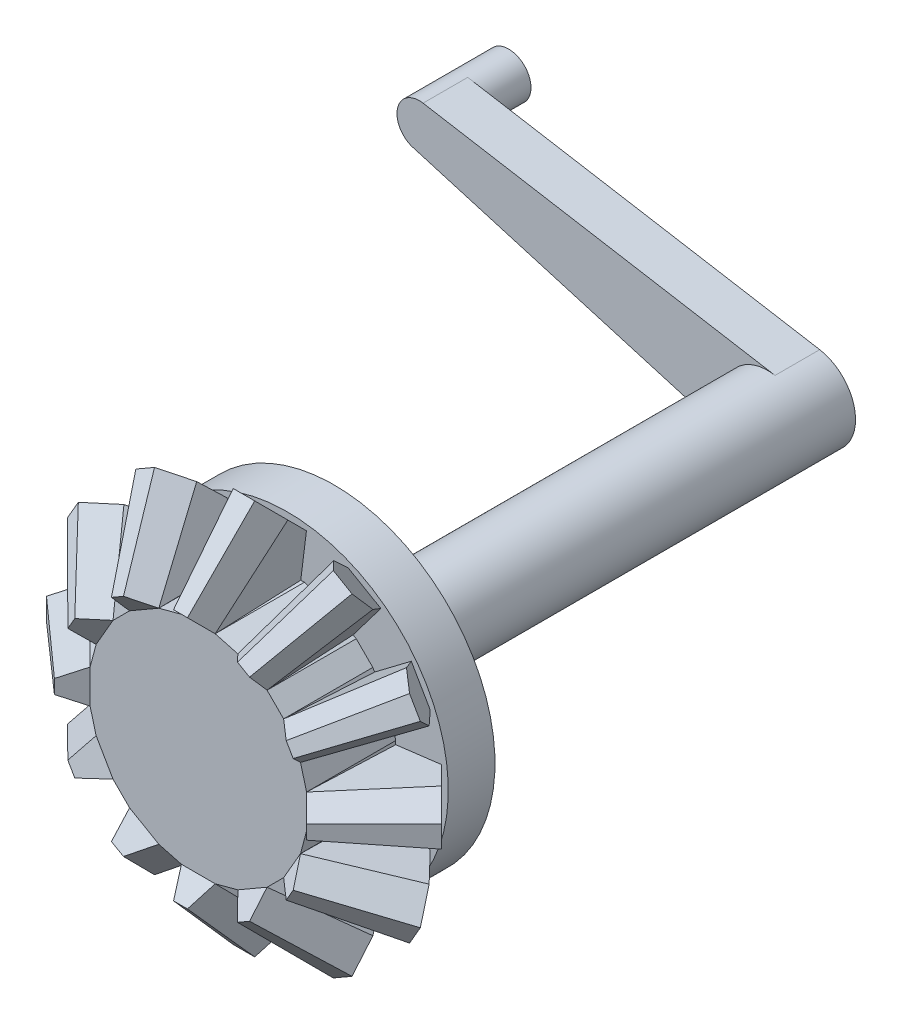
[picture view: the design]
ISO-10303-21;
HEADER;
FILE_DESCRIPTION(('STEP AP214'),'2;1');
FILE_NAME('part.step','',(''),(''),'','','');
FILE_SCHEMA(('AUTOMOTIVE_DESIGN { 1 0 10303 214 1 1 1 1 }'));
ENDSEC;
DATA;
#1=APPLICATION_CONTEXT('core data for automotive mechanical design processes');
#2=APPLICATION_PROTOCOL_DEFINITION('international standard','automotive_design',2000,#1);
#3=PRODUCT_CONTEXT('',#1,'mechanical');
#4=PRODUCT('Part','Part','',(#3));
#5=PRODUCT_RELATED_PRODUCT_CATEGORY('part','',(#4));
#6=PRODUCT_DEFINITION_FORMATION('','',#4);
#7=PRODUCT_DEFINITION_CONTEXT('part definition',#1,'design');
#8=PRODUCT_DEFINITION('design','',#6,#7);
#9=PRODUCT_DEFINITION_SHAPE('','',#8);
#10=(LENGTH_UNIT() NAMED_UNIT(*) SI_UNIT(.MILLI.,.METRE.));
#11=(NAMED_UNIT(*) PLANE_ANGLE_UNIT() SI_UNIT($,.RADIAN.));
#12=(NAMED_UNIT(*) SI_UNIT($,.STERADIAN.) SOLID_ANGLE_UNIT());
#13=UNCERTAINTY_MEASURE_WITH_UNIT(LENGTH_MEASURE(1.E-05),#10,'distance_accuracy_value','');
#14=(GEOMETRIC_REPRESENTATION_CONTEXT(3) GLOBAL_UNCERTAINTY_ASSIGNED_CONTEXT((#13)) GLOBAL_UNIT_ASSIGNED_CONTEXT((#10,
#11,#12)) REPRESENTATION_CONTEXT('',''));
#15=CARTESIAN_POINT('',(0.,0.,0.));
#16=DIRECTION('',(0.,0.,1.));
#17=DIRECTION('',(1.,0.,0.));
#18=AXIS2_PLACEMENT_3D('',#15,#16,#17);
#19=CARTESIAN_POINT('',(-1.11990909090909,0.,-91.7286207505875));
#20=DIRECTION('',(0.,0.,1.));
#21=DIRECTION('',(1.,0.,0.));
#22=AXIS2_PLACEMENT_3D('',#19,#20,#21);
#23=PLANE('',#22);
#24=DIRECTION('',(0.985868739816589,-0.167519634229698,0.));
#25=VECTOR('',#24,1.);
#26=CARTESIAN_POINT('',(2.13150734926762,12.133195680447,-91.7286207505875));
#27=LINE('',#26,#25);
#28=CARTESIAN_POINT('',(1.99577695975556,12.1562591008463,-91.7286207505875));
#29=VERTEX_POINT('',#28);
#30=CARTESIAN_POINT('',(2.13150734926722,12.1331956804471,-91.7286207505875));
#31=VERTEX_POINT('',#30);
#32=EDGE_CURVE('E11',#29,#31,#27,.T.);
#33=ORIENTED_EDGE('',*,*,#32,.F.);
#34=CARTESIAN_POINT('',(0.,0.,-91.7286207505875));
#35=DIRECTION('',(0.,0.,-1.));
#36=DIRECTION('',(-1.,0.,0.));
#37=AXIS2_PLACEMENT_3D('',#34,#35,#36);
#38=CIRCLE('',#37,12.319);
#39=EDGE_CURVE('E1470',#31,#29,#38,.F.);
#40=ORIENTED_EDGE('',*,*,#39,.F.);
#41=EDGE_LOOP('',(#33,#40));
#42=FACE_BOUND('',#41,.T.);
#43=ADVANCED_FACE('F31',(#42),#23,.F.);
#44=DIRECTION('',(-0.959413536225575,0.282002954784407,0.));
#45=VECTOR('',#44,1.);
#46=CARTESIAN_POINT('',(-3.40797278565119,-11.8382212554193,-91.7286207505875));
#47=LINE('',#46,#45);
#48=CARTESIAN_POINT('',(-3.40797278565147,-11.8382212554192,-91.7286207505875));
#49=VERTEX_POINT('',#48);
#50=CARTESIAN_POINT('',(-3.53990778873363,-11.7994412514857,-91.7286207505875));
#51=VERTEX_POINT('',#50);
#52=EDGE_CURVE('E1482',#49,#51,#47,.T.);
#53=ORIENTED_EDGE('',*,*,#52,.F.);
#54=EDGE_CURVE('E1456',#51,#49,#38,.F.);
#55=ORIENTED_EDGE('',*,*,#54,.F.);
#56=EDGE_LOOP('',(#53,#55));
#57=FACE_BOUND('',#56,.T.);
#58=ADVANCED_FACE('F1505',(#57),#23,.F.);
#59=CARTESIAN_POINT('',(-21.140822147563,30.4851911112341,76.2824021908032));
#60=DIRECTION('',(0.353553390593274,-0.612372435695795,0.707106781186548));
#61=DIRECTION('',(0.,-0.755928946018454,-0.654653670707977));
#62=AXIS2_PLACEMENT_3D('',#59,#60,#61);
#63=PLANE('',#62);
#64=DIRECTION('',(0.866025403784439,0.499999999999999,0.));
#65=VECTOR('',#64,1.);
#66=CARTESIAN_POINT('',(-19.6342231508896,30.0510904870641,75.1531605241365));
#67=LINE('',#66,#65);
#68=CARTESIAN_POINT('',(-19.6342231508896,30.0510904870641,75.1531605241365));
#69=VERTEX_POINT('',#68);
#70=CARTESIAN_POINT('',(-16.2078961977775,32.029281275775,75.1531605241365));
#71=VERTEX_POINT('',#70);
#72=EDGE_CURVE('E706',#69,#71,#67,.T.);
#73=ORIENTED_EDGE('',*,*,#72,.F.);
#74=DIRECTION('',(-0.0118343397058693,0.752940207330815,0.657982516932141));
#75=VECTOR('',#74,1.);
#76=CARTESIAN_POINT('',(-19.5430614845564,24.2510808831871,70.0846240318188));
#77=LINE('',#76,#75);
#78=CARTESIAN_POINT('',(-19.5430614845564,24.2510808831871,70.0846240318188));
#79=VERTEX_POINT('',#78);
#80=EDGE_CURVE('E711',#79,#69,#77,.T.);
#81=ORIENTED_EDGE('',*,*,#80,.F.);
#82=DIRECTION('',(-0.866025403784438,-0.5,0.));
#83=VECTOR('',#82,1.);
#84=CARTESIAN_POINT('',(-11.230521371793,29.0503281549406,70.0846240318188));
#85=LINE('',#84,#83);
#86=CARTESIAN_POINT('',(-11.230521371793,29.0503281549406,70.0846240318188));
#87=VERTEX_POINT('',#86);
#88=EDGE_CURVE('E804',#87,#79,#85,.T.);
#89=ORIENTED_EDGE('',*,*,#88,.F.);
#90=DIRECTION('',(0.646148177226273,-0.386718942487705,-0.657982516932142));
#91=VECTOR('',#90,1.);
#92=CARTESIAN_POINT('',(-16.2078961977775,32.029281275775,75.1531605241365));
#93=LINE('',#92,#91);
#94=EDGE_CURVE('E717',#71,#87,#93,.T.);
#95=ORIENTED_EDGE('',*,*,#94,.F.);
#96=EDGE_LOOP('',(#73,#81,#89,#95));
#97=FACE_BOUND('',#96,.T.);
#98=ADVANCED_FACE('F1510',(#97),#63,.T.);
#99=CARTESIAN_POINT('',(-33.5510845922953,15.8305388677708,76.2824021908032));
#100=DIRECTION('',(0.612372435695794,-0.353553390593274,0.707106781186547));
#101=DIRECTION('',(0.755928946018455,0.,-0.654653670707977));
#102=AXIS2_PLACEMENT_3D('',#99,#100,#101);
#103=PLANE('',#102);
#104=DIRECTION('',(0.499999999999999,0.866025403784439,0.));
#105=VECTOR('',#104,1.);
#106=CARTESIAN_POINT('',(-32.029281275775,16.2078961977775,75.1531605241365));
#107=LINE('',#106,#105);
#108=CARTESIAN_POINT('',(-32.029281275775,16.2078961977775,75.1531605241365));
#109=VERTEX_POINT('',#108);
#110=CARTESIAN_POINT('',(-30.051090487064,19.6342231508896,75.1531605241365));
#111=VERTEX_POINT('',#110);
#112=EDGE_CURVE('E692',#109,#111,#107,.T.);
#113=ORIENTED_EDGE('',*,*,#112,.F.);
#114=DIRECTION('',(-0.386718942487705,0.646148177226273,0.657982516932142));
#115=VECTOR('',#114,1.);
#116=CARTESIAN_POINT('',(-29.0503281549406,11.230521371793,70.0846240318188));
#117=LINE('',#116,#115);
#118=CARTESIAN_POINT('',(-29.0503281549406,11.230521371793,70.0846240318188));
#119=VERTEX_POINT('',#118);
#120=EDGE_CURVE('E697',#119,#109,#117,.T.);
#121=ORIENTED_EDGE('',*,*,#120,.F.);
#122=DIRECTION('',(-0.499999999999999,-0.866025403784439,0.));
#123=VECTOR('',#122,1.);
#124=CARTESIAN_POINT('',(-24.2510808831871,19.5430614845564,70.0846240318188));
#125=LINE('',#124,#123);
#126=CARTESIAN_POINT('',(-24.2510808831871,19.5430614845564,70.084624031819));
#127=VERTEX_POINT('',#126);
#128=EDGE_CURVE('E838',#127,#119,#125,.T.);
#129=ORIENTED_EDGE('',*,*,#128,.F.);
#130=DIRECTION('',(0.752940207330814,-0.0118343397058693,-0.657982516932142));
#131=VECTOR('',#130,1.);
#132=CARTESIAN_POINT('',(-30.051090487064,19.6342231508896,75.1531605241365));
#133=LINE('',#132,#131);
#134=EDGE_CURVE('E703',#111,#127,#133,.T.);
#135=ORIENTED_EDGE('',*,*,#134,.F.);
#136=EDGE_LOOP('',(#113,#121,#129,#135));
#137=FACE_BOUND('',#136,.T.);
#138=ADVANCED_FACE('F2340',(#137),#103,.T.);
#139=CARTESIAN_POINT('',(-36.9713610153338,-3.06589348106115,76.2824021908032));
#140=DIRECTION('',(0.707106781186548,0.,0.707106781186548));
#141=DIRECTION('',(0.707106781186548,0.,-0.707106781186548));
#142=AXIS2_PLACEMENT_3D('',#139,#140,#141);
#143=PLANE('',#142);
#144=DIRECTION('',(0.,1.,0.));
#145=VECTOR('',#144,1.);
#146=CARTESIAN_POINT('',(-35.8421193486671,-3.06589348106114,75.1531605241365));
#147=LINE('',#146,#145);
#148=CARTESIAN_POINT('',(-35.8421193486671,-1.97819078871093,75.1531605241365));
#149=VERTEX_POINT('',#148);
#150=CARTESIAN_POINT('',(-35.8421193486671,1.97819078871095,75.1531605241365));
#151=VERTEX_POINT('',#150);
#152=EDGE_CURVE('E678',#149,#151,#147,.T.);
#153=ORIENTED_EDGE('',*,*,#152,.F.);
#154=DIRECTION('',(-0.657982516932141,0.366221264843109,0.657982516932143));
#155=VECTOR('',#154,1.);
#156=CARTESIAN_POINT('',(-30.7735828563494,-4.79924727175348,70.0846240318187));
#157=LINE('',#156,#155);
#158=CARTESIAN_POINT('',(-30.7735828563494,-4.79924727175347,70.0846240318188));
#159=VERTEX_POINT('',#158);
#160=EDGE_CURVE('E683',#159,#149,#157,.T.);
#161=ORIENTED_EDGE('',*,*,#160,.F.);
#162=DIRECTION('',(0.,-1.,0.));
#163=VECTOR('',#162,1.);
#164=CARTESIAN_POINT('',(-30.7735828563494,0.,70.0846240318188));
#165=LINE('',#164,#163);
#166=CARTESIAN_POINT('',(-30.7735828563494,4.79924727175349,70.0846240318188));
#167=VERTEX_POINT('',#166);
#168=EDGE_CURVE('E835',#167,#159,#165,.T.);
#169=ORIENTED_EDGE('',*,*,#168,.F.);
#170=DIRECTION('',(0.657982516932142,0.366221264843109,-0.657982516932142));
#171=VECTOR('',#170,1.);
#172=CARTESIAN_POINT('',(-35.8421193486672,1.97819078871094,75.1531605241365));
#173=LINE('',#172,#171);
#174=EDGE_CURVE('E689',#151,#167,#173,.T.);
#175=ORIENTED_EDGE('',*,*,#174,.F.);
#176=EDGE_LOOP('',(#153,#161,#169,#175));
#177=FACE_BOUND('',#176,.T.);
#178=ADVANCED_FACE('F2347',(#177),#143,.T.);
#179=CARTESIAN_POINT('',(-30.4851911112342,-21.140822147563,76.2824021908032));
#180=DIRECTION('',(0.612372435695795,0.353553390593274,0.707106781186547));
#181=DIRECTION('',(0.755928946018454,0.,-0.654653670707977));
#182=AXIS2_PLACEMENT_3D('',#179,#180,#181);
#183=PLANE('',#182);
#184=DIRECTION('',(-0.5,0.866025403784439,0.));
#185=VECTOR('',#184,1.);
#186=CARTESIAN_POINT('',(-30.0510904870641,-19.6342231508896,75.1531605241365));
#187=LINE('',#186,#185);
#188=CARTESIAN_POINT('',(-30.0510904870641,-19.6342231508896,75.1531605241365));
#189=VERTEX_POINT('',#188);
#190=CARTESIAN_POINT('',(-32.029281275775,-16.2078961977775,75.1531605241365));
#191=VERTEX_POINT('',#190);
#192=EDGE_CURVE('E664',#189,#191,#187,.T.);
#193=ORIENTED_EDGE('',*,*,#192,.F.);
#194=DIRECTION('',(-0.752940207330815,-0.0118343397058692,0.657982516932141));
#195=VECTOR('',#194,1.);
#196=CARTESIAN_POINT('',(-24.2510808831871,-19.5430614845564,70.0846240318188));
#197=LINE('',#196,#195);
#198=CARTESIAN_POINT('',(-24.2510808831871,-19.5430614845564,70.0846240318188));
#199=VERTEX_POINT('',#198);
#200=EDGE_CURVE('E669',#199,#189,#197,.T.);
#201=ORIENTED_EDGE('',*,*,#200,.F.);
#202=DIRECTION('',(0.5,-0.866025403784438,0.));
#203=VECTOR('',#202,1.);
#204=CARTESIAN_POINT('',(-29.0503281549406,-11.230521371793,70.0846240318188));
#205=LINE('',#204,#203);
#206=CARTESIAN_POINT('',(-29.0503281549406,-11.230521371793,70.0846240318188));
#207=VERTEX_POINT('',#206);
#208=EDGE_CURVE('E832',#207,#199,#205,.T.);
#209=ORIENTED_EDGE('',*,*,#208,.F.);
#210=DIRECTION('',(0.386718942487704,0.646148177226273,-0.657982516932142));
#211=VECTOR('',#210,1.);
#212=CARTESIAN_POINT('',(-32.029281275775,-16.2078961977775,75.1531605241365));
#213=LINE('',#212,#211);
#214=EDGE_CURVE('E675',#191,#207,#213,.T.);
#215=ORIENTED_EDGE('',*,*,#214,.F.);
#216=EDGE_LOOP('',(#193,#201,#209,#215));
#217=FACE_BOUND('',#216,.T.);
#218=ADVANCED_FACE('F2355',(#217),#183,.T.);
#219=CARTESIAN_POINT('',(-15.8305388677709,-33.5510845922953,76.2824021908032));
#220=DIRECTION('',(0.353553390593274,0.612372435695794,0.707106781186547));
#221=DIRECTION('',(0.,-0.755928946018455,0.654653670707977));
#222=AXIS2_PLACEMENT_3D('',#219,#220,#221);
#223=PLANE('',#222);
#224=DIRECTION('',(-0.866025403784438,0.500000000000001,0.));
#225=VECTOR('',#224,1.);
#226=CARTESIAN_POINT('',(-16.2078961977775,-32.029281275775,75.1531605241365));
#227=LINE('',#226,#225);
#228=CARTESIAN_POINT('',(-16.2078961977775,-32.029281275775,75.1531605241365));
#229=VERTEX_POINT('',#228);
#230=CARTESIAN_POINT('',(-19.6342231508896,-30.051090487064,75.1531605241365));
#231=VERTEX_POINT('',#230);
#232=EDGE_CURVE('E650',#229,#231,#227,.T.);
#233=ORIENTED_EDGE('',*,*,#232,.F.);
#234=DIRECTION('',(-0.646148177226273,-0.386718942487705,0.657982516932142));
#235=VECTOR('',#234,1.);
#236=CARTESIAN_POINT('',(-11.230521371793,-29.0503281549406,70.0846240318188));
#237=LINE('',#236,#235);
#238=CARTESIAN_POINT('',(-11.230521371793,-29.0503281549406,70.0846240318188));
#239=VERTEX_POINT('',#238);
#240=EDGE_CURVE('E655',#239,#229,#237,.T.);
#241=ORIENTED_EDGE('',*,*,#240,.F.);
#242=DIRECTION('',(0.866025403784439,-0.5,0.));
#243=VECTOR('',#242,1.);
#244=CARTESIAN_POINT('',(-19.5430614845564,-24.2510808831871,70.0846240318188));
#245=LINE('',#244,#243);
#246=CARTESIAN_POINT('',(-19.5430614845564,-24.2510808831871,70.084624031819));
#247=VERTEX_POINT('',#246);
#248=EDGE_CURVE('E829',#247,#239,#245,.T.);
#249=ORIENTED_EDGE('',*,*,#248,.F.);
#250=DIRECTION('',(0.0118343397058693,0.752940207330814,-0.657982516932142));
#251=VECTOR('',#250,1.);
#252=CARTESIAN_POINT('',(-19.6342231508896,-30.051090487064,75.1531605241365));
#253=LINE('',#252,#251);
#254=EDGE_CURVE('E661',#231,#247,#253,.T.);
#255=ORIENTED_EDGE('',*,*,#254,.F.);
#256=EDGE_LOOP('',(#233,#241,#249,#255));
#257=FACE_BOUND('',#256,.T.);
#258=ADVANCED_FACE('F2363',(#257),#223,.T.);
#259=CARTESIAN_POINT('',(3.06589348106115,-36.9713610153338,76.2824021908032));
#260=DIRECTION('',(0.,0.707106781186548,0.707106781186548));
#261=DIRECTION('',(0.,-0.707106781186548,0.707106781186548));
#262=AXIS2_PLACEMENT_3D('',#259,#260,#261);
#263=PLANE('',#262);
#264=DIRECTION('',(1.,0.,0.));
#265=VECTOR('',#264,1.);
#266=CARTESIAN_POINT('',(3.06589348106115,-35.8421193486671,75.1531605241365));
#267=LINE('',#266,#265);
#268=CARTESIAN_POINT('',(1.97819078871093,-35.8421193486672,75.1531605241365));
#269=VERTEX_POINT('',#268);
#270=CARTESIAN_POINT('',(-1.97819078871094,-35.8421193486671,75.1531605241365));
#271=VERTEX_POINT('',#270);
#272=EDGE_CURVE('E637',#269,#271,#267,.F.);
#273=ORIENTED_EDGE('',*,*,#272,.F.);
#274=DIRECTION('',(-0.366221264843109,-0.657982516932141,0.657982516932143));
#275=VECTOR('',#274,1.);
#276=CARTESIAN_POINT('',(4.79924727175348,-30.7735828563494,70.0846240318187));
#277=LINE('',#276,#275);
#278=CARTESIAN_POINT('',(4.79924727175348,-30.7735828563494,70.0846240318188));
#279=VERTEX_POINT('',#278);
#280=EDGE_CURVE('E641',#279,#269,#277,.T.);
#281=ORIENTED_EDGE('',*,*,#280,.F.);
#282=DIRECTION('',(1.,0.,0.));
#283=VECTOR('',#282,1.);
#284=CARTESIAN_POINT('',(0.,-30.7735828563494,70.0846240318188));
#285=LINE('',#284,#283);
#286=CARTESIAN_POINT('',(-4.79924727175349,-30.7735828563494,70.0846240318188));
#287=VERTEX_POINT('',#286);
#288=EDGE_CURVE('E826',#287,#279,#285,.T.);
#289=ORIENTED_EDGE('',*,*,#288,.F.);
#290=DIRECTION('',(-0.366221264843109,0.657982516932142,-0.657982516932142));
#291=VECTOR('',#290,1.);
#292=CARTESIAN_POINT('',(-1.97819078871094,-35.8421193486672,75.1531605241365));
#293=LINE('',#292,#291);
#294=EDGE_CURVE('E647',#271,#287,#293,.T.);
#295=ORIENTED_EDGE('',*,*,#294,.F.);
#296=EDGE_LOOP('',(#273,#281,#289,#295));
#297=FACE_BOUND('',#296,.T.);
#298=ADVANCED_FACE('F2371',(#297),#263,.T.);
#299=CARTESIAN_POINT('',(21.140822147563,-30.4851911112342,76.2824021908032));
#300=DIRECTION('',(-0.353553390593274,0.612372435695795,0.707106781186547));
#301=DIRECTION('',(0.,-0.755928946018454,0.654653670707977));
#302=AXIS2_PLACEMENT_3D('',#299,#300,#301);
#303=PLANE('',#302);
#304=DIRECTION('',(-0.866025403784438,-0.5,0.));
#305=VECTOR('',#304,1.);
#306=CARTESIAN_POINT('',(19.6342231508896,-30.0510904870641,75.1531605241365));
#307=LINE('',#306,#305);
#308=CARTESIAN_POINT('',(19.6342231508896,-30.0510904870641,75.1531605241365));
#309=VERTEX_POINT('',#308);
#310=CARTESIAN_POINT('',(16.2078961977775,-32.029281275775,75.1531605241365));
#311=VERTEX_POINT('',#310);
#312=EDGE_CURVE('E790',#309,#311,#307,.T.);
#313=ORIENTED_EDGE('',*,*,#312,.F.);
#314=DIRECTION('',(0.0118343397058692,-0.752940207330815,0.657982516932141));
#315=VECTOR('',#314,1.);
#316=CARTESIAN_POINT('',(19.5430614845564,-24.2510808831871,70.0846240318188));
#317=LINE('',#316,#315);
#318=CARTESIAN_POINT('',(19.5430614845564,-24.2510808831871,70.0846240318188));
#319=VERTEX_POINT('',#318);
#320=EDGE_CURVE('E795',#319,#309,#317,.T.);
#321=ORIENTED_EDGE('',*,*,#320,.F.);
#322=DIRECTION('',(0.866025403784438,0.5,0.));
#323=VECTOR('',#322,1.);
#324=CARTESIAN_POINT('',(11.230521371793,-29.0503281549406,70.0846240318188));
#325=LINE('',#324,#323);
#326=CARTESIAN_POINT('',(11.230521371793,-29.0503281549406,70.0846240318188));
#327=VERTEX_POINT('',#326);
#328=EDGE_CURVE('E823',#327,#319,#325,.T.);
#329=ORIENTED_EDGE('',*,*,#328,.F.);
#330=DIRECTION('',(-0.646148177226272,0.386718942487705,-0.657982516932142));
#331=VECTOR('',#330,1.);
#332=CARTESIAN_POINT('',(16.2078961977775,-32.029281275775,75.1531605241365));
#333=LINE('',#332,#331);
#334=EDGE_CURVE('E801',#311,#327,#333,.T.);
#335=ORIENTED_EDGE('',*,*,#334,.F.);
#336=EDGE_LOOP('',(#313,#321,#329,#335));
#337=FACE_BOUND('',#336,.T.);
#338=ADVANCED_FACE('F1979',(#337),#303,.T.);
#339=CARTESIAN_POINT('',(33.5510845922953,-15.8305388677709,76.2824021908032));
#340=DIRECTION('',(-0.612372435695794,0.353553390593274,0.707106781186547));
#341=DIRECTION('',(0.755928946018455,0.,0.654653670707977));
#342=AXIS2_PLACEMENT_3D('',#339,#340,#341);
#343=PLANE('',#342);
#344=DIRECTION('',(-0.500000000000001,-0.866025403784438,0.));
#345=VECTOR('',#344,1.);
#346=CARTESIAN_POINT('',(32.029281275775,-16.2078961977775,75.1531605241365));
#347=LINE('',#346,#345);
#348=CARTESIAN_POINT('',(32.029281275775,-16.2078961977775,75.1531605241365));
#349=VERTEX_POINT('',#348);
#350=CARTESIAN_POINT('',(30.051090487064,-19.6342231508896,75.1531605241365));
#351=VERTEX_POINT('',#350);
#352=EDGE_CURVE('E776',#349,#351,#347,.T.);
#353=ORIENTED_EDGE('',*,*,#352,.F.);
#354=DIRECTION('',(0.386718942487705,-0.646148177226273,0.657982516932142));
#355=VECTOR('',#354,1.);
#356=CARTESIAN_POINT('',(29.0503281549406,-11.230521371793,70.0846240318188));
#357=LINE('',#356,#355);
#358=CARTESIAN_POINT('',(29.0503281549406,-11.230521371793,70.0846240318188));
#359=VERTEX_POINT('',#358);
#360=EDGE_CURVE('E781',#359,#349,#357,.T.);
#361=ORIENTED_EDGE('',*,*,#360,.F.);
#362=DIRECTION('',(0.5,0.866025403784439,0.));
#363=VECTOR('',#362,1.);
#364=CARTESIAN_POINT('',(24.2510808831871,-19.5430614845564,70.0846240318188));
#365=LINE('',#364,#363);
#366=CARTESIAN_POINT('',(24.2510808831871,-19.5430614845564,70.084624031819));
#367=VERTEX_POINT('',#366);
#368=EDGE_CURVE('E820',#367,#359,#365,.T.);
#369=ORIENTED_EDGE('',*,*,#368,.F.);
#370=DIRECTION('',(-0.752940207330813,0.0118343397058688,-0.657982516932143));
#371=VECTOR('',#370,1.);
#372=CARTESIAN_POINT('',(30.051090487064,-19.6342231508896,75.1531605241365));
#373=LINE('',#372,#371);
#374=EDGE_CURVE('E787',#351,#367,#373,.T.);
#375=ORIENTED_EDGE('',*,*,#374,.F.);
#376=EDGE_LOOP('',(#353,#361,#369,#375));
#377=FACE_BOUND('',#376,.T.);
#378=ADVANCED_FACE('F1983',(#377),#343,.T.);
#379=CARTESIAN_POINT('',(36.9713610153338,3.06589348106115,76.2824021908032));
#380=DIRECTION('',(-0.707106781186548,0.,0.707106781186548));
#381=DIRECTION('',(0.707106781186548,0.,0.707106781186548));
#382=AXIS2_PLACEMENT_3D('',#379,#380,#381);
#383=PLANE('',#382);
#384=DIRECTION('',(0.,1.,0.));
#385=VECTOR('',#384,1.);
#386=CARTESIAN_POINT('',(35.8421193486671,3.06589348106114,75.1531605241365));
#387=LINE('',#386,#385);
#388=CARTESIAN_POINT('',(35.8421193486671,1.97819078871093,75.1531605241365));
#389=VERTEX_POINT('',#388);
#390=CARTESIAN_POINT('',(35.8421193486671,-1.97819078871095,75.1531605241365));
#391=VERTEX_POINT('',#390);
#392=EDGE_CURVE('E762',#389,#391,#387,.F.);
#393=ORIENTED_EDGE('',*,*,#392,.F.);
#394=DIRECTION('',(0.657982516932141,-0.366221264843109,0.657982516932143));
#395=VECTOR('',#394,1.);
#396=CARTESIAN_POINT('',(30.7735828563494,4.79924727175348,70.0846240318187));
#397=LINE('',#396,#395);
#398=CARTESIAN_POINT('',(30.7735828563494,4.79924727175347,70.0846240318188));
#399=VERTEX_POINT('',#398);
#400=EDGE_CURVE('E767',#399,#389,#397,.T.);
#401=ORIENTED_EDGE('',*,*,#400,.F.);
#402=DIRECTION('',(0.,-1.,0.));
#403=VECTOR('',#402,1.);
#404=CARTESIAN_POINT('',(30.7735828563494,0.,70.0846240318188));
#405=LINE('',#404,#403);
#406=CARTESIAN_POINT('',(30.7735828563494,-4.79924727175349,70.0846240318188));
#407=VERTEX_POINT('',#406);
#408=EDGE_CURVE('E817',#407,#399,#405,.F.);
#409=ORIENTED_EDGE('',*,*,#408,.F.);
#410=DIRECTION('',(-0.657982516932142,-0.366221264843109,-0.657982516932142));
#411=VECTOR('',#410,1.);
#412=CARTESIAN_POINT('',(35.8421193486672,-1.97819078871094,75.1531605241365));
#413=LINE('',#412,#411);
#414=EDGE_CURVE('E773',#391,#407,#413,.T.);
#415=ORIENTED_EDGE('',*,*,#414,.F.);
#416=EDGE_LOOP('',(#393,#401,#409,#415));
#417=FACE_BOUND('',#416,.T.);
#418=ADVANCED_FACE('F2391',(#417),#383,.T.);
#419=CARTESIAN_POINT('',(30.4851911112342,21.140822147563,76.2824021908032));
#420=DIRECTION('',(-0.612372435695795,-0.353553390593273,0.707106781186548));
#421=DIRECTION('',(0.755928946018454,0.,0.654653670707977));
#422=AXIS2_PLACEMENT_3D('',#419,#420,#421);
#423=PLANE('',#422);
#424=DIRECTION('',(0.5,-0.866025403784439,0.));
#425=VECTOR('',#424,1.);
#426=CARTESIAN_POINT('',(30.0510904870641,19.6342231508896,75.1531605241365));
#427=LINE('',#426,#425);
#428=CARTESIAN_POINT('',(30.0510904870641,19.6342231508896,75.1531605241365));
#429=VERTEX_POINT('',#428);
#430=CARTESIAN_POINT('',(32.029281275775,16.2078961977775,75.1531605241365));
#431=VERTEX_POINT('',#430);
#432=EDGE_CURVE('E748',#429,#431,#427,.T.);
#433=ORIENTED_EDGE('',*,*,#432,.F.);
#434=DIRECTION('',(0.752940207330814,0.0118343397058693,0.657982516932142));
#435=VECTOR('',#434,1.);
#436=CARTESIAN_POINT('',(24.2510808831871,19.5430614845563,70.0846240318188));
#437=LINE('',#436,#435);
#438=CARTESIAN_POINT('',(24.2510808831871,19.5430614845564,70.0846240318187));
#439=VERTEX_POINT('',#438);
#440=EDGE_CURVE('E753',#439,#429,#437,.T.);
#441=ORIENTED_EDGE('',*,*,#440,.F.);
#442=DIRECTION('',(-0.5,0.866025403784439,0.));
#443=VECTOR('',#442,1.);
#444=CARTESIAN_POINT('',(29.0503281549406,11.230521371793,70.0846240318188));
#445=LINE('',#444,#443);
#446=CARTESIAN_POINT('',(29.0503281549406,11.230521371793,70.0846240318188));
#447=VERTEX_POINT('',#446);
#448=EDGE_CURVE('E814',#447,#439,#445,.T.);
#449=ORIENTED_EDGE('',*,*,#448,.F.);
#450=DIRECTION('',(-0.386718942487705,-0.646148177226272,-0.657982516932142));
#451=VECTOR('',#450,1.);
#452=CARTESIAN_POINT('',(32.029281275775,16.2078961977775,75.1531605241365));
#453=LINE('',#452,#451);
#454=EDGE_CURVE('E759',#431,#447,#453,.T.);
#455=ORIENTED_EDGE('',*,*,#454,.F.);
#456=EDGE_LOOP('',(#433,#441,#449,#455));
#457=FACE_BOUND('',#456,.T.);
#458=ADVANCED_FACE('F2398',(#457),#423,.T.);
#459=CARTESIAN_POINT('',(15.8305388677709,33.5510845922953,76.2824021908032));
#460=DIRECTION('',(-0.353553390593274,-0.612372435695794,0.707106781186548));
#461=DIRECTION('',(0.,-0.755928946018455,-0.654653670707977));
#462=AXIS2_PLACEMENT_3D('',#459,#460,#461);
#463=PLANE('',#462);
#464=DIRECTION('',(0.866025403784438,-0.500000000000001,0.));
#465=VECTOR('',#464,1.);
#466=CARTESIAN_POINT('',(16.2078961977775,32.029281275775,75.1531605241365));
#467=LINE('',#466,#465);
#468=CARTESIAN_POINT('',(16.2078961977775,32.029281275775,75.1531605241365));
#469=VERTEX_POINT('',#468);
#470=CARTESIAN_POINT('',(19.6342231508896,30.051090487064,75.1531605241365));
#471=VERTEX_POINT('',#470);
#472=EDGE_CURVE('E734',#469,#471,#467,.T.);
#473=ORIENTED_EDGE('',*,*,#472,.F.);
#474=DIRECTION('',(0.646148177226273,0.386718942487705,0.657982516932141));
#475=VECTOR('',#474,1.);
#476=CARTESIAN_POINT('',(11.230521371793,29.0503281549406,70.0846240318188));
#477=LINE('',#476,#475);
#478=CARTESIAN_POINT('',(11.230521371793,29.0503281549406,70.0846240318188));
#479=VERTEX_POINT('',#478);
#480=EDGE_CURVE('E739',#479,#469,#477,.T.);
#481=ORIENTED_EDGE('',*,*,#480,.F.);
#482=DIRECTION('',(-0.866025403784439,0.5,0.));
#483=VECTOR('',#482,1.);
#484=CARTESIAN_POINT('',(19.5430614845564,24.2510808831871,70.0846240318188));
#485=LINE('',#484,#483);
#486=CARTESIAN_POINT('',(19.5430614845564,24.2510808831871,70.084624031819));
#487=VERTEX_POINT('',#486);
#488=EDGE_CURVE('E811',#487,#479,#485,.T.);
#489=ORIENTED_EDGE('',*,*,#488,.F.);
#490=DIRECTION('',(-0.0118343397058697,-0.752940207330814,-0.657982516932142));
#491=VECTOR('',#490,1.);
#492=CARTESIAN_POINT('',(19.6342231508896,30.051090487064,75.1531605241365));
#493=LINE('',#492,#491);
#494=EDGE_CURVE('E745',#471,#487,#493,.T.);
#495=ORIENTED_EDGE('',*,*,#494,.F.);
#496=EDGE_LOOP('',(#473,#481,#489,#495));
#497=FACE_BOUND('',#496,.T.);
#498=ADVANCED_FACE('F2406',(#497),#463,.T.);
#499=CARTESIAN_POINT('',(-3.06589348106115,36.9713610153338,76.2824021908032));
#500=DIRECTION('',(0.,-0.707106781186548,0.707106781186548));
#501=DIRECTION('',(0.,-0.707106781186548,-0.707106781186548));
#502=AXIS2_PLACEMENT_3D('',#499,#500,#501);
#503=PLANE('',#502);
#504=DIRECTION('',(1.,0.,0.));
#505=VECTOR('',#504,1.);
#506=CARTESIAN_POINT('',(-3.06589348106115,35.8421193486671,75.1531605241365));
#507=LINE('',#506,#505);
#508=CARTESIAN_POINT('',(-1.97819078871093,35.8421193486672,75.1531605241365));
#509=VERTEX_POINT('',#508);
#510=CARTESIAN_POINT('',(1.97819078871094,35.8421193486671,75.1531605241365));
#511=VERTEX_POINT('',#510);
#512=EDGE_CURVE('E720',#509,#511,#507,.T.);
#513=ORIENTED_EDGE('',*,*,#512,.F.);
#514=DIRECTION('',(0.366221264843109,0.657982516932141,0.657982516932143));
#515=VECTOR('',#514,1.);
#516=CARTESIAN_POINT('',(-4.79924727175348,30.7735828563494,70.0846240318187));
#517=LINE('',#516,#515);
#518=CARTESIAN_POINT('',(-4.79924727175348,30.7735828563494,70.0846240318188));
#519=VERTEX_POINT('',#518);
#520=EDGE_CURVE('E725',#519,#509,#517,.T.);
#521=ORIENTED_EDGE('',*,*,#520,.F.);
#522=DIRECTION('',(1.,0.,0.));
#523=VECTOR('',#522,1.);
#524=CARTESIAN_POINT('',(0.,30.7735828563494,70.0846240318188));
#525=LINE('',#524,#523);
#526=CARTESIAN_POINT('',(4.79924727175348,30.7735828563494,70.0846240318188));
#527=VERTEX_POINT('',#526);
#528=EDGE_CURVE('E807',#527,#519,#525,.F.);
#529=ORIENTED_EDGE('',*,*,#528,.F.);
#530=DIRECTION('',(0.36622126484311,-0.657982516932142,-0.657982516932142));
#531=VECTOR('',#530,1.);
#532=CARTESIAN_POINT('',(1.97819078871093,35.8421193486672,75.1531605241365));
#533=LINE('',#532,#531);
#534=EDGE_CURVE('E731',#511,#527,#533,.T.);
#535=ORIENTED_EDGE('',*,*,#534,.F.);
#536=EDGE_LOOP('',(#513,#521,#529,#535));
#537=FACE_BOUND('',#536,.T.);
#538=ADVANCED_FACE('F2414',(#537),#503,.T.);
#539=CARTESIAN_POINT('',(3.06589348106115,-56.1352275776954,57.1185356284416));
#540=DIRECTION('',(0.,-0.664287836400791,0.747476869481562));
#541=DIRECTION('',(0.,-0.747476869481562,-0.664287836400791));
#542=AXIS2_PLACEMENT_3D('',#539,#540,#541);
#543=PLANE('',#542);
#544=DIRECTION('',(0.0400323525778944,-0.746877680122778,-0.663755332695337));
#545=VECTOR('',#544,1.);
#546=CARTESIAN_POINT('',(1.97819078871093,-35.8421193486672,75.1531605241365));
#547=LINE('',#546,#545);
#548=CARTESIAN_POINT('',(3.06589348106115,-56.1352275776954,57.1185356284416));
#549=VERTEX_POINT('',#548);
#550=EDGE_CURVE('E639',#269,#549,#547,.T.);
#551=ORIENTED_EDGE('',*,*,#550,.F.);
#552=ORIENTED_EDGE('',*,*,#272,.T.);
#553=DIRECTION('',(0.0400323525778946,0.746877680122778,0.663755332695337));
#554=VECTOR('',#553,1.);
#555=CARTESIAN_POINT('',(-3.06589348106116,-56.1352275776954,57.1185356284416));
#556=LINE('',#555,#554);
#557=CARTESIAN_POINT('',(-3.06589348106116,-56.1352275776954,57.1185356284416));
#558=VERTEX_POINT('',#557);
#559=EDGE_CURVE('E644',#558,#271,#556,.T.);
#560=ORIENTED_EDGE('',*,*,#559,.F.);
#561=DIRECTION('',(1.,0.,0.));
#562=VECTOR('',#561,1.);
#563=CARTESIAN_POINT('',(-0.0109063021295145,-56.1352275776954,57.1185356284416));
#564=LINE('',#563,#562);
#565=EDGE_CURVE('E854',#558,#549,#564,.T.);
#566=ORIENTED_EDGE('',*,*,#565,.T.);
#567=EDGE_LOOP('',(#551,#552,#560,#566));
#568=FACE_BOUND('',#567,.T.);
#569=ADVANCED_FACE('F2422',(#568),#543,.T.);
#570=CARTESIAN_POINT('',(6.43180864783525,-50.0877542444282,51.0710622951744));
#571=DIRECTION('',(0.928916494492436,-0.216914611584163,0.300103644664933));
#572=DIRECTION('',(0.307423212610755,0.,-0.951572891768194));
#573=AXIS2_PLACEMENT_3D('',#570,#571,#572);
#574=PLANE('',#573);
#575=DIRECTION('',(0.0601272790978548,-0.711341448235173,-0.700269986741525));
#576=VECTOR('',#575,1.);
#577=CARTESIAN_POINT('',(4.79924727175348,-30.7735828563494,70.0846240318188));
#578=LINE('',#577,#576);
#579=CARTESIAN_POINT('',(6.43180864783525,-50.0877542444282,51.0710622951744));
#580=VERTEX_POINT('',#579);
#581=EDGE_CURVE('E843',#279,#580,#578,.T.);
#582=ORIENTED_EDGE('',*,*,#581,.F.);
#583=ORIENTED_EDGE('',*,*,#280,.T.);
#584=ORIENTED_EDGE('',*,*,#550,.T.);
#585=DIRECTION('',(0.366221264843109,0.657982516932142,-0.657982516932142));
#586=VECTOR('',#585,1.);
#587=CARTESIAN_POINT('',(3.06589348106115,-56.1352275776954,57.1185356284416));
#588=LINE('',#587,#586);
#589=EDGE_CURVE('E852',#549,#580,#588,.T.);
#590=ORIENTED_EDGE('',*,*,#589,.T.);
#591=EDGE_LOOP('',(#582,#583,#584,#590));
#592=FACE_BOUND('',#591,.T.);
#593=ADVANCED_FACE('F1839',(#592),#574,.T.);
#594=CARTESIAN_POINT('',(-3.06589348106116,-56.1352275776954,57.1185356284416));
#595=DIRECTION('',(-0.928916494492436,-0.216914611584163,0.300103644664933));
#596=DIRECTION('',(0.307423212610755,0.,0.951572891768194));
#597=AXIS2_PLACEMENT_3D('',#594,#595,#596);
#598=PLANE('',#597);
#599=ORIENTED_EDGE('',*,*,#559,.T.);
#600=ORIENTED_EDGE('',*,*,#294,.T.);
#601=DIRECTION('',(0.060127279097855,0.711341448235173,0.700269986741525));
#602=VECTOR('',#601,1.);
#603=CARTESIAN_POINT('',(-6.43180864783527,-50.0877542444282,51.0710622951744));
#604=LINE('',#603,#602);
#605=CARTESIAN_POINT('',(-6.43180864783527,-50.0877542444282,51.0710622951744));
#606=VERTEX_POINT('',#605);
#607=EDGE_CURVE('E858',#606,#287,#604,.T.);
#608=ORIENTED_EDGE('',*,*,#607,.F.);
#609=DIRECTION('',(0.366221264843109,-0.657982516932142,0.657982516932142));
#610=VECTOR('',#609,1.);
#611=CARTESIAN_POINT('',(-6.43180864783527,-50.0877542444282,51.0710622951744));
#612=LINE('',#611,#610);
#613=EDGE_CURVE('E846',#606,#558,#612,.T.);
#614=ORIENTED_EDGE('',*,*,#613,.T.);
#615=EDGE_LOOP('',(#599,#600,#608,#614));
#616=FACE_BOUND('',#615,.T.);
#617=ADVANCED_FACE('F2437',(#616),#598,.T.);
#618=CARTESIAN_POINT('',(-25.4124721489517,-50.1474798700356,57.1185356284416));
#619=DIRECTION('',(-0.332143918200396,-0.575290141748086,0.747476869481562));
#620=DIRECTION('',(0.,-0.792466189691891,-0.609915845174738));
#621=AXIS2_PLACEMENT_3D('',#618,#619,#620);
#622=PLANE('',#621);
#623=DIRECTION('',(-0.338769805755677,-0.66683122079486,-0.663755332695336));
#624=VECTOR('',#623,1.);
#625=CARTESIAN_POINT('',(-16.2078961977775,-32.029281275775,75.1531605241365));
#626=LINE('',#625,#624);
#627=CARTESIAN_POINT('',(-25.4124721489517,-50.1474798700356,57.1185356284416));
#628=VERTEX_POINT('',#627);
#629=EDGE_CURVE('E654',#229,#628,#626,.T.);
#630=ORIENTED_EDGE('',*,*,#629,.F.);
#631=ORIENTED_EDGE('',*,*,#232,.T.);
#632=DIRECTION('',(0.408107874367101,0.626798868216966,0.663755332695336));
#633=VECTOR('',#632,1.);
#634=CARTESIAN_POINT('',(-30.7227554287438,-47.0815863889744,57.1185356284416));
#635=LINE('',#634,#633);
#636=CARTESIAN_POINT('',(-30.7227554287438,-47.0815863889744,57.1185356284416));
#637=VERTEX_POINT('',#636);
#638=EDGE_CURVE('E658',#637,#231,#635,.T.);
#639=ORIENTED_EDGE('',*,*,#638,.F.);
#640=DIRECTION('',(0.866025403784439,-0.5,0.));
#641=VECTOR('',#640,1.);
#642=CARTESIAN_POINT('',(-30.7227554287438,-47.0815863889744,57.1185356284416));
#643=LINE('',#642,#641);
#644=EDGE_CURVE('E887',#637,#628,#643,.T.);
#645=ORIENTED_EDGE('',*,*,#644,.T.);
#646=EDGE_LOOP('',(#630,#631,#639,#645));
#647=FACE_BOUND('',#646,.T.);
#648=ADVANCED_FACE('F2444',(#647),#622,.T.);
#649=CARTESIAN_POINT('',(-19.4737674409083,-46.5931719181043,51.0710622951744));
#650=DIRECTION('',(0.696007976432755,-0.652311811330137,0.300103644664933));
#651=DIRECTION('',(0.683831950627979,0.729639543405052,0.));
#652=AXIS2_PLACEMENT_3D('',#649,#650,#651);
#653=PLANE('',#652);
#654=DIRECTION('',(-0.303598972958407,-0.6461034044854,-0.700269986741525));
#655=VECTOR('',#654,1.);
#656=CARTESIAN_POINT('',(-11.230521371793,-29.0503281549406,70.0846240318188));
#657=LINE('',#656,#655);
#658=CARTESIAN_POINT('',(-19.4737674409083,-46.5931719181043,51.0710622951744));
#659=VERTEX_POINT('',#658);
#660=EDGE_CURVE('E876',#239,#659,#657,.T.);
#661=ORIENTED_EDGE('',*,*,#660,.F.);
#662=ORIENTED_EDGE('',*,*,#240,.T.);
#663=ORIENTED_EDGE('',*,*,#629,.T.);
#664=DIRECTION('',(0.646148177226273,0.386718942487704,-0.657982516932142));
#665=VECTOR('',#664,1.);
#666=CARTESIAN_POINT('',(-25.4124721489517,-50.1474798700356,57.1185356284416));
#667=LINE('',#666,#665);
#668=EDGE_CURVE('E885',#628,#659,#667,.T.);
#669=ORIENTED_EDGE('',*,*,#668,.T.);
#670=EDGE_LOOP('',(#661,#662,#663,#669));
#671=FACE_BOUND('',#670,.T.);
#672=ADVANCED_FACE('F2452',(#671),#653,.T.);
#673=CARTESIAN_POINT('',(-30.7227554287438,-47.0815863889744,57.1185356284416));
#674=DIRECTION('',(-0.912922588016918,0.276604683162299,0.300103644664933));
#675=DIRECTION('',(0.312287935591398,0.,0.949987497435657));
#676=AXIS2_PLACEMENT_3D('',#673,#674,#675);
#677=PLANE('',#676);
#678=ORIENTED_EDGE('',*,*,#638,.T.);
#679=ORIENTED_EDGE('',*,*,#254,.T.);
#680=DIRECTION('',(0.407742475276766,0.585976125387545,0.700269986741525));
#681=VECTOR('',#680,1.);
#682=CARTESIAN_POINT('',(-30.6139868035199,-40.161363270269,51.0710622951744));
#683=LINE('',#682,#681);
#684=CARTESIAN_POINT('',(-30.6139868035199,-40.161363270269,51.0710622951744));
#685=VERTEX_POINT('',#684);
#686=EDGE_CURVE('E891',#685,#247,#683,.T.);
#687=ORIENTED_EDGE('',*,*,#686,.F.);
#688=DIRECTION('',(-0.01183433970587,-0.752940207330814,0.657982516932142));
#689=VECTOR('',#688,1.);
#690=CARTESIAN_POINT('',(-30.6139868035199,-40.161363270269,51.0710622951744));
#691=LINE('',#690,#689);
#692=EDGE_CURVE('E879',#685,#637,#691,.T.);
#693=ORIENTED_EDGE('',*,*,#692,.T.);
#694=EDGE_LOOP('',(#678,#679,#687,#693));
#695=FACE_BOUND('',#694,.T.);
#696=ADVANCED_FACE('F2460',(#695),#677,.T.);
#697=CARTESIAN_POINT('',(-47.0815863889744,-30.7227554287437,57.1185356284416));
#698=DIRECTION('',(-0.575290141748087,-0.332143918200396,0.747476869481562));
#699=DIRECTION('',(0.792466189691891,0.,0.609915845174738));
#700=AXIS2_PLACEMENT_3D('',#697,#698,#699);
#701=PLANE('',#700);
#702=DIRECTION('',(-0.626798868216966,-0.408107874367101,-0.663755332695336));
#703=VECTOR('',#702,1.);
#704=CARTESIAN_POINT('',(-30.0510904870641,-19.6342231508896,75.1531605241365));
#705=LINE('',#704,#703);
#706=CARTESIAN_POINT('',(-47.0815863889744,-30.7227554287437,57.1185356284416));
#707=VERTEX_POINT('',#706);
#708=EDGE_CURVE('E668',#189,#707,#705,.T.);
#709=ORIENTED_EDGE('',*,*,#708,.F.);
#710=ORIENTED_EDGE('',*,*,#192,.T.);
#711=DIRECTION('',(0.666831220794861,0.338769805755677,0.663755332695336));
#712=VECTOR('',#711,1.);
#713=CARTESIAN_POINT('',(-50.1474798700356,-25.4124721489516,57.1185356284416));
#714=LINE('',#713,#712);
#715=CARTESIAN_POINT('',(-50.1474798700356,-25.4124721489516,57.1185356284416));
#716=VERTEX_POINT('',#715);
#717=EDGE_CURVE('E672',#716,#191,#714,.T.);
#718=ORIENTED_EDGE('',*,*,#717,.F.);
#719=DIRECTION('',(0.5,-0.866025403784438,0.));
#720=VECTOR('',#719,1.);
#721=CARTESIAN_POINT('',(-50.1474798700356,-25.4124721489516,57.1185356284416));
#722=LINE('',#721,#720);
#723=EDGE_CURVE('E920',#716,#707,#722,.T.);
#724=ORIENTED_EDGE('',*,*,#723,.T.);
#725=EDGE_LOOP('',(#709,#710,#718,#724));
#726=FACE_BOUND('',#725,.T.);
#727=ADVANCED_FACE('F2468',(#726),#701,.T.);
#728=CARTESIAN_POINT('',(-40.161363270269,-30.6139868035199,51.0710622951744));
#729=DIRECTION('',(0.276604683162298,-0.912922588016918,0.300103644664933));
#730=DIRECTION('',(0.,-0.312287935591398,-0.949987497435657));
#731=AXIS2_PLACEMENT_3D('',#728,#729,#730);
#732=PLANE('',#731);
#733=DIRECTION('',(-0.585976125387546,-0.407742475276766,-0.700269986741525));
#734=VECTOR('',#733,1.);
#735=CARTESIAN_POINT('',(-24.2510808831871,-19.5430614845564,70.0846240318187));
#736=LINE('',#735,#734);
#737=CARTESIAN_POINT('',(-40.161363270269,-30.6139868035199,51.0710622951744));
#738=VERTEX_POINT('',#737);
#739=EDGE_CURVE('E909',#199,#738,#736,.T.);
#740=ORIENTED_EDGE('',*,*,#739,.F.);
#741=ORIENTED_EDGE('',*,*,#200,.T.);
#742=ORIENTED_EDGE('',*,*,#708,.T.);
#743=DIRECTION('',(0.752940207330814,0.0118343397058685,-0.657982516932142));
#744=VECTOR('',#743,1.);
#745=CARTESIAN_POINT('',(-47.0815863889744,-30.7227554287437,57.1185356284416));
#746=LINE('',#745,#744);
#747=EDGE_CURVE('E918',#707,#738,#746,.T.);
#748=ORIENTED_EDGE('',*,*,#747,.T.);
#749=EDGE_LOOP('',(#740,#741,#742,#748));
#750=FACE_BOUND('',#749,.T.);
#751=ADVANCED_FACE('F2476',(#750),#732,.T.);
#752=CARTESIAN_POINT('',(-50.1474798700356,-25.4124721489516,57.1185356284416));
#753=DIRECTION('',(-0.652311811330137,0.696007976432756,0.300103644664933));
#754=DIRECTION('',(-0.729639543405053,-0.683831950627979,0.));
#755=AXIS2_PLACEMENT_3D('',#752,#753,#754);
#756=PLANE('',#755);
#757=ORIENTED_EDGE('',*,*,#717,.T.);
#758=ORIENTED_EDGE('',*,*,#214,.T.);
#759=DIRECTION('',(0.6461034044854,0.303598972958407,0.700269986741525));
#760=VECTOR('',#759,1.);
#761=CARTESIAN_POINT('',(-46.5931719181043,-19.4737674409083,51.0710622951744));
#762=LINE('',#761,#760);
#763=CARTESIAN_POINT('',(-46.5931719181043,-19.4737674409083,51.0710622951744));
#764=VERTEX_POINT('',#763);
#765=EDGE_CURVE('E924',#764,#207,#762,.T.);
#766=ORIENTED_EDGE('',*,*,#765,.F.);
#767=DIRECTION('',(-0.386718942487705,-0.646148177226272,0.657982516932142));
#768=VECTOR('',#767,1.);
#769=CARTESIAN_POINT('',(-46.5931719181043,-19.4737674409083,51.0710622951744));
#770=LINE('',#769,#768);
#771=EDGE_CURVE('E912',#764,#716,#770,.T.);
#772=ORIENTED_EDGE('',*,*,#771,.T.);
#773=EDGE_LOOP('',(#757,#758,#766,#772));
#774=FACE_BOUND('',#773,.T.);
#775=ADVANCED_FACE('F2484',(#774),#756,.T.);
#776=CARTESIAN_POINT('',(-56.1352275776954,-3.06589348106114,57.1185356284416));
#777=DIRECTION('',(-0.664287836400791,0.,0.747476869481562));
#778=DIRECTION('',(0.747476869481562,0.,0.664287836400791));
#779=AXIS2_PLACEMENT_3D('',#776,#777,#778);
#780=PLANE('',#779);
#781=DIRECTION('',(-0.746877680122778,-0.0400323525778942,-0.663755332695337));
#782=VECTOR('',#781,1.);
#783=CARTESIAN_POINT('',(-35.8421193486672,-1.97819078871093,75.1531605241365));
#784=LINE('',#783,#782);
#785=CARTESIAN_POINT('',(-56.1352275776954,-3.06589348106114,57.1185356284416));
#786=VERTEX_POINT('',#785);
#787=EDGE_CURVE('E682',#149,#786,#784,.T.);
#788=ORIENTED_EDGE('',*,*,#787,.F.);
#789=ORIENTED_EDGE('',*,*,#152,.T.);
#790=DIRECTION('',(0.746877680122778,-0.0400323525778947,0.663755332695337));
#791=VECTOR('',#790,1.);
#792=CARTESIAN_POINT('',(-56.1352275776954,3.06589348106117,57.1185356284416));
#793=LINE('',#792,#791);
#794=CARTESIAN_POINT('',(-56.1352275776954,3.06589348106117,57.1185356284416));
#795=VERTEX_POINT('',#794);
#796=EDGE_CURVE('E686',#795,#151,#793,.T.);
#797=ORIENTED_EDGE('',*,*,#796,.F.);
#798=DIRECTION('',(0.,1.,0.));
#799=VECTOR('',#798,1.);
#800=CARTESIAN_POINT('',(-56.1352275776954,0.0109063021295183,57.1185356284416));
#801=LINE('',#800,#799);
#802=EDGE_CURVE('E953',#795,#786,#801,.F.);
#803=ORIENTED_EDGE('',*,*,#802,.T.);
#804=EDGE_LOOP('',(#788,#789,#797,#803));
#805=FACE_BOUND('',#804,.T.);
#806=ADVANCED_FACE('F2492',(#805),#780,.T.);
#807=CARTESIAN_POINT('',(-50.0877542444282,-6.43180864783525,51.0710622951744));
#808=DIRECTION('',(-0.216914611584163,-0.928916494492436,0.300103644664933));
#809=DIRECTION('',(0.,-0.307423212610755,-0.951572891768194));
#810=AXIS2_PLACEMENT_3D('',#807,#808,#809);
#811=PLANE('',#810);
#812=DIRECTION('',(-0.711341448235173,-0.0601272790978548,-0.700269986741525));
#813=VECTOR('',#812,1.);
#814=CARTESIAN_POINT('',(-30.7735828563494,-4.79924727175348,70.0846240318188));
#815=LINE('',#814,#813);
#816=CARTESIAN_POINT('',(-50.0877542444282,-6.43180864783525,51.0710622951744));
#817=VERTEX_POINT('',#816);
#818=EDGE_CURVE('E942',#159,#817,#815,.T.);
#819=ORIENTED_EDGE('',*,*,#818,.F.);
#820=ORIENTED_EDGE('',*,*,#160,.T.);
#821=ORIENTED_EDGE('',*,*,#787,.T.);
#822=DIRECTION('',(0.657982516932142,-0.366221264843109,-0.657982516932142));
#823=VECTOR('',#822,1.);
#824=CARTESIAN_POINT('',(-56.1352275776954,-3.06589348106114,57.1185356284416));
#825=LINE('',#824,#823);
#826=EDGE_CURVE('E951',#786,#817,#825,.T.);
#827=ORIENTED_EDGE('',*,*,#826,.T.);
#828=EDGE_LOOP('',(#819,#820,#821,#827));
#829=FACE_BOUND('',#828,.T.);
#830=ADVANCED_FACE('F2500',(#829),#811,.T.);
#831=CARTESIAN_POINT('',(-56.1352275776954,3.06589348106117,57.1185356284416));
#832=DIRECTION('',(-0.216914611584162,0.928916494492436,0.300103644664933));
#833=DIRECTION('',(0.,-0.307423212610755,0.951572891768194));
#834=AXIS2_PLACEMENT_3D('',#831,#832,#833);
#835=PLANE('',#834);
#836=ORIENTED_EDGE('',*,*,#796,.T.);
#837=ORIENTED_EDGE('',*,*,#174,.T.);
#838=DIRECTION('',(0.711341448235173,-0.0601272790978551,0.700269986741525));
#839=VECTOR('',#838,1.);
#840=CARTESIAN_POINT('',(-50.0877542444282,6.43180864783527,51.0710622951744));
#841=LINE('',#840,#839);
#842=CARTESIAN_POINT('',(-50.0877542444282,6.43180864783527,51.0710622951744));
#843=VERTEX_POINT('',#842);
#844=EDGE_CURVE('E957',#843,#167,#841,.T.);
#845=ORIENTED_EDGE('',*,*,#844,.F.);
#846=DIRECTION('',(-0.657982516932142,-0.366221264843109,0.657982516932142));
#847=VECTOR('',#846,1.);
#848=CARTESIAN_POINT('',(-50.0877542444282,6.43180864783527,51.0710622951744));
#849=LINE('',#848,#847);
#850=EDGE_CURVE('E945',#843,#795,#849,.T.);
#851=ORIENTED_EDGE('',*,*,#850,.T.);
#852=EDGE_LOOP('',(#836,#837,#845,#851));
#853=FACE_BOUND('',#852,.T.);
#854=ADVANCED_FACE('F2508',(#853),#835,.T.);
#855=CARTESIAN_POINT('',(-50.1474798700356,25.4124721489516,57.1185356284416));
#856=DIRECTION('',(-0.575290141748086,0.332143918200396,0.747476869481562));
#857=DIRECTION('',(0.792466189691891,0.,0.609915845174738));
#858=AXIS2_PLACEMENT_3D('',#855,#856,#857);
#859=PLANE('',#858);
#860=DIRECTION('',(-0.66683122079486,0.338769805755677,-0.663755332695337));
#861=VECTOR('',#860,1.);
#862=CARTESIAN_POINT('',(-32.029281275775,16.2078961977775,75.1531605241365));
#863=LINE('',#862,#861);
#864=CARTESIAN_POINT('',(-50.1474798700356,25.4124721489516,57.1185356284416));
#865=VERTEX_POINT('',#864);
#866=EDGE_CURVE('E696',#109,#865,#863,.T.);
#867=ORIENTED_EDGE('',*,*,#866,.F.);
#868=ORIENTED_EDGE('',*,*,#112,.T.);
#869=DIRECTION('',(0.626798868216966,-0.408107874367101,0.663755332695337));
#870=VECTOR('',#869,1.);
#871=CARTESIAN_POINT('',(-47.0815863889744,30.7227554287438,57.1185356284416));
#872=LINE('',#871,#870);
#873=CARTESIAN_POINT('',(-47.0815863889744,30.7227554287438,57.1185356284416));
#874=VERTEX_POINT('',#873);
#875=EDGE_CURVE('E700',#874,#111,#872,.T.);
#876=ORIENTED_EDGE('',*,*,#875,.F.);
#877=DIRECTION('',(-0.5,-0.866025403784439,0.));
#878=VECTOR('',#877,1.);
#879=CARTESIAN_POINT('',(-47.0815863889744,30.7227554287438,57.1185356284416));
#880=LINE('',#879,#878);
#881=EDGE_CURVE('E986',#874,#865,#880,.T.);
#882=ORIENTED_EDGE('',*,*,#881,.T.);
#883=EDGE_LOOP('',(#867,#868,#876,#882));
#884=FACE_BOUND('',#883,.T.);
#885=ADVANCED_FACE('F2516',(#884),#859,.T.);
#886=CARTESIAN_POINT('',(-46.5931719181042,19.4737674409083,51.0710622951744));
#887=DIRECTION('',(-0.652311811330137,-0.696007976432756,0.300103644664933));
#888=DIRECTION('',(0.729639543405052,-0.683831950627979,0.));
#889=AXIS2_PLACEMENT_3D('',#886,#887,#888);
#890=PLANE('',#889);
#891=DIRECTION('',(-0.6461034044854,0.303598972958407,-0.700269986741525));
#892=VECTOR('',#891,1.);
#893=CARTESIAN_POINT('',(-29.0503281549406,11.230521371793,70.0846240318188));
#894=LINE('',#893,#892);
#895=CARTESIAN_POINT('',(-46.5931719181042,19.4737674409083,51.0710622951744));
#896=VERTEX_POINT('',#895);
#897=EDGE_CURVE('E975',#119,#896,#894,.T.);
#898=ORIENTED_EDGE('',*,*,#897,.F.);
#899=ORIENTED_EDGE('',*,*,#120,.T.);
#900=ORIENTED_EDGE('',*,*,#866,.T.);
#901=DIRECTION('',(0.386718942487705,-0.646148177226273,-0.657982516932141));
#902=VECTOR('',#901,1.);
#903=CARTESIAN_POINT('',(-50.1474798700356,25.4124721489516,57.1185356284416));
#904=LINE('',#903,#902);
#905=EDGE_CURVE('E984',#865,#896,#904,.T.);
#906=ORIENTED_EDGE('',*,*,#905,.T.);
#907=EDGE_LOOP('',(#898,#899,#900,#906));
#908=FACE_BOUND('',#907,.T.);
#909=ADVANCED_FACE('F2524',(#908),#890,.T.);
#910=CARTESIAN_POINT('',(-47.0815863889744,30.7227554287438,57.1185356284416));
#911=DIRECTION('',(0.276604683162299,0.912922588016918,0.300103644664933));
#912=DIRECTION('',(0.,-0.312287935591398,0.949987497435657));
#913=AXIS2_PLACEMENT_3D('',#910,#911,#912);
#914=PLANE('',#913);
#915=ORIENTED_EDGE('',*,*,#875,.T.);
#916=ORIENTED_EDGE('',*,*,#134,.T.);
#917=DIRECTION('',(0.585976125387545,-0.407742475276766,0.700269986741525));
#918=VECTOR('',#917,1.);
#919=CARTESIAN_POINT('',(-40.161363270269,30.6139868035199,51.0710622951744));
#920=LINE('',#919,#918);
#921=CARTESIAN_POINT('',(-40.161363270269,30.6139868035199,51.0710622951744));
#922=VERTEX_POINT('',#921);
#923=EDGE_CURVE('E990',#922,#127,#920,.T.);
#924=ORIENTED_EDGE('',*,*,#923,.F.);
#925=DIRECTION('',(-0.752940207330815,0.0118343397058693,0.657982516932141));
#926=VECTOR('',#925,1.);
#927=CARTESIAN_POINT('',(-40.161363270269,30.6139868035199,51.0710622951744));
#928=LINE('',#927,#926);
#929=EDGE_CURVE('E978',#922,#874,#928,.T.);
#930=ORIENTED_EDGE('',*,*,#929,.T.);
#931=EDGE_LOOP('',(#915,#916,#924,#930));
#932=FACE_BOUND('',#931,.T.);
#933=ADVANCED_FACE('F2532',(#932),#914,.T.);
#934=CARTESIAN_POINT('',(-30.7227554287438,47.0815863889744,57.1185356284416));
#935=DIRECTION('',(-0.332143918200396,0.575290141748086,0.747476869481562));
#936=DIRECTION('',(0.,-0.792466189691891,0.609915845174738));
#937=AXIS2_PLACEMENT_3D('',#934,#935,#936);
#938=PLANE('',#937);
#939=DIRECTION('',(-0.408107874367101,0.626798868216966,-0.663755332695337));
#940=VECTOR('',#939,1.);
#941=CARTESIAN_POINT('',(-19.6342231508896,30.0510904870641,75.1531605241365));
#942=LINE('',#941,#940);
#943=CARTESIAN_POINT('',(-30.7227554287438,47.0815863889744,57.1185356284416));
#944=VERTEX_POINT('',#943);
#945=EDGE_CURVE('E710',#69,#944,#942,.T.);
#946=ORIENTED_EDGE('',*,*,#945,.F.);
#947=ORIENTED_EDGE('',*,*,#72,.T.);
#948=DIRECTION('',(0.338769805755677,-0.666831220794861,0.663755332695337));
#949=VECTOR('',#948,1.);
#950=CARTESIAN_POINT('',(-25.4124721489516,50.1474798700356,57.1185356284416));
#951=LINE('',#950,#949);
#952=CARTESIAN_POINT('',(-25.4124721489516,50.1474798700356,57.1185356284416));
#953=VERTEX_POINT('',#952);
#954=EDGE_CURVE('E714',#953,#71,#951,.T.);
#955=ORIENTED_EDGE('',*,*,#954,.F.);
#956=DIRECTION('',(-0.866025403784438,-0.500000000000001,0.));
#957=VECTOR('',#956,1.);
#958=CARTESIAN_POINT('',(-25.4124721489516,50.1474798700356,57.1185356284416));
#959=LINE('',#958,#957);
#960=EDGE_CURVE('E1019',#953,#944,#959,.T.);
#961=ORIENTED_EDGE('',*,*,#960,.T.);
#962=EDGE_LOOP('',(#946,#947,#955,#961));
#963=FACE_BOUND('',#962,.T.);
#964=ADVANCED_FACE('F2540',(#963),#938,.T.);
#965=CARTESIAN_POINT('',(-30.6139868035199,40.161363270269,51.0710622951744));
#966=DIRECTION('',(-0.912922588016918,-0.276604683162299,0.300103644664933));
#967=DIRECTION('',(0.312287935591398,0.,0.949987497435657));
#968=AXIS2_PLACEMENT_3D('',#965,#966,#967);
#969=PLANE('',#968);
#970=DIRECTION('',(-0.407742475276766,0.585976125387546,-0.700269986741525));
#971=VECTOR('',#970,1.);
#972=CARTESIAN_POINT('',(-19.5430614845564,24.2510808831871,70.0846240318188));
#973=LINE('',#972,#971);
#974=CARTESIAN_POINT('',(-30.6139868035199,40.161363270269,51.0710622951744));
#975=VERTEX_POINT('',#974);
#976=EDGE_CURVE('E1008',#79,#975,#973,.T.);
#977=ORIENTED_EDGE('',*,*,#976,.F.);
#978=ORIENTED_EDGE('',*,*,#80,.T.);
#979=ORIENTED_EDGE('',*,*,#945,.T.);
#980=DIRECTION('',(0.0118343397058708,-0.752940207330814,-0.657982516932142));
#981=VECTOR('',#980,1.);
#982=CARTESIAN_POINT('',(-30.7227554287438,47.0815863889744,57.1185356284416));
#983=LINE('',#982,#981);
#984=EDGE_CURVE('E1017',#944,#975,#983,.T.);
#985=ORIENTED_EDGE('',*,*,#984,.T.);
#986=EDGE_LOOP('',(#977,#978,#979,#985));
#987=FACE_BOUND('',#986,.T.);
#988=ADVANCED_FACE('F2548',(#987),#969,.T.);
#989=CARTESIAN_POINT('',(-25.4124721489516,50.1474798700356,57.1185356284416));
#990=DIRECTION('',(0.696007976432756,0.652311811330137,0.300103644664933));
#991=DIRECTION('',(-0.683831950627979,0.729639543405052,0.));
#992=AXIS2_PLACEMENT_3D('',#989,#990,#991);
#993=PLANE('',#992);
#994=ORIENTED_EDGE('',*,*,#954,.T.);
#995=ORIENTED_EDGE('',*,*,#94,.T.);
#996=DIRECTION('',(0.303598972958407,-0.6461034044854,0.700269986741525));
#997=VECTOR('',#996,1.);
#998=CARTESIAN_POINT('',(-19.4737674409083,46.5931719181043,51.0710622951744));
#999=LINE('',#998,#997);
#1000=CARTESIAN_POINT('',(-19.4737674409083,46.5931719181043,51.0710622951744));
#1001=VERTEX_POINT('',#1000);
#1002=EDGE_CURVE('E1023',#1001,#87,#999,.T.);
#1003=ORIENTED_EDGE('',*,*,#1002,.F.);
#1004=DIRECTION('',(-0.646148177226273,0.386718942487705,0.657982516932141));
#1005=VECTOR('',#1004,1.);
#1006=CARTESIAN_POINT('',(-19.4737674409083,46.5931719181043,51.0710622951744));
#1007=LINE('',#1006,#1005);
#1008=EDGE_CURVE('E1011',#1001,#953,#1007,.T.);
#1009=ORIENTED_EDGE('',*,*,#1008,.T.);
#1010=EDGE_LOOP('',(#994,#995,#1003,#1009));
#1011=FACE_BOUND('',#1010,.T.);
#1012=ADVANCED_FACE('F2556',(#1011),#993,.T.);
#1013=CARTESIAN_POINT('',(-3.06589348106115,56.1352275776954,57.1185356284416));
#1014=DIRECTION('',(0.,0.664287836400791,0.747476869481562));
#1015=DIRECTION('',(0.,-0.747476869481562,0.664287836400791));
#1016=AXIS2_PLACEMENT_3D('',#1013,#1014,#1015);
#1017=PLANE('',#1016);
#1018=DIRECTION('',(-0.0400323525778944,0.746877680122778,-0.663755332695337));
#1019=VECTOR('',#1018,1.);
#1020=CARTESIAN_POINT('',(-1.97819078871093,35.8421193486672,75.1531605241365));
#1021=LINE('',#1020,#1019);
#1022=CARTESIAN_POINT('',(-3.06589348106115,56.1352275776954,57.1185356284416));
#1023=VERTEX_POINT('',#1022);
#1024=EDGE_CURVE('E724',#509,#1023,#1021,.T.);
#1025=ORIENTED_EDGE('',*,*,#1024,.F.);
#1026=ORIENTED_EDGE('',*,*,#512,.T.);
#1027=DIRECTION('',(-0.0400323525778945,-0.746877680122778,0.663755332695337));
#1028=VECTOR('',#1027,1.);
#1029=CARTESIAN_POINT('',(3.06589348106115,56.1352275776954,57.1185356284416));
#1030=LINE('',#1029,#1028);
#1031=CARTESIAN_POINT('',(3.06589348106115,56.1352275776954,57.1185356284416));
#1032=VERTEX_POINT('',#1031);
#1033=EDGE_CURVE('E728',#1032,#511,#1030,.T.);
#1034=ORIENTED_EDGE('',*,*,#1033,.F.);
#1035=DIRECTION('',(1.,0.,0.));
#1036=VECTOR('',#1035,1.);
#1037=CARTESIAN_POINT('',(0.01090630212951,56.1352275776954,57.1185356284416));
#1038=LINE('',#1037,#1036);
#1039=EDGE_CURVE('E1052',#1032,#1023,#1038,.F.);
#1040=ORIENTED_EDGE('',*,*,#1039,.T.);
#1041=EDGE_LOOP('',(#1025,#1026,#1034,#1040));
#1042=FACE_BOUND('',#1041,.T.);
#1043=ADVANCED_FACE('F2564',(#1042),#1017,.T.);
#1044=CARTESIAN_POINT('',(-6.43180864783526,50.0877542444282,51.0710622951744));
#1045=DIRECTION('',(-0.928916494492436,0.216914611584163,0.300103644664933));
#1046=DIRECTION('',(0.307423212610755,0.,0.951572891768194));
#1047=AXIS2_PLACEMENT_3D('',#1044,#1045,#1046);
#1048=PLANE('',#1047);
#1049=DIRECTION('',(-0.0601272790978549,0.711341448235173,-0.700269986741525));
#1050=VECTOR('',#1049,1.);
#1051=CARTESIAN_POINT('',(-4.79924727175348,30.7735828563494,70.0846240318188));
#1052=LINE('',#1051,#1050);
#1053=CARTESIAN_POINT('',(-6.43180864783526,50.0877542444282,51.0710622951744));
#1054=VERTEX_POINT('',#1053);
#1055=EDGE_CURVE('E1041',#519,#1054,#1052,.T.);
#1056=ORIENTED_EDGE('',*,*,#1055,.F.);
#1057=ORIENTED_EDGE('',*,*,#520,.T.);
#1058=ORIENTED_EDGE('',*,*,#1024,.T.);
#1059=DIRECTION('',(-0.366221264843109,-0.657982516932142,-0.657982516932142));
#1060=VECTOR('',#1059,1.);
#1061=CARTESIAN_POINT('',(-3.06589348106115,56.1352275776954,57.1185356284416));
#1062=LINE('',#1061,#1060);
#1063=EDGE_CURVE('E1050',#1023,#1054,#1062,.T.);
#1064=ORIENTED_EDGE('',*,*,#1063,.T.);
#1065=EDGE_LOOP('',(#1056,#1057,#1058,#1064));
#1066=FACE_BOUND('',#1065,.T.);
#1067=ADVANCED_FACE('F2572',(#1066),#1048,.T.);
#1068=CARTESIAN_POINT('',(3.06589348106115,56.1352275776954,57.1185356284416));
#1069=DIRECTION('',(0.928916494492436,0.216914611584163,0.300103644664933));
#1070=DIRECTION('',(0.307423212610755,0.,-0.951572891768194));
#1071=AXIS2_PLACEMENT_3D('',#1068,#1069,#1070);
#1072=PLANE('',#1071);
#1073=ORIENTED_EDGE('',*,*,#1033,.T.);
#1074=ORIENTED_EDGE('',*,*,#534,.T.);
#1075=DIRECTION('',(-0.0601272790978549,-0.711341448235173,0.700269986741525));
#1076=VECTOR('',#1075,1.);
#1077=CARTESIAN_POINT('',(6.43180864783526,50.0877542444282,51.0710622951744));
#1078=LINE('',#1077,#1076);
#1079=CARTESIAN_POINT('',(6.43180864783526,50.0877542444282,51.0710622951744));
#1080=VERTEX_POINT('',#1079);
#1081=EDGE_CURVE('E1056',#1080,#527,#1078,.T.);
#1082=ORIENTED_EDGE('',*,*,#1081,.F.);
#1083=DIRECTION('',(-0.366221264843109,0.657982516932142,0.657982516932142));
#1084=VECTOR('',#1083,1.);
#1085=CARTESIAN_POINT('',(6.43180864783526,50.0877542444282,51.0710622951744));
#1086=LINE('',#1085,#1084);
#1087=EDGE_CURVE('E1044',#1080,#1032,#1086,.T.);
#1088=ORIENTED_EDGE('',*,*,#1087,.T.);
#1089=EDGE_LOOP('',(#1073,#1074,#1082,#1088));
#1090=FACE_BOUND('',#1089,.T.);
#1091=ADVANCED_FACE('F2580',(#1090),#1072,.T.);
#1092=CARTESIAN_POINT('',(25.4124721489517,50.1474798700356,57.1185356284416));
#1093=DIRECTION('',(0.332143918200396,0.575290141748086,0.747476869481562));
#1094=DIRECTION('',(0.,-0.792466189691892,0.609915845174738));
#1095=AXIS2_PLACEMENT_3D('',#1092,#1093,#1094);
#1096=PLANE('',#1095);
#1097=DIRECTION('',(0.338769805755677,0.66683122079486,-0.663755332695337));
#1098=VECTOR('',#1097,1.);
#1099=CARTESIAN_POINT('',(16.2078961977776,32.029281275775,75.1531605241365));
#1100=LINE('',#1099,#1098);
#1101=CARTESIAN_POINT('',(25.4124721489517,50.1474798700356,57.1185356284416));
#1102=VERTEX_POINT('',#1101);
#1103=EDGE_CURVE('E738',#469,#1102,#1100,.T.);
#1104=ORIENTED_EDGE('',*,*,#1103,.F.);
#1105=ORIENTED_EDGE('',*,*,#472,.T.);
#1106=DIRECTION('',(-0.408107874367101,-0.626798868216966,0.663755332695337));
#1107=VECTOR('',#1106,1.);
#1108=CARTESIAN_POINT('',(30.7227554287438,47.0815863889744,57.1185356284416));
#1109=LINE('',#1108,#1107);
#1110=CARTESIAN_POINT('',(30.7227554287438,47.0815863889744,57.1185356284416));
#1111=VERTEX_POINT('',#1110);
#1112=EDGE_CURVE('E742',#1111,#471,#1109,.T.);
#1113=ORIENTED_EDGE('',*,*,#1112,.F.);
#1114=DIRECTION('',(-0.866025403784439,0.5,0.));
#1115=VECTOR('',#1114,1.);
#1116=CARTESIAN_POINT('',(30.7227554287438,47.0815863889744,57.1185356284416));
#1117=LINE('',#1116,#1115);
#1118=EDGE_CURVE('E1085',#1111,#1102,#1117,.T.);
#1119=ORIENTED_EDGE('',*,*,#1118,.T.);
#1120=EDGE_LOOP('',(#1104,#1105,#1113,#1119));
#1121=FACE_BOUND('',#1120,.T.);
#1122=ADVANCED_FACE('F2588',(#1121),#1096,.T.);
#1123=CARTESIAN_POINT('',(19.4737674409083,46.5931719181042,51.0710622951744));
#1124=DIRECTION('',(-0.696007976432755,0.652311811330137,0.300103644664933));
#1125=DIRECTION('',(-0.68383195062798,-0.729639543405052,0.));
#1126=AXIS2_PLACEMENT_3D('',#1123,#1124,#1125);
#1127=PLANE('',#1126);
#1128=DIRECTION('',(0.303598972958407,0.6461034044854,-0.700269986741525));
#1129=VECTOR('',#1128,1.);
#1130=CARTESIAN_POINT('',(11.230521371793,29.0503281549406,70.0846240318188));
#1131=LINE('',#1130,#1129);
#1132=CARTESIAN_POINT('',(19.4737674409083,46.5931719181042,51.0710622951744));
#1133=VERTEX_POINT('',#1132);
#1134=EDGE_CURVE('E1074',#479,#1133,#1131,.T.);
#1135=ORIENTED_EDGE('',*,*,#1134,.F.);
#1136=ORIENTED_EDGE('',*,*,#480,.T.);
#1137=ORIENTED_EDGE('',*,*,#1103,.T.);
#1138=DIRECTION('',(-0.646148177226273,-0.386718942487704,-0.657982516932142));
#1139=VECTOR('',#1138,1.);
#1140=CARTESIAN_POINT('',(25.4124721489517,50.1474798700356,57.1185356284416));
#1141=LINE('',#1140,#1139);
#1142=EDGE_CURVE('E1083',#1102,#1133,#1141,.T.);
#1143=ORIENTED_EDGE('',*,*,#1142,.T.);
#1144=EDGE_LOOP('',(#1135,#1136,#1137,#1143));
#1145=FACE_BOUND('',#1144,.T.);
#1146=ADVANCED_FACE('F2596',(#1145),#1127,.T.);
#1147=CARTESIAN_POINT('',(30.7227554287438,47.0815863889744,57.1185356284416));
#1148=DIRECTION('',(0.912922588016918,-0.276604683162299,0.300103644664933));
#1149=DIRECTION('',(0.312287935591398,0.,-0.949987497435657));
#1150=AXIS2_PLACEMENT_3D('',#1147,#1148,#1149);
#1151=PLANE('',#1150);
#1152=ORIENTED_EDGE('',*,*,#1112,.T.);
#1153=ORIENTED_EDGE('',*,*,#494,.T.);
#1154=DIRECTION('',(-0.407742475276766,-0.585976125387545,0.700269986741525));
#1155=VECTOR('',#1154,1.);
#1156=CARTESIAN_POINT('',(30.6139868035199,40.161363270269,51.0710622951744));
#1157=LINE('',#1156,#1155);
#1158=CARTESIAN_POINT('',(30.6139868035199,40.161363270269,51.0710622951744));
#1159=VERTEX_POINT('',#1158);
#1160=EDGE_CURVE('E1089',#1159,#487,#1157,.T.);
#1161=ORIENTED_EDGE('',*,*,#1160,.F.);
#1162=DIRECTION('',(0.01183433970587,0.752940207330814,0.657982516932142));
#1163=VECTOR('',#1162,1.);
#1164=CARTESIAN_POINT('',(30.6139868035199,40.161363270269,51.0710622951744));
#1165=LINE('',#1164,#1163);
#1166=EDGE_CURVE('E1077',#1159,#1111,#1165,.T.);
#1167=ORIENTED_EDGE('',*,*,#1166,.T.);
#1168=EDGE_LOOP('',(#1152,#1153,#1161,#1167));
#1169=FACE_BOUND('',#1168,.T.);
#1170=ADVANCED_FACE('F2604',(#1169),#1151,.T.);
#1171=CARTESIAN_POINT('',(47.0815863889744,30.7227554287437,57.1185356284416));
#1172=DIRECTION('',(0.575290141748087,0.332143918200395,0.747476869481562));
#1173=DIRECTION('',(0.792466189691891,0.,-0.609915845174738));
#1174=AXIS2_PLACEMENT_3D('',#1171,#1172,#1173);
#1175=PLANE('',#1174);
#1176=DIRECTION('',(0.626798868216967,0.4081078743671,-0.663755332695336));
#1177=VECTOR('',#1176,1.);
#1178=CARTESIAN_POINT('',(30.0510904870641,19.6342231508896,75.1531605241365));
#1179=LINE('',#1178,#1177);
#1180=CARTESIAN_POINT('',(47.0815863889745,30.7227554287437,57.1185356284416));
#1181=VERTEX_POINT('',#1180);
#1182=EDGE_CURVE('E752',#429,#1181,#1179,.T.);
#1183=ORIENTED_EDGE('',*,*,#1182,.F.);
#1184=ORIENTED_EDGE('',*,*,#432,.T.);
#1185=DIRECTION('',(-0.666831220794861,-0.338769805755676,0.663755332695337));
#1186=VECTOR('',#1185,1.);
#1187=CARTESIAN_POINT('',(50.1474798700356,25.4124721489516,57.1185356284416));
#1188=LINE('',#1187,#1186);
#1189=CARTESIAN_POINT('',(50.1474798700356,25.4124721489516,57.1185356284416));
#1190=VERTEX_POINT('',#1189);
#1191=EDGE_CURVE('E756',#1190,#431,#1188,.T.);
#1192=ORIENTED_EDGE('',*,*,#1191,.F.);
#1193=DIRECTION('',(-0.499999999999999,0.866025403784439,0.));
#1194=VECTOR('',#1193,1.);
#1195=CARTESIAN_POINT('',(50.1474798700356,25.4124721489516,57.1185356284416));
#1196=LINE('',#1195,#1194);
#1197=EDGE_CURVE('E1118',#1190,#1181,#1196,.T.);
#1198=ORIENTED_EDGE('',*,*,#1197,.T.);
#1199=EDGE_LOOP('',(#1183,#1184,#1192,#1198));
#1200=FACE_BOUND('',#1199,.T.);
#1201=ADVANCED_FACE('F2612',(#1200),#1175,.T.);
#1202=CARTESIAN_POINT('',(40.161363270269,30.6139868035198,51.0710622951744));
#1203=DIRECTION('',(-0.276604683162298,0.912922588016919,0.300103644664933));
#1204=DIRECTION('',(0.,-0.312287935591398,0.949987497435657));
#1205=AXIS2_PLACEMENT_3D('',#1202,#1203,#1204);
#1206=PLANE('',#1205);
#1207=DIRECTION('',(0.585976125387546,0.407742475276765,-0.700269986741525));
#1208=VECTOR('',#1207,1.);
#1209=CARTESIAN_POINT('',(24.2510808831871,19.5430614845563,70.0846240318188));
#1210=LINE('',#1209,#1208);
#1211=CARTESIAN_POINT('',(40.161363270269,30.6139868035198,51.0710622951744));
#1212=VERTEX_POINT('',#1211);
#1213=EDGE_CURVE('E1107',#439,#1212,#1210,.T.);
#1214=ORIENTED_EDGE('',*,*,#1213,.F.);
#1215=ORIENTED_EDGE('',*,*,#440,.T.);
#1216=ORIENTED_EDGE('',*,*,#1182,.T.);
#1217=DIRECTION('',(-0.752940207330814,-0.0118343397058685,-0.657982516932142));
#1218=VECTOR('',#1217,1.);
#1219=CARTESIAN_POINT('',(47.0815863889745,30.7227554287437,57.1185356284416));
#1220=LINE('',#1219,#1218);
#1221=EDGE_CURVE('E1116',#1181,#1212,#1220,.T.);
#1222=ORIENTED_EDGE('',*,*,#1221,.T.);
#1223=EDGE_LOOP('',(#1214,#1215,#1216,#1222));
#1224=FACE_BOUND('',#1223,.T.);
#1225=ADVANCED_FACE('F2620',(#1224),#1206,.T.);
#1226=CARTESIAN_POINT('',(50.1474798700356,25.4124721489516,57.1185356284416));
#1227=DIRECTION('',(0.652311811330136,-0.696007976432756,0.300103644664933));
#1228=DIRECTION('',(0.729639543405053,0.683831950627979,0.));
#1229=AXIS2_PLACEMENT_3D('',#1226,#1227,#1228);
#1230=PLANE('',#1229);
#1231=ORIENTED_EDGE('',*,*,#1191,.T.);
#1232=ORIENTED_EDGE('',*,*,#454,.T.);
#1233=DIRECTION('',(-0.646103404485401,-0.303598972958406,0.700269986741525));
#1234=VECTOR('',#1233,1.);
#1235=CARTESIAN_POINT('',(46.5931719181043,19.4737674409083,51.0710622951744));
#1236=LINE('',#1235,#1234);
#1237=CARTESIAN_POINT('',(46.5931719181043,19.4737674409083,51.0710622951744));
#1238=VERTEX_POINT('',#1237);
#1239=EDGE_CURVE('E1122',#1238,#447,#1236,.T.);
#1240=ORIENTED_EDGE('',*,*,#1239,.F.);
#1241=DIRECTION('',(0.386718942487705,0.646148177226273,0.657982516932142));
#1242=VECTOR('',#1241,1.);
#1243=CARTESIAN_POINT('',(46.5931719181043,19.4737674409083,51.0710622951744));
#1244=LINE('',#1243,#1242);
#1245=EDGE_CURVE('E1110',#1238,#1190,#1244,.T.);
#1246=ORIENTED_EDGE('',*,*,#1245,.T.);
#1247=EDGE_LOOP('',(#1231,#1232,#1240,#1246));
#1248=FACE_BOUND('',#1247,.T.);
#1249=ADVANCED_FACE('F2628',(#1248),#1230,.T.);
#1250=CARTESIAN_POINT('',(56.1352275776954,3.06589348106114,57.1185356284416));
#1251=DIRECTION('',(0.664287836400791,0.,0.747476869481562));
#1252=DIRECTION('',(0.747476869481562,0.,-0.664287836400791));
#1253=AXIS2_PLACEMENT_3D('',#1250,#1251,#1252);
#1254=PLANE('',#1253);
#1255=DIRECTION('',(0.746877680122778,0.0400323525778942,-0.663755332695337));
#1256=VECTOR('',#1255,1.);
#1257=CARTESIAN_POINT('',(35.8421193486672,1.97819078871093,75.1531605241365));
#1258=LINE('',#1257,#1256);
#1259=CARTESIAN_POINT('',(56.1352275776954,3.06589348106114,57.1185356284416));
#1260=VERTEX_POINT('',#1259);
#1261=EDGE_CURVE('E766',#389,#1260,#1258,.T.);
#1262=ORIENTED_EDGE('',*,*,#1261,.F.);
#1263=ORIENTED_EDGE('',*,*,#392,.T.);
#1264=DIRECTION('',(-0.746877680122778,0.0400323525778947,0.663755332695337));
#1265=VECTOR('',#1264,1.);
#1266=CARTESIAN_POINT('',(56.1352275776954,-3.06589348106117,57.1185356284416));
#1267=LINE('',#1266,#1265);
#1268=CARTESIAN_POINT('',(56.1352275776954,-3.06589348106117,57.1185356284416));
#1269=VERTEX_POINT('',#1268);
#1270=EDGE_CURVE('E770',#1269,#391,#1267,.T.);
#1271=ORIENTED_EDGE('',*,*,#1270,.F.);
#1272=DIRECTION('',(0.,1.,0.));
#1273=VECTOR('',#1272,1.);
#1274=CARTESIAN_POINT('',(56.1352275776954,-0.0109063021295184,57.1185356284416));
#1275=LINE('',#1274,#1273);
#1276=EDGE_CURVE('E1151',#1269,#1260,#1275,.T.);
#1277=ORIENTED_EDGE('',*,*,#1276,.T.);
#1278=EDGE_LOOP('',(#1262,#1263,#1271,#1277));
#1279=FACE_BOUND('',#1278,.T.);
#1280=ADVANCED_FACE('F2636',(#1279),#1254,.T.);
#1281=CARTESIAN_POINT('',(50.0877542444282,6.43180864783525,51.0710622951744));
#1282=DIRECTION('',(0.216914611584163,0.928916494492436,0.300103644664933));
#1283=DIRECTION('',(0.,-0.307423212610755,0.951572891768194));
#1284=AXIS2_PLACEMENT_3D('',#1281,#1282,#1283);
#1285=PLANE('',#1284);
#1286=DIRECTION('',(0.711341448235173,0.0601272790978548,-0.700269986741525));
#1287=VECTOR('',#1286,1.);
#1288=CARTESIAN_POINT('',(30.7735828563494,4.79924727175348,70.0846240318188));
#1289=LINE('',#1288,#1287);
#1290=CARTESIAN_POINT('',(50.0877542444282,6.43180864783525,51.0710622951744));
#1291=VERTEX_POINT('',#1290);
#1292=EDGE_CURVE('E1140',#399,#1291,#1289,.T.);
#1293=ORIENTED_EDGE('',*,*,#1292,.F.);
#1294=ORIENTED_EDGE('',*,*,#400,.T.);
#1295=ORIENTED_EDGE('',*,*,#1261,.T.);
#1296=DIRECTION('',(-0.657982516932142,0.366221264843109,-0.657982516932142));
#1297=VECTOR('',#1296,1.);
#1298=CARTESIAN_POINT('',(56.1352275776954,3.06589348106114,57.1185356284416));
#1299=LINE('',#1298,#1297);
#1300=EDGE_CURVE('E1149',#1260,#1291,#1299,.T.);
#1301=ORIENTED_EDGE('',*,*,#1300,.T.);
#1302=EDGE_LOOP('',(#1293,#1294,#1295,#1301));
#1303=FACE_BOUND('',#1302,.T.);
#1304=ADVANCED_FACE('F2644',(#1303),#1285,.T.);
#1305=CARTESIAN_POINT('',(56.1352275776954,-3.06589348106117,57.1185356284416));
#1306=DIRECTION('',(0.216914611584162,-0.928916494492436,0.300103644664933));
#1307=DIRECTION('',(0.,-0.307423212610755,-0.951572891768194));
#1308=AXIS2_PLACEMENT_3D('',#1305,#1306,#1307);
#1309=PLANE('',#1308);
#1310=ORIENTED_EDGE('',*,*,#1270,.T.);
#1311=ORIENTED_EDGE('',*,*,#414,.T.);
#1312=DIRECTION('',(-0.711341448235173,0.0601272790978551,0.700269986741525));
#1313=VECTOR('',#1312,1.);
#1314=CARTESIAN_POINT('',(50.0877542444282,-6.43180864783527,51.0710622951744));
#1315=LINE('',#1314,#1313);
#1316=CARTESIAN_POINT('',(50.0877542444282,-6.43180864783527,51.0710622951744));
#1317=VERTEX_POINT('',#1316);
#1318=EDGE_CURVE('E1155',#1317,#407,#1315,.T.);
#1319=ORIENTED_EDGE('',*,*,#1318,.F.);
#1320=DIRECTION('',(0.657982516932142,0.366221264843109,0.657982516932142));
#1321=VECTOR('',#1320,1.);
#1322=CARTESIAN_POINT('',(50.0877542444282,-6.43180864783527,51.0710622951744));
#1323=LINE('',#1322,#1321);
#1324=EDGE_CURVE('E1143',#1317,#1269,#1323,.T.);
#1325=ORIENTED_EDGE('',*,*,#1324,.T.);
#1326=EDGE_LOOP('',(#1310,#1311,#1319,#1325));
#1327=FACE_BOUND('',#1326,.T.);
#1328=ADVANCED_FACE('F1999',(#1327),#1309,.T.);
#1329=CARTESIAN_POINT('',(50.1474798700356,-25.4124721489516,57.1185356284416));
#1330=DIRECTION('',(0.575290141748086,-0.332143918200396,0.747476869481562));
#1331=DIRECTION('',(0.792466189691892,0.,-0.609915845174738));
#1332=AXIS2_PLACEMENT_3D('',#1329,#1330,#1331);
#1333=PLANE('',#1332);
#1334=DIRECTION('',(0.66683122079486,-0.338769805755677,-0.663755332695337));
#1335=VECTOR('',#1334,1.);
#1336=CARTESIAN_POINT('',(32.029281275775,-16.2078961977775,75.1531605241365));
#1337=LINE('',#1336,#1335);
#1338=CARTESIAN_POINT('',(50.1474798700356,-25.4124721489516,57.1185356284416));
#1339=VERTEX_POINT('',#1338);
#1340=EDGE_CURVE('E780',#349,#1339,#1337,.T.);
#1341=ORIENTED_EDGE('',*,*,#1340,.F.);
#1342=ORIENTED_EDGE('',*,*,#352,.T.);
#1343=DIRECTION('',(-0.626798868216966,0.408107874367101,0.663755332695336));
#1344=VECTOR('',#1343,1.);
#1345=CARTESIAN_POINT('',(47.0815863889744,-30.7227554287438,57.1185356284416));
#1346=LINE('',#1345,#1344);
#1347=CARTESIAN_POINT('',(47.0815863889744,-30.7227554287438,57.1185356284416));
#1348=VERTEX_POINT('',#1347);
#1349=EDGE_CURVE('E784',#1348,#351,#1346,.T.);
#1350=ORIENTED_EDGE('',*,*,#1349,.F.);
#1351=DIRECTION('',(0.5,0.866025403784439,0.));
#1352=VECTOR('',#1351,1.);
#1353=CARTESIAN_POINT('',(47.0815863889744,-30.7227554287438,57.1185356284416));
#1354=LINE('',#1353,#1352);
#1355=EDGE_CURVE('E1184',#1348,#1339,#1354,.T.);
#1356=ORIENTED_EDGE('',*,*,#1355,.T.);
#1357=EDGE_LOOP('',(#1341,#1342,#1350,#1356));
#1358=FACE_BOUND('',#1357,.T.);
#1359=ADVANCED_FACE('F1988',(#1358),#1333,.T.);
#1360=CARTESIAN_POINT('',(46.5931719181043,-19.4737674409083,51.0710622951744));
#1361=DIRECTION('',(0.652311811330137,0.696007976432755,0.300103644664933));
#1362=DIRECTION('',(-0.729639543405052,0.683831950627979,0.));
#1363=AXIS2_PLACEMENT_3D('',#1360,#1361,#1362);
#1364=PLANE('',#1363);
#1365=DIRECTION('',(0.6461034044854,-0.303598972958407,-0.700269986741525));
#1366=VECTOR('',#1365,1.);
#1367=CARTESIAN_POINT('',(29.0503281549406,-11.230521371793,70.0846240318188));
#1368=LINE('',#1367,#1366);
#1369=CARTESIAN_POINT('',(46.5931719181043,-19.4737674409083,51.0710622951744));
#1370=VERTEX_POINT('',#1369);
#1371=EDGE_CURVE('E1173',#359,#1370,#1368,.T.);
#1372=ORIENTED_EDGE('',*,*,#1371,.F.);
#1373=ORIENTED_EDGE('',*,*,#360,.T.);
#1374=ORIENTED_EDGE('',*,*,#1340,.T.);
#1375=DIRECTION('',(-0.386718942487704,0.646148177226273,-0.657982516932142));
#1376=VECTOR('',#1375,1.);
#1377=CARTESIAN_POINT('',(50.1474798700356,-25.4124721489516,57.1185356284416));
#1378=LINE('',#1377,#1376);
#1379=EDGE_CURVE('E1182',#1339,#1370,#1378,.T.);
#1380=ORIENTED_EDGE('',*,*,#1379,.T.);
#1381=EDGE_LOOP('',(#1372,#1373,#1374,#1380));
#1382=FACE_BOUND('',#1381,.T.);
#1383=ADVANCED_FACE('F1990',(#1382),#1364,.T.);
#1384=CARTESIAN_POINT('',(47.0815863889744,-30.7227554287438,57.1185356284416));
#1385=DIRECTION('',(-0.276604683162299,-0.912922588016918,0.300103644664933));
#1386=DIRECTION('',(0.,-0.312287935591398,-0.949987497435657));
#1387=AXIS2_PLACEMENT_3D('',#1384,#1385,#1386);
#1388=PLANE('',#1387);
#1389=ORIENTED_EDGE('',*,*,#1349,.T.);
#1390=ORIENTED_EDGE('',*,*,#374,.T.);
#1391=DIRECTION('',(-0.585976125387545,0.407742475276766,0.700269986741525));
#1392=VECTOR('',#1391,1.);
#1393=CARTESIAN_POINT('',(40.161363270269,-30.6139868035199,51.0710622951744));
#1394=LINE('',#1393,#1392);
#1395=CARTESIAN_POINT('',(40.161363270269,-30.6139868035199,51.0710622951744));
#1396=VERTEX_POINT('',#1395);
#1397=EDGE_CURVE('E1188',#1396,#367,#1394,.T.);
#1398=ORIENTED_EDGE('',*,*,#1397,.F.);
#1399=DIRECTION('',(0.752940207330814,-0.01183433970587,0.657982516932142));
#1400=VECTOR('',#1399,1.);
#1401=CARTESIAN_POINT('',(40.161363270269,-30.6139868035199,51.0710622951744));
#1402=LINE('',#1401,#1400);
#1403=EDGE_CURVE('E1176',#1396,#1348,#1402,.T.);
#1404=ORIENTED_EDGE('',*,*,#1403,.T.);
#1405=EDGE_LOOP('',(#1389,#1390,#1398,#1404));
#1406=FACE_BOUND('',#1405,.T.);
#1407=ADVANCED_FACE('F1985',(#1406),#1388,.T.);
#1408=CARTESIAN_POINT('',(30.7227554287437,-47.0815863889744,57.1185356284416));
#1409=DIRECTION('',(0.332143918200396,-0.575290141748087,0.747476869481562));
#1410=DIRECTION('',(0.,-0.792466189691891,-0.609915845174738));
#1411=AXIS2_PLACEMENT_3D('',#1408,#1409,#1410);
#1412=PLANE('',#1411);
#1413=DIRECTION('',(0.408107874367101,-0.626798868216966,-0.663755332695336));
#1414=VECTOR('',#1413,1.);
#1415=CARTESIAN_POINT('',(19.6342231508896,-30.0510904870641,75.1531605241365));
#1416=LINE('',#1415,#1414);
#1417=CARTESIAN_POINT('',(30.7227554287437,-47.0815863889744,57.1185356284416));
#1418=VERTEX_POINT('',#1417);
#1419=EDGE_CURVE('E794',#309,#1418,#1416,.T.);
#1420=ORIENTED_EDGE('',*,*,#1419,.F.);
#1421=ORIENTED_EDGE('',*,*,#312,.T.);
#1422=DIRECTION('',(-0.338769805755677,0.666831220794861,0.663755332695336));
#1423=VECTOR('',#1422,1.);
#1424=CARTESIAN_POINT('',(25.4124721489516,-50.1474798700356,57.1185356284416));
#1425=LINE('',#1424,#1423);
#1426=CARTESIAN_POINT('',(25.4124721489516,-50.1474798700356,57.1185356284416));
#1427=VERTEX_POINT('',#1426);
#1428=EDGE_CURVE('E798',#1427,#311,#1425,.T.);
#1429=ORIENTED_EDGE('',*,*,#1428,.F.);
#1430=DIRECTION('',(0.866025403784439,0.499999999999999,0.));
#1431=VECTOR('',#1430,1.);
#1432=CARTESIAN_POINT('',(25.4124721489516,-50.1474798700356,57.1185356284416));
#1433=LINE('',#1432,#1431);
#1434=EDGE_CURVE('E1217',#1427,#1418,#1433,.T.);
#1435=ORIENTED_EDGE('',*,*,#1434,.T.);
#1436=EDGE_LOOP('',(#1420,#1421,#1429,#1435));
#1437=FACE_BOUND('',#1436,.T.);
#1438=ADVANCED_FACE('F1997',(#1437),#1412,.T.);
#1439=CARTESIAN_POINT('',(30.6139868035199,-40.161363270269,51.0710622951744));
#1440=DIRECTION('',(0.912922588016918,0.276604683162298,0.300103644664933));
#1441=DIRECTION('',(0.312287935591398,0.,-0.949987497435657));
#1442=AXIS2_PLACEMENT_3D('',#1439,#1440,#1441);
#1443=PLANE('',#1442);
#1444=DIRECTION('',(0.407742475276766,-0.585976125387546,-0.700269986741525));
#1445=VECTOR('',#1444,1.);
#1446=CARTESIAN_POINT('',(19.5430614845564,-24.2510808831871,70.0846240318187));
#1447=LINE('',#1446,#1445);
#1448=CARTESIAN_POINT('',(30.6139868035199,-40.161363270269,51.0710622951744));
#1449=VERTEX_POINT('',#1448);
#1450=EDGE_CURVE('E1206',#319,#1449,#1447,.T.);
#1451=ORIENTED_EDGE('',*,*,#1450,.F.);
#1452=ORIENTED_EDGE('',*,*,#320,.T.);
#1453=ORIENTED_EDGE('',*,*,#1419,.T.);
#1454=DIRECTION('',(-0.0118343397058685,0.752940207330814,-0.657982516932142));
#1455=VECTOR('',#1454,1.);
#1456=CARTESIAN_POINT('',(30.7227554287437,-47.0815863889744,57.1185356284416));
#1457=LINE('',#1456,#1455);
#1458=EDGE_CURVE('E1215',#1418,#1449,#1457,.T.);
#1459=ORIENTED_EDGE('',*,*,#1458,.T.);
#1460=EDGE_LOOP('',(#1451,#1452,#1453,#1459));
#1461=FACE_BOUND('',#1460,.T.);
#1462=ADVANCED_FACE('F2005',(#1461),#1443,.T.);
#1463=CARTESIAN_POINT('',(25.4124721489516,-50.1474798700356,57.1185356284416));
#1464=DIRECTION('',(-0.696007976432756,-0.652311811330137,0.300103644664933));
#1465=DIRECTION('',(0.683831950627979,-0.729639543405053,0.));
#1466=AXIS2_PLACEMENT_3D('',#1463,#1464,#1465);
#1467=PLANE('',#1466);
#1468=ORIENTED_EDGE('',*,*,#1428,.T.);
#1469=ORIENTED_EDGE('',*,*,#334,.T.);
#1470=DIRECTION('',(-0.303598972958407,0.6461034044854,0.700269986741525));
#1471=VECTOR('',#1470,1.);
#1472=CARTESIAN_POINT('',(19.4737674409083,-46.5931719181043,51.0710622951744));
#1473=LINE('',#1472,#1471);
#1474=CARTESIAN_POINT('',(19.4737674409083,-46.5931719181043,51.0710622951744));
#1475=VERTEX_POINT('',#1474);
#1476=EDGE_CURVE('E1221',#1475,#327,#1473,.T.);
#1477=ORIENTED_EDGE('',*,*,#1476,.F.);
#1478=DIRECTION('',(0.646148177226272,-0.386718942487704,0.657982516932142));
#1479=VECTOR('',#1478,1.);
#1480=CARTESIAN_POINT('',(19.4737674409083,-46.5931719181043,51.0710622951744));
#1481=LINE('',#1480,#1479);
#1482=EDGE_CURVE('E1209',#1475,#1427,#1481,.T.);
#1483=ORIENTED_EDGE('',*,*,#1482,.T.);
#1484=EDGE_LOOP('',(#1468,#1469,#1477,#1483));
#1485=FACE_BOUND('',#1484,.T.);
#1486=ADVANCED_FACE('F1976',(#1485),#1467,.T.);
#1487=CARTESIAN_POINT('',(0.,0.,70.0846240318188));
#1488=DIRECTION('',(0.,0.,1.));
#1489=DIRECTION('',(0.,-1.,0.));
#1490=AXIS2_PLACEMENT_3D('',#1487,#1488,#1489);
#1491=PLANE('',#1490);
#1492=DIRECTION('',(-0.965925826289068,0.258819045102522,0.));
#1493=VECTOR('',#1492,1.);
#1494=CARTESIAN_POINT('',(11.230521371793,29.0503281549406,70.0846240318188));
#1495=LINE('',#1494,#1493);
#1496=EDGE_CURVE('E1065',#527,#479,#1495,.F.);
#1497=ORIENTED_EDGE('',*,*,#1496,.F.);
#1498=ORIENTED_EDGE('',*,*,#528,.T.);
#1499=DIRECTION('',(-0.965925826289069,-0.25881904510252,0.));
#1500=VECTOR('',#1499,1.);
#1501=CARTESIAN_POINT('',(-4.79924727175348,30.7735828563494,70.0846240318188));
#1502=LINE('',#1501,#1500);
#1503=EDGE_CURVE('E1032',#87,#519,#1502,.F.);
#1504=ORIENTED_EDGE('',*,*,#1503,.F.);
#1505=ORIENTED_EDGE('',*,*,#88,.T.);
#1506=DIRECTION('',(-0.707106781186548,-0.707106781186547,0.));
#1507=VECTOR('',#1506,1.);
#1508=CARTESIAN_POINT('',(-19.5430614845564,24.2510808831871,70.0846240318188));
#1509=LINE('',#1508,#1507);
#1510=EDGE_CURVE('E999',#127,#79,#1509,.F.);
#1511=ORIENTED_EDGE('',*,*,#1510,.F.);
#1512=ORIENTED_EDGE('',*,*,#128,.T.);
#1513=DIRECTION('',(-0.258819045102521,-0.965925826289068,0.));
#1514=VECTOR('',#1513,1.);
#1515=CARTESIAN_POINT('',(-29.0503281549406,11.230521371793,70.0846240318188));
#1516=LINE('',#1515,#1514);
#1517=EDGE_CURVE('E966',#167,#119,#1516,.F.);
#1518=ORIENTED_EDGE('',*,*,#1517,.F.);
#1519=ORIENTED_EDGE('',*,*,#168,.T.);
#1520=DIRECTION('',(0.25881904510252,-0.965925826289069,0.));
#1521=VECTOR('',#1520,1.);
#1522=CARTESIAN_POINT('',(-30.7735828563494,-4.79924727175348,70.0846240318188));
#1523=LINE('',#1522,#1521);
#1524=EDGE_CURVE('E933',#207,#159,#1523,.F.);
#1525=ORIENTED_EDGE('',*,*,#1524,.F.);
#1526=ORIENTED_EDGE('',*,*,#208,.T.);
#1527=DIRECTION('',(0.707106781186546,-0.707106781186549,0.));
#1528=VECTOR('',#1527,1.);
#1529=CARTESIAN_POINT('',(-24.2510808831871,-19.5430614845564,70.0846240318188));
#1530=LINE('',#1529,#1528);
#1531=EDGE_CURVE('E900',#247,#199,#1530,.F.);
#1532=ORIENTED_EDGE('',*,*,#1531,.F.);
#1533=ORIENTED_EDGE('',*,*,#248,.T.);
#1534=DIRECTION('',(0.965925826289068,-0.258819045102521,0.));
#1535=VECTOR('',#1534,1.);
#1536=CARTESIAN_POINT('',(-11.230521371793,-29.0503281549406,70.0846240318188));
#1537=LINE('',#1536,#1535);
#1538=EDGE_CURVE('E867',#287,#239,#1537,.F.);
#1539=ORIENTED_EDGE('',*,*,#1538,.F.);
#1540=ORIENTED_EDGE('',*,*,#288,.T.);
#1541=DIRECTION('',(0.965925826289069,0.25881904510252,0.));
#1542=VECTOR('',#1541,1.);
#1543=CARTESIAN_POINT('',(4.79924727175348,-30.7735828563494,70.0846240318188));
#1544=LINE('',#1543,#1542);
#1545=EDGE_CURVE('E1234',#327,#279,#1544,.F.);
#1546=ORIENTED_EDGE('',*,*,#1545,.F.);
#1547=ORIENTED_EDGE('',*,*,#328,.T.);
#1548=DIRECTION('',(0.707106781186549,0.707106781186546,0.));
#1549=VECTOR('',#1548,1.);
#1550=CARTESIAN_POINT('',(19.5430614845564,-24.2510808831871,70.0846240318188));
#1551=LINE('',#1550,#1549);
#1552=EDGE_CURVE('E1197',#367,#319,#1551,.F.);
#1553=ORIENTED_EDGE('',*,*,#1552,.F.);
#1554=ORIENTED_EDGE('',*,*,#368,.T.);
#1555=DIRECTION('',(0.258819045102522,0.965925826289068,0.));
#1556=VECTOR('',#1555,1.);
#1557=CARTESIAN_POINT('',(29.0503281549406,-11.230521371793,70.0846240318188));
#1558=LINE('',#1557,#1556);
#1559=EDGE_CURVE('E1164',#407,#359,#1558,.F.);
#1560=ORIENTED_EDGE('',*,*,#1559,.F.);
#1561=ORIENTED_EDGE('',*,*,#408,.T.);
#1562=DIRECTION('',(-0.258819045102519,0.965925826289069,0.));
#1563=VECTOR('',#1562,1.);
#1564=CARTESIAN_POINT('',(30.7735828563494,4.79924727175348,70.0846240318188));
#1565=LINE('',#1564,#1563);
#1566=EDGE_CURVE('E1131',#447,#399,#1565,.F.);
#1567=ORIENTED_EDGE('',*,*,#1566,.F.);
#1568=ORIENTED_EDGE('',*,*,#448,.T.);
#1569=DIRECTION('',(-0.707106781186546,0.707106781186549,0.));
#1570=VECTOR('',#1569,1.);
#1571=CARTESIAN_POINT('',(24.2510808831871,19.5430614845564,70.0846240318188));
#1572=LINE('',#1571,#1570);
#1573=EDGE_CURVE('E1098',#487,#439,#1572,.F.);
#1574=ORIENTED_EDGE('',*,*,#1573,.F.);
#1575=ORIENTED_EDGE('',*,*,#488,.T.);
#1576=EDGE_LOOP('',(#1497,#1498,#1504,#1505,#1511,#1512,#1518,#1519,#1525,#1526,#1532,#1533,
#1539,#1540,#1546,#1547,#1553,#1554,#1560,#1561,#1567,#1568,#1574,#1575));
#1577=FACE_BOUND('',#1576,.T.);
#1578=ADVANCED_FACE('F1513',(#1577),#1491,.T.);
#1579=CARTESIAN_POINT('',(-4.79924727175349,-30.7735828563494,70.0846240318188));
#1580=DIRECTION('',(0.,-1.,0.));
#1581=DIRECTION('',(0.,0.,-1.));
#1582=AXIS2_PLACEMENT_3D('',#1579,#1580,#1581);
#1583=PLANE('',#1582);
#1584=DIRECTION('',(0.,0.,1.));
#1585=VECTOR('',#1584,1.);
#1586=CARTESIAN_POINT('',(4.79924727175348,-30.7735828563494,70.0846240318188));
#1587=LINE('',#1586,#1585);
#1588=CARTESIAN_POINT('',(4.79924727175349,-30.7735828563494,44.737293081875));
#1589=VERTEX_POINT('',#1588);
#1590=EDGE_CURVE('E1230',#279,#1589,#1587,.F.);
#1591=ORIENTED_EDGE('',*,*,#1590,.F.);
#1592=DIRECTION('',(0.040410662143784,0.,0.999183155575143));
#1593=VECTOR('',#1592,1.);
#1594=CARTESIAN_POINT('',(3.77410746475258,-30.7735828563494,44.737293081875));
#1595=LINE('',#1594,#1593);
#1596=CARTESIAN_POINT('',(3.77410746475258,-30.7735828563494,44.737293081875));
#1597=VERTEX_POINT('',#1596);
#1598=EDGE_CURVE('E810',#1597,#279,#1595,.T.);
#1599=ORIENTED_EDGE('',*,*,#1598,.F.);
#1600=DIRECTION('',(1.,0.,0.));
#1601=VECTOR('',#1600,1.);
#1602=CARTESIAN_POINT('',(0.,-30.7735828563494,44.737293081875));
#1603=LINE('',#1602,#1601);
#1604=EDGE_CURVE('E1453',#1589,#1597,#1603,.F.);
#1605=ORIENTED_EDGE('',*,*,#1604,.F.);
#1606=EDGE_LOOP('',(#1591,#1599,#1605));
#1607=FACE_BOUND('',#1606,.T.);
#1608=ADVANCED_FACE('F1515',(#1607),#1583,.T.);
#1609=CARTESIAN_POINT('',(1.22837437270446,-18.5105529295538,19.4938609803));
#1610=DIRECTION('',(0.991559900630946,0.123291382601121,-0.0401023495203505));
#1611=DIRECTION('',(-0.123390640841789,0.992358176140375,0.));
#1612=AXIS2_PLACEMENT_3D('',#1609,#1610,#1611);
#1613=PLANE('',#1612);
#1614=DIRECTION('',(-0.115737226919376,0.702354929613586,-0.702354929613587));
#1615=VECTOR('',#1614,1.);
#1616=CARTESIAN_POINT('',(6.43180864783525,-50.0877542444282,51.0710622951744));
#1617=LINE('',#1616,#1615);
#1618=CARTESIAN_POINT('',(5.38810146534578,-43.7539850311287,44.737293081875));
#1619=VERTEX_POINT('',#1618);
#1620=EDGE_CURVE('E849',#580,#1619,#1617,.T.);
#1621=ORIENTED_EDGE('',*,*,#1620,.T.);
#1622=DIRECTION('',(0.123390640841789,-0.992358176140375,0.));
#1623=VECTOR('',#1622,1.);
#1624=CARTESIAN_POINT('',(3.77410746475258,-30.7735828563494,44.737293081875));
#1625=LINE('',#1624,#1623);
#1626=EDGE_CURVE('E1450',#1597,#1619,#1625,.T.);
#1627=ORIENTED_EDGE('',*,*,#1626,.F.);
#1628=ORIENTED_EDGE('',*,*,#1598,.T.);
#1629=ORIENTED_EDGE('',*,*,#581,.T.);
#1630=EDGE_LOOP('',(#1621,#1627,#1628,#1629));
#1631=FACE_BOUND('',#1630,.T.);
#1632=ADVANCED_FACE('F1518',(#1631),#1613,.T.);
#1633=CARTESIAN_POINT('',(-0.0109063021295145,-37.812926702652,38.7962347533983));
#1634=DIRECTION('',(0.,0.707106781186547,0.707106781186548));
#1635=DIRECTION('',(0.,-0.707106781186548,0.707106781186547));
#1636=AXIS2_PLACEMENT_3D('',#1633,#1634,#1635);
#1637=PLANE('',#1636);
#1638=ORIENTED_EDGE('',*,*,#1620,.F.);
#1639=ORIENTED_EDGE('',*,*,#589,.F.);
#1640=ORIENTED_EDGE('',*,*,#565,.F.);
#1641=ORIENTED_EDGE('',*,*,#613,.F.);
#1642=DIRECTION('',(-0.115737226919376,-0.702354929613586,0.702354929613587));
#1643=VECTOR('',#1642,1.);
#1644=CARTESIAN_POINT('',(-5.38810146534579,-43.7539850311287,44.737293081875));
#1645=LINE('',#1644,#1643);
#1646=CARTESIAN_POINT('',(-5.38810146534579,-43.7539850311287,44.737293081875));
#1647=VERTEX_POINT('',#1646);
#1648=EDGE_CURVE('E851',#1647,#606,#1645,.T.);
#1649=ORIENTED_EDGE('',*,*,#1648,.F.);
#1650=DIRECTION('',(1.,0.,0.));
#1651=VECTOR('',#1650,1.);
#1652=CARTESIAN_POINT('',(0.,-43.7539850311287,44.737293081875));
#1653=LINE('',#1652,#1651);
#1654=EDGE_CURVE('E1447',#1619,#1647,#1653,.F.);
#1655=ORIENTED_EDGE('',*,*,#1654,.F.);
#1656=EDGE_LOOP('',(#1638,#1639,#1640,#1641,#1649,#1655));
#1657=FACE_BOUND('',#1656,.T.);
#1658=ADVANCED_FACE('F1522',(#1657),#1637,.F.);
#1659=CARTESIAN_POINT('',(-6.43180864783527,-50.0877542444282,51.0710622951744));
#1660=DIRECTION('',(-0.991559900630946,0.123291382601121,-0.0401023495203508));
#1661=DIRECTION('',(-0.12339064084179,-0.992358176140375,0.));
#1662=AXIS2_PLACEMENT_3D('',#1659,#1660,#1661);
#1663=PLANE('',#1662);
#1664=ORIENTED_EDGE('',*,*,#1648,.T.);
#1665=ORIENTED_EDGE('',*,*,#607,.T.);
#1666=DIRECTION('',(-0.0404106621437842,0.,0.999183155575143));
#1667=VECTOR('',#1666,1.);
#1668=CARTESIAN_POINT('',(-3.77410746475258,-30.7735828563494,44.737293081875));
#1669=LINE('',#1668,#1667);
#1670=CARTESIAN_POINT('',(-3.77410746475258,-30.7735828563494,44.737293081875));
#1671=VERTEX_POINT('',#1670);
#1672=EDGE_CURVE('E861',#1671,#287,#1669,.T.);
#1673=ORIENTED_EDGE('',*,*,#1672,.F.);
#1674=DIRECTION('',(0.12339064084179,0.992358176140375,0.));
#1675=VECTOR('',#1674,1.);
#1676=CARTESIAN_POINT('',(-5.38810146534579,-43.7539850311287,44.737293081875));
#1677=LINE('',#1676,#1675);
#1678=EDGE_CURVE('E1444',#1647,#1671,#1677,.T.);
#1679=ORIENTED_EDGE('',*,*,#1678,.F.);
#1680=EDGE_LOOP('',(#1664,#1665,#1673,#1679));
#1681=FACE_BOUND('',#1680,.T.);
#1682=ADVANCED_FACE('F1526',(#1681),#1663,.T.);
#1683=CARTESIAN_POINT('',(-4.79924727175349,-30.7735828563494,70.0846240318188));
#1684=DIRECTION('',(0.,-1.,0.));
#1685=DIRECTION('',(0.,0.,-1.));
#1686=AXIS2_PLACEMENT_3D('',#1683,#1684,#1685);
#1687=PLANE('',#1686);
#1688=DIRECTION('',(0.,0.,1.));
#1689=VECTOR('',#1688,1.);
#1690=CARTESIAN_POINT('',(-4.79924727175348,-30.7735828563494,70.0846240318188));
#1691=LINE('',#1690,#1689);
#1692=CARTESIAN_POINT('',(-4.79924727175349,-30.7735828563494,44.737293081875));
#1693=VERTEX_POINT('',#1692);
#1694=EDGE_CURVE('E866',#1693,#287,#1691,.T.);
#1695=ORIENTED_EDGE('',*,*,#1694,.F.);
#1696=DIRECTION('',(1.,0.,0.));
#1697=VECTOR('',#1696,1.);
#1698=CARTESIAN_POINT('',(0.,-30.7735828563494,44.737293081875));
#1699=LINE('',#1698,#1697);
#1700=EDGE_CURVE('E1441',#1671,#1693,#1699,.F.);
#1701=ORIENTED_EDGE('',*,*,#1700,.F.);
#1702=ORIENTED_EDGE('',*,*,#1672,.T.);
#1703=EDGE_LOOP('',(#1695,#1701,#1702));
#1704=FACE_BOUND('',#1703,.T.);
#1705=ADVANCED_FACE('F1530',(#1704),#1687,.T.);
#1706=CARTESIAN_POINT('',(-11.230521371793,-29.0503281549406,70.0846240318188));
#1707=DIRECTION('',(-0.258819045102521,-0.965925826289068,0.));
#1708=DIRECTION('',(0.965925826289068,-0.258819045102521,0.));
#1709=AXIS2_PLACEMENT_3D('',#1706,#1707,#1708);
#1710=PLANE('',#1709);
#1711=ORIENTED_EDGE('',*,*,#1538,.T.);
#1712=DIRECTION('',(0.,0.,1.));
#1713=VECTOR('',#1712,1.);
#1714=CARTESIAN_POINT('',(-11.230521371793,-29.0503281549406,70.0846240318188));
#1715=LINE('',#1714,#1713);
#1716=CARTESIAN_POINT('',(-11.230521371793,-29.0503281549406,44.737293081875));
#1717=VERTEX_POINT('',#1716);
#1718=EDGE_CURVE('E870',#1717,#239,#1715,.T.);
#1719=ORIENTED_EDGE('',*,*,#1718,.F.);
#1720=DIRECTION('',(-0.965925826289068,0.258819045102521,0.));
#1721=VECTOR('',#1720,1.);
#1722=CARTESIAN_POINT('',(-4.79924727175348,-30.7735828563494,44.737293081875));
#1723=LINE('',#1722,#1721);
#1724=EDGE_CURVE('E1438',#1693,#1717,#1723,.T.);
#1725=ORIENTED_EDGE('',*,*,#1724,.F.);
#1726=ORIENTED_EDGE('',*,*,#1694,.T.);
#1727=EDGE_LOOP('',(#1711,#1719,#1725,#1726));
#1728=FACE_BOUND('',#1727,.T.);
#1729=ADVANCED_FACE('F1534',(#1728),#1710,.T.);
#1730=CARTESIAN_POINT('',(-19.5430614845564,-24.2510808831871,70.0846240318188));
#1731=DIRECTION('',(-0.5,-0.866025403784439,0.));
#1732=DIRECTION('',(0.866025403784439,-0.5,0.));
#1733=AXIS2_PLACEMENT_3D('',#1730,#1731,#1732);
#1734=PLANE('',#1733);
#1735=ORIENTED_EDGE('',*,*,#1718,.T.);
#1736=DIRECTION('',(0.0349966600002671,-0.0202053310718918,0.999183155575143));
#1737=VECTOR('',#1736,1.);
#1738=CARTESIAN_POINT('',(-12.1183184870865,-28.5377582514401,44.737293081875));
#1739=LINE('',#1738,#1737);
#1740=CARTESIAN_POINT('',(-12.1183184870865,-28.5377582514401,44.737293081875));
#1741=VERTEX_POINT('',#1740);
#1742=EDGE_CURVE('E875',#1741,#239,#1739,.T.);
#1743=ORIENTED_EDGE('',*,*,#1742,.F.);
#1744=DIRECTION('',(-0.866025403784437,0.500000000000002,0.));
#1745=VECTOR('',#1744,1.);
#1746=CARTESIAN_POINT('',(-11.230521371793,-29.0503281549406,44.737293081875));
#1747=LINE('',#1746,#1745);
#1748=EDGE_CURVE('E1435',#1717,#1741,#1747,.T.);
#1749=ORIENTED_EDGE('',*,*,#1748,.F.);
#1750=EDGE_LOOP('',(#1735,#1743,#1749));
#1751=FACE_BOUND('',#1750,.T.);
#1752=ADVANCED_FACE('F1538',(#1751),#1734,.T.);
#1753=CARTESIAN_POINT('',(-8.19147305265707,-16.6447962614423,19.4938609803));
#1754=DIRECTION('',(0.920361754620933,-0.389006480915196,-0.0401023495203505));
#1755=DIRECTION('',(0.389319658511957,0.921102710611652,0.));
#1756=AXIS2_PLACEMENT_3D('',#1753,#1754,#1755);
#1757=PLANE('',#1756);
#1758=DIRECTION('',(0.25094608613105,0.666125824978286,-0.702354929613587));
#1759=VECTOR('',#1758,1.);
#1760=CARTESIAN_POINT('',(-19.4737674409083,-46.5931719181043,51.0710622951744));
#1761=LINE('',#1760,#1759);
#1762=CARTESIAN_POINT('',(-17.2107597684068,-40.5861132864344,44.737293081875));
#1763=VERTEX_POINT('',#1762);
#1764=EDGE_CURVE('E882',#659,#1763,#1761,.T.);
#1765=ORIENTED_EDGE('',*,*,#1764,.T.);
#1766=DIRECTION('',(-0.389319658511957,-0.921102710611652,0.));
#1767=VECTOR('',#1766,1.);
#1768=CARTESIAN_POINT('',(-12.1183184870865,-28.5377582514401,44.737293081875));
#1769=LINE('',#1768,#1767);
#1770=EDGE_CURVE('E1432',#1741,#1763,#1769,.T.);
#1771=ORIENTED_EDGE('',*,*,#1770,.F.);
#1772=ORIENTED_EDGE('',*,*,#1742,.T.);
#1773=ORIENTED_EDGE('',*,*,#660,.T.);
#1774=EDGE_LOOP('',(#1765,#1771,#1772,#1773));
#1775=FACE_BOUND('',#1774,.T.);
#1776=ADVANCED_FACE('F1542',(#1775),#1757,.T.);
#1777=CARTESIAN_POINT('',(-18.9159084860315,-32.7415019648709,38.7962347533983));
#1778=DIRECTION('',(0.353553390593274,0.612372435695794,0.707106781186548));
#1779=DIRECTION('',(0.,-0.755928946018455,0.654653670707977));
#1780=AXIS2_PLACEMENT_3D('',#1777,#1778,#1779);
#1781=PLANE('',#1780);
#1782=ORIENTED_EDGE('',*,*,#1764,.F.);
#1783=ORIENTED_EDGE('',*,*,#668,.F.);
#1784=ORIENTED_EDGE('',*,*,#644,.F.);
#1785=ORIENTED_EDGE('',*,*,#692,.F.);
#1786=DIRECTION('',(-0.451408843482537,-0.550388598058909,0.702354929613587));
#1787=VECTOR('',#1786,1.);
#1788=CARTESIAN_POINT('',(-26.543225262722,-35.1980118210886,44.737293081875));
#1789=LINE('',#1788,#1787);
#1790=CARTESIAN_POINT('',(-26.543225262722,-35.1980118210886,44.737293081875));
#1791=VERTEX_POINT('',#1790);
#1792=EDGE_CURVE('E884',#1791,#685,#1789,.T.);
#1793=ORIENTED_EDGE('',*,*,#1792,.F.);
#1794=DIRECTION('',(-0.866025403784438,0.5,0.));
#1795=VECTOR('',#1794,1.);
#1796=CARTESIAN_POINT('',(-17.2107597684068,-40.5861132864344,44.737293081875));
#1797=LINE('',#1796,#1795);
#1798=EDGE_CURVE('E1429',#1763,#1791,#1797,.T.);
#1799=ORIENTED_EDGE('',*,*,#1798,.F.);
#1800=EDGE_LOOP('',(#1782,#1783,#1784,#1785,#1793,#1799));
#1801=FACE_BOUND('',#1800,.T.);
#1802=ADVANCED_FACE('F1546',(#1801),#1781,.F.);
#1803=CARTESIAN_POINT('',(-30.6139868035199,-40.161363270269,51.0710622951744));
#1804=DIRECTION('',(-0.797070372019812,0.602553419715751,-0.0401023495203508));
#1805=DIRECTION('',(-0.60303851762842,-0.797712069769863,0.));
#1806=AXIS2_PLACEMENT_3D('',#1803,#1804,#1805);
#1807=PLANE('',#1806);
#1808=ORIENTED_EDGE('',*,*,#1792,.T.);
#1809=ORIENTED_EDGE('',*,*,#686,.T.);
#1810=DIRECTION('',(-0.0349966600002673,0.0202053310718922,0.999183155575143));
#1811=VECTOR('',#1810,1.);
#1812=CARTESIAN_POINT('',(-18.6552643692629,-24.7636507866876,44.737293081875));
#1813=LINE('',#1812,#1811);
#1814=CARTESIAN_POINT('',(-18.6552643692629,-24.7636507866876,44.737293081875));
#1815=VERTEX_POINT('',#1814);
#1816=EDGE_CURVE('E894',#1815,#247,#1813,.T.);
#1817=ORIENTED_EDGE('',*,*,#1816,.F.);
#1818=DIRECTION('',(0.60303851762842,0.797712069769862,0.));
#1819=VECTOR('',#1818,1.);
#1820=CARTESIAN_POINT('',(-26.543225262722,-35.1980118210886,44.737293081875));
#1821=LINE('',#1820,#1819);
#1822=EDGE_CURVE('E1426',#1791,#1815,#1821,.T.);
#1823=ORIENTED_EDGE('',*,*,#1822,.F.);
#1824=EDGE_LOOP('',(#1808,#1809,#1817,#1823));
#1825=FACE_BOUND('',#1824,.T.);
#1826=ADVANCED_FACE('F1550',(#1825),#1807,.T.);
#1827=CARTESIAN_POINT('',(-19.5430614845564,-24.2510808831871,70.0846240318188));
#1828=DIRECTION('',(-0.5,-0.866025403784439,0.));
#1829=DIRECTION('',(0.866025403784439,-0.5,0.));
#1830=AXIS2_PLACEMENT_3D('',#1827,#1828,#1829);
#1831=PLANE('',#1830);
#1832=DIRECTION('',(0.,0.,1.));
#1833=VECTOR('',#1832,1.);
#1834=CARTESIAN_POINT('',(-19.5430614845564,-24.2510808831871,70.0846240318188));
#1835=LINE('',#1834,#1833);
#1836=CARTESIAN_POINT('',(-19.5430614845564,-24.2510808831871,44.737293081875));
#1837=VERTEX_POINT('',#1836);
#1838=EDGE_CURVE('E899',#1837,#247,#1835,.T.);
#1839=ORIENTED_EDGE('',*,*,#1838,.F.);
#1840=DIRECTION('',(-0.866025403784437,0.500000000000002,0.));
#1841=VECTOR('',#1840,1.);
#1842=CARTESIAN_POINT('',(-18.6552643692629,-24.7636507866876,44.737293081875));
#1843=LINE('',#1842,#1841);
#1844=EDGE_CURVE('E1423',#1815,#1837,#1843,.T.);
#1845=ORIENTED_EDGE('',*,*,#1844,.F.);
#1846=ORIENTED_EDGE('',*,*,#1816,.T.);
#1847=EDGE_LOOP('',(#1839,#1845,#1846));
#1848=FACE_BOUND('',#1847,.T.);
#1849=ADVANCED_FACE('F1554',(#1848),#1831,.T.);
#1850=CARTESIAN_POINT('',(-24.2510808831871,-19.5430614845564,70.0846240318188));
#1851=DIRECTION('',(-0.707106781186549,-0.707106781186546,0.));
#1852=DIRECTION('',(0.707106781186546,-0.707106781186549,0.));
#1853=AXIS2_PLACEMENT_3D('',#1850,#1851,#1852);
#1854=PLANE('',#1853);
#1855=ORIENTED_EDGE('',*,*,#1531,.T.);
#1856=DIRECTION('',(0.,0.,1.));
#1857=VECTOR('',#1856,1.);
#1858=CARTESIAN_POINT('',(-24.2510808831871,-19.5430614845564,70.0846240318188));
#1859=LINE('',#1858,#1857);
#1860=CARTESIAN_POINT('',(-24.2510808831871,-19.5430614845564,44.737293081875));
#1861=VERTEX_POINT('',#1860);
#1862=EDGE_CURVE('E903',#1861,#199,#1859,.T.);
#1863=ORIENTED_EDGE('',*,*,#1862,.F.);
#1864=DIRECTION('',(-0.707106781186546,0.707106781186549,0.));
#1865=VECTOR('',#1864,1.);
#1866=CARTESIAN_POINT('',(-19.5430614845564,-24.2510808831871,44.737293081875));
#1867=LINE('',#1866,#1865);
#1868=EDGE_CURVE('E1420',#1837,#1861,#1867,.T.);
#1869=ORIENTED_EDGE('',*,*,#1868,.F.);
#1870=ORIENTED_EDGE('',*,*,#1838,.T.);
#1871=EDGE_LOOP('',(#1855,#1863,#1869,#1870));
#1872=FACE_BOUND('',#1871,.T.);
#1873=ADVANCED_FACE('F1558',(#1872),#1854,.T.);
#1874=CARTESIAN_POINT('',(-29.0503281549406,-11.230521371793,70.0846240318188));
#1875=DIRECTION('',(-0.866025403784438,-0.500000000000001,0.));
#1876=DIRECTION('',(0.500000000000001,-0.866025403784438,0.));
#1877=AXIS2_PLACEMENT_3D('',#1874,#1875,#1876);
#1878=PLANE('',#1877);
#1879=ORIENTED_EDGE('',*,*,#1862,.T.);
#1880=DIRECTION('',(0.0202053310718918,-0.0349966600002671,0.999183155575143));
#1881=VECTOR('',#1880,1.);
#1882=CARTESIAN_POINT('',(-24.7636507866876,-18.6552643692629,44.737293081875));
#1883=LINE('',#1882,#1881);
#1884=CARTESIAN_POINT('',(-24.7636507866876,-18.6552643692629,44.737293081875));
#1885=VERTEX_POINT('',#1884);
#1886=EDGE_CURVE('E908',#1885,#199,#1883,.T.);
#1887=ORIENTED_EDGE('',*,*,#1886,.F.);
#1888=DIRECTION('',(-0.499999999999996,0.866025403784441,0.));
#1889=VECTOR('',#1888,1.);
#1890=CARTESIAN_POINT('',(-24.2510808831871,-19.5430614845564,44.737293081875));
#1891=LINE('',#1890,#1889);
#1892=EDGE_CURVE('E1417',#1861,#1885,#1891,.T.);
#1893=ORIENTED_EDGE('',*,*,#1892,.F.);
#1894=EDGE_LOOP('',(#1879,#1887,#1893));
#1895=FACE_BOUND('',#1894,.T.);
#1896=ADVANCED_FACE('F1562',(#1895),#1878,.T.);
#1897=CARTESIAN_POINT('',(-15.4164218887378,-10.3190798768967,19.4938609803));
#1898=DIRECTION('',(0.60255341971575,-0.797070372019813,-0.0401023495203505));
#1899=DIRECTION('',(0.797712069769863,0.603038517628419,0.));
#1900=AXIS2_PLACEMENT_3D('',#1897,#1898,#1899);
#1901=PLANE('',#1900);
#1902=DIRECTION('',(0.550388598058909,0.451408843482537,-0.702354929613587));
#1903=VECTOR('',#1902,1.);
#1904=CARTESIAN_POINT('',(-40.161363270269,-30.6139868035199,51.0710622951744));
#1905=LINE('',#1904,#1903);
#1906=CARTESIAN_POINT('',(-35.1980118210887,-26.543225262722,44.737293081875));
#1907=VERTEX_POINT('',#1906);
#1908=EDGE_CURVE('E915',#738,#1907,#1905,.T.);
#1909=ORIENTED_EDGE('',*,*,#1908,.T.);
#1910=DIRECTION('',(-0.797712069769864,-0.603038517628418,0.));
#1911=VECTOR('',#1910,1.);
#1912=CARTESIAN_POINT('',(-24.7636507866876,-18.6552643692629,44.737293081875));
#1913=LINE('',#1912,#1911);
#1914=EDGE_CURVE('E1414',#1885,#1907,#1913,.T.);
#1915=ORIENTED_EDGE('',*,*,#1914,.F.);
#1916=ORIENTED_EDGE('',*,*,#1886,.T.);
#1917=ORIENTED_EDGE('',*,*,#739,.T.);
#1918=EDGE_LOOP('',(#1909,#1915,#1916,#1917));
#1919=FACE_BOUND('',#1918,.T.);
#1920=ADVANCED_FACE('F1566',(#1919),#1901,.T.);
#1921=CARTESIAN_POINT('',(-32.7524082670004,-18.8970182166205,38.7962347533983));
#1922=DIRECTION('',(0.612372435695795,0.353553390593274,0.707106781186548));
#1923=DIRECTION('',(0.755928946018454,0.,-0.654653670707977));
#1924=AXIS2_PLACEMENT_3D('',#1921,#1922,#1923);
#1925=PLANE('',#1924);
#1926=ORIENTED_EDGE('',*,*,#1908,.F.);
#1927=ORIENTED_EDGE('',*,*,#747,.F.);
#1928=ORIENTED_EDGE('',*,*,#723,.F.);
#1929=ORIENTED_EDGE('',*,*,#771,.F.);
#1930=DIRECTION('',(-0.666125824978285,-0.25094608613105,0.702354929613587));
#1931=VECTOR('',#1930,1.);
#1932=CARTESIAN_POINT('',(-40.5861132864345,-17.2107597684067,44.737293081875));
#1933=LINE('',#1932,#1931);
#1934=CARTESIAN_POINT('',(-40.5861132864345,-17.2107597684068,44.737293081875));
#1935=VERTEX_POINT('',#1934);
#1936=EDGE_CURVE('E917',#1935,#764,#1933,.T.);
#1937=ORIENTED_EDGE('',*,*,#1936,.F.);
#1938=DIRECTION('',(-0.499999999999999,0.866025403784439,0.));
#1939=VECTOR('',#1938,1.);
#1940=CARTESIAN_POINT('',(-35.1980118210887,-26.543225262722,44.737293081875));
#1941=LINE('',#1940,#1939);
#1942=EDGE_CURVE('E1411',#1907,#1935,#1941,.T.);
#1943=ORIENTED_EDGE('',*,*,#1942,.F.);
#1944=EDGE_LOOP('',(#1926,#1927,#1928,#1929,#1937,#1943));
#1945=FACE_BOUND('',#1944,.T.);
#1946=ADVANCED_FACE('F1570',(#1945),#1925,.F.);
#1947=CARTESIAN_POINT('',(-46.5931719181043,-19.4737674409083,51.0710622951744));
#1948=DIRECTION('',(-0.389006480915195,0.920361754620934,-0.0401023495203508));
#1949=DIRECTION('',(-0.921102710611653,-0.389319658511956,0.));
#1950=AXIS2_PLACEMENT_3D('',#1947,#1948,#1949);
#1951=PLANE('',#1950);
#1952=ORIENTED_EDGE('',*,*,#1936,.T.);
#1953=ORIENTED_EDGE('',*,*,#765,.T.);
#1954=DIRECTION('',(-0.0202053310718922,0.0349966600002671,0.999183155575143));
#1955=VECTOR('',#1954,1.);
#1956=CARTESIAN_POINT('',(-28.5377582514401,-12.1183184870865,44.737293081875));
#1957=LINE('',#1956,#1955);
#1958=CARTESIAN_POINT('',(-28.5377582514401,-12.1183184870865,44.737293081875));
#1959=VERTEX_POINT('',#1958);
#1960=EDGE_CURVE('E927',#1959,#207,#1957,.T.);
#1961=ORIENTED_EDGE('',*,*,#1960,.F.);
#1962=DIRECTION('',(0.921102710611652,0.389319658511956,0.));
#1963=VECTOR('',#1962,1.);
#1964=CARTESIAN_POINT('',(-40.5861132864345,-17.2107597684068,44.737293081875));
#1965=LINE('',#1964,#1963);
#1966=EDGE_CURVE('E1408',#1935,#1959,#1965,.T.);
#1967=ORIENTED_EDGE('',*,*,#1966,.F.);
#1968=EDGE_LOOP('',(#1952,#1953,#1961,#1967));
#1969=FACE_BOUND('',#1968,.T.);
#1970=ADVANCED_FACE('F1574',(#1969),#1951,.T.);
#1971=CARTESIAN_POINT('',(-29.0503281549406,-11.230521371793,70.0846240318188));
#1972=DIRECTION('',(-0.866025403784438,-0.500000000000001,0.));
#1973=DIRECTION('',(0.500000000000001,-0.866025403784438,0.));
#1974=AXIS2_PLACEMENT_3D('',#1971,#1972,#1973);
#1975=PLANE('',#1974);
#1976=DIRECTION('',(0.,0.,1.));
#1977=VECTOR('',#1976,1.);
#1978=CARTESIAN_POINT('',(-29.0503281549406,-11.230521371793,70.0846240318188));
#1979=LINE('',#1978,#1977);
#1980=CARTESIAN_POINT('',(-29.0503281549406,-11.230521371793,44.737293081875));
#1981=VERTEX_POINT('',#1980);
#1982=EDGE_CURVE('E932',#1981,#207,#1979,.T.);
#1983=ORIENTED_EDGE('',*,*,#1982,.F.);
#1984=DIRECTION('',(-0.500000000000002,0.866025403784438,0.));
#1985=VECTOR('',#1984,1.);
#1986=CARTESIAN_POINT('',(-28.5377582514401,-12.1183184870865,44.737293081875));
#1987=LINE('',#1986,#1985);
#1988=EDGE_CURVE('E1405',#1959,#1981,#1987,.T.);
#1989=ORIENTED_EDGE('',*,*,#1988,.F.);
#1990=ORIENTED_EDGE('',*,*,#1960,.T.);
#1991=EDGE_LOOP('',(#1983,#1989,#1990));
#1992=FACE_BOUND('',#1991,.T.);
#1993=ADVANCED_FACE('F1578',(#1992),#1975,.T.);
#1994=CARTESIAN_POINT('',(-30.7735828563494,-4.79924727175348,70.0846240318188));
#1995=DIRECTION('',(-0.965925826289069,-0.25881904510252,0.));
#1996=DIRECTION('',(0.25881904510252,-0.965925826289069,0.));
#1997=AXIS2_PLACEMENT_3D('',#1994,#1995,#1996);
#1998=PLANE('',#1997);
#1999=ORIENTED_EDGE('',*,*,#1524,.T.);
#2000=DIRECTION('',(0.,0.,1.));
#2001=VECTOR('',#2000,1.);
#2002=CARTESIAN_POINT('',(-30.7735828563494,-4.79924727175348,70.0846240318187));
#2003=LINE('',#2002,#2001);
#2004=CARTESIAN_POINT('',(-30.7735828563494,-4.79924727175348,44.737293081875));
#2005=VERTEX_POINT('',#2004);
#2006=EDGE_CURVE('E936',#2005,#159,#2003,.T.);
#2007=ORIENTED_EDGE('',*,*,#2006,.F.);
#2008=DIRECTION('',(-0.25881904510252,0.965925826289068,0.));
#2009=VECTOR('',#2008,1.);
#2010=CARTESIAN_POINT('',(-29.0503281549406,-11.230521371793,44.737293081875));
#2011=LINE('',#2010,#2009);
#2012=EDGE_CURVE('E1402',#1981,#2005,#2011,.T.);
#2013=ORIENTED_EDGE('',*,*,#2012,.F.);
#2014=ORIENTED_EDGE('',*,*,#1982,.T.);
#2015=EDGE_LOOP('',(#1999,#2007,#2013,#2014));
#2016=FACE_BOUND('',#2015,.T.);
#2017=ADVANCED_FACE('F1582',(#2016),#1998,.T.);
#2018=CARTESIAN_POINT('',(-30.7735828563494,4.79924727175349,70.0846240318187));
#2019=DIRECTION('',(-1.,0.,0.));
#2020=DIRECTION('',(0.,0.,1.));
#2021=AXIS2_PLACEMENT_3D('',#2018,#2019,#2020);
#2022=PLANE('',#2021);
#2023=ORIENTED_EDGE('',*,*,#2006,.T.);
#2024=DIRECTION('',(0.,-0.040410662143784,0.999183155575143));
#2025=VECTOR('',#2024,1.);
#2026=CARTESIAN_POINT('',(-30.7735828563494,-3.77410746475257,44.737293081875));
#2027=LINE('',#2026,#2025);
#2028=CARTESIAN_POINT('',(-30.7735828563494,-3.77410746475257,44.737293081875));
#2029=VERTEX_POINT('',#2028);
#2030=EDGE_CURVE('E941',#2029,#159,#2027,.T.);
#2031=ORIENTED_EDGE('',*,*,#2030,.F.);
#2032=DIRECTION('',(0.,1.,0.));
#2033=VECTOR('',#2032,1.);
#2034=CARTESIAN_POINT('',(-30.7735828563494,22.8558007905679,44.737293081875));
#2035=LINE('',#2034,#2033);
#2036=EDGE_CURVE('E1399',#2005,#2029,#2035,.T.);
#2037=ORIENTED_EDGE('',*,*,#2036,.F.);
#2038=EDGE_LOOP('',(#2023,#2031,#2037));
#2039=FACE_BOUND('',#2038,.T.);
#2040=ADVANCED_FACE('F1586',(#2039),#2022,.T.);
#2041=CARTESIAN_POINT('',(-18.5105529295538,-1.22837437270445,19.4938609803));
#2042=DIRECTION('',(0.123291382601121,-0.991559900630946,-0.0401023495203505));
#2043=DIRECTION('',(0.992358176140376,0.123390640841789,0.));
#2044=AXIS2_PLACEMENT_3D('',#2041,#2042,#2043);
#2045=PLANE('',#2044);
#2046=DIRECTION('',(0.702354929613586,0.115737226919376,-0.702354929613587));
#2047=VECTOR('',#2046,1.);
#2048=CARTESIAN_POINT('',(-50.0877542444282,-6.43180864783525,51.0710622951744));
#2049=LINE('',#2048,#2047);
#2050=CARTESIAN_POINT('',(-43.7539850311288,-5.38810146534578,44.737293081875));
#2051=VERTEX_POINT('',#2050);
#2052=EDGE_CURVE('E948',#817,#2051,#2049,.T.);
#2053=ORIENTED_EDGE('',*,*,#2052,.T.);
#2054=DIRECTION('',(-0.992358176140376,-0.123390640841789,0.));
#2055=VECTOR('',#2054,1.);
#2056=CARTESIAN_POINT('',(-30.7735828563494,-3.77410746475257,44.737293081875));
#2057=LINE('',#2056,#2055);
#2058=EDGE_CURVE('E1396',#2029,#2051,#2057,.T.);
#2059=ORIENTED_EDGE('',*,*,#2058,.F.);
#2060=ORIENTED_EDGE('',*,*,#2030,.T.);
#2061=ORIENTED_EDGE('',*,*,#818,.T.);
#2062=EDGE_LOOP('',(#2053,#2059,#2060,#2061));
#2063=FACE_BOUND('',#2062,.T.);
#2064=ADVANCED_FACE('F1590',(#2063),#2045,.T.);
#2065=CARTESIAN_POINT('',(-37.812926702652,0.0109063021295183,38.7962347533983));
#2066=DIRECTION('',(0.707106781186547,0.,0.707106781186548));
#2067=DIRECTION('',(0.707106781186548,0.,-0.707106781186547));
#2068=AXIS2_PLACEMENT_3D('',#2065,#2066,#2067);
#2069=PLANE('',#2068);
#2070=ORIENTED_EDGE('',*,*,#2052,.F.);
#2071=ORIENTED_EDGE('',*,*,#826,.F.);
#2072=ORIENTED_EDGE('',*,*,#802,.F.);
#2073=ORIENTED_EDGE('',*,*,#850,.F.);
#2074=DIRECTION('',(-0.702354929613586,0.115737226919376,0.702354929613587));
#2075=VECTOR('',#2074,1.);
#2076=CARTESIAN_POINT('',(-43.7539850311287,5.38810146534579,44.737293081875));
#2077=LINE('',#2076,#2075);
#2078=CARTESIAN_POINT('',(-43.7539850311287,5.38810146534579,44.737293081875));
#2079=VERTEX_POINT('',#2078);
#2080=EDGE_CURVE('E950',#2079,#843,#2077,.T.);
#2081=ORIENTED_EDGE('',*,*,#2080,.F.);
#2082=DIRECTION('',(0.,1.,0.));
#2083=VECTOR('',#2082,1.);
#2084=CARTESIAN_POINT('',(-43.7539850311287,22.8558007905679,44.737293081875));
#2085=LINE('',#2084,#2083);
#2086=EDGE_CURVE('E1393',#2051,#2079,#2085,.T.);
#2087=ORIENTED_EDGE('',*,*,#2086,.F.);
#2088=EDGE_LOOP('',(#2070,#2071,#2072,#2073,#2081,#2087));
#2089=FACE_BOUND('',#2088,.T.);
#2090=ADVANCED_FACE('F1594',(#2089),#2069,.F.);
#2091=CARTESIAN_POINT('',(-50.0877542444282,6.43180864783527,51.0710622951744));
#2092=DIRECTION('',(0.123291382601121,0.991559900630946,-0.0401023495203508));
#2093=DIRECTION('',(-0.992358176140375,0.12339064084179,0.));
#2094=AXIS2_PLACEMENT_3D('',#2091,#2092,#2093);
#2095=PLANE('',#2094);
#2096=ORIENTED_EDGE('',*,*,#2080,.T.);
#2097=ORIENTED_EDGE('',*,*,#844,.T.);
#2098=DIRECTION('',(0.,0.0404106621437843,0.999183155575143));
#2099=VECTOR('',#2098,1.);
#2100=CARTESIAN_POINT('',(-30.7735828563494,3.77410746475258,44.737293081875));
#2101=LINE('',#2100,#2099);
#2102=CARTESIAN_POINT('',(-30.7735828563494,3.77410746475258,44.737293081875));
#2103=VERTEX_POINT('',#2102);
#2104=EDGE_CURVE('E960',#2103,#167,#2101,.T.);
#2105=ORIENTED_EDGE('',*,*,#2104,.F.);
#2106=DIRECTION('',(0.992358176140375,-0.12339064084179,0.));
#2107=VECTOR('',#2106,1.);
#2108=CARTESIAN_POINT('',(-43.7539850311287,5.38810146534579,44.737293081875));
#2109=LINE('',#2108,#2107);
#2110=EDGE_CURVE('E1390',#2079,#2103,#2109,.T.);
#2111=ORIENTED_EDGE('',*,*,#2110,.F.);
#2112=EDGE_LOOP('',(#2096,#2097,#2105,#2111));
#2113=FACE_BOUND('',#2112,.T.);
#2114=ADVANCED_FACE('F1598',(#2113),#2095,.T.);
#2115=CARTESIAN_POINT('',(-30.7735828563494,4.79924727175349,70.0846240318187));
#2116=DIRECTION('',(-1.,0.,0.));
#2117=DIRECTION('',(0.,0.,1.));
#2118=AXIS2_PLACEMENT_3D('',#2115,#2116,#2117);
#2119=PLANE('',#2118);
#2120=DIRECTION('',(0.,0.,1.));
#2121=VECTOR('',#2120,1.);
#2122=CARTESIAN_POINT('',(-30.7735828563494,4.79924727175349,70.0846240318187));
#2123=LINE('',#2122,#2121);
#2124=CARTESIAN_POINT('',(-30.7735828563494,4.7992472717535,44.737293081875));
#2125=VERTEX_POINT('',#2124);
#2126=EDGE_CURVE('E965',#2125,#167,#2123,.T.);
#2127=ORIENTED_EDGE('',*,*,#2126,.F.);
#2128=DIRECTION('',(0.,1.,0.));
#2129=VECTOR('',#2128,1.);
#2130=CARTESIAN_POINT('',(-30.7735828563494,22.8558007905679,44.737293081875));
#2131=LINE('',#2130,#2129);
#2132=EDGE_CURVE('E1387',#2103,#2125,#2131,.T.);
#2133=ORIENTED_EDGE('',*,*,#2132,.F.);
#2134=ORIENTED_EDGE('',*,*,#2104,.T.);
#2135=EDGE_LOOP('',(#2127,#2133,#2134));
#2136=FACE_BOUND('',#2135,.T.);
#2137=ADVANCED_FACE('F1602',(#2136),#2119,.T.);
#2138=CARTESIAN_POINT('',(-29.0503281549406,11.230521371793,70.0846240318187));
#2139=DIRECTION('',(-0.965925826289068,0.258819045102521,0.));
#2140=DIRECTION('',(-0.258819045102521,-0.965925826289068,0.));
#2141=AXIS2_PLACEMENT_3D('',#2138,#2139,#2140);
#2142=PLANE('',#2141);
#2143=ORIENTED_EDGE('',*,*,#1517,.T.);
#2144=DIRECTION('',(0.,0.,1.));
#2145=VECTOR('',#2144,1.);
#2146=CARTESIAN_POINT('',(-29.0503281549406,11.230521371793,70.0846240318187));
#2147=LINE('',#2146,#2145);
#2148=CARTESIAN_POINT('',(-29.0503281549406,11.230521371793,44.737293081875));
#2149=VERTEX_POINT('',#2148);
#2150=EDGE_CURVE('E969',#2149,#119,#2147,.T.);
#2151=ORIENTED_EDGE('',*,*,#2150,.F.);
#2152=DIRECTION('',(0.258819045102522,0.965925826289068,0.));
#2153=VECTOR('',#2152,1.);
#2154=CARTESIAN_POINT('',(-30.7735828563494,4.79924727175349,44.737293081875));
#2155=LINE('',#2154,#2153);
#2156=EDGE_CURVE('E1384',#2125,#2149,#2155,.T.);
#2157=ORIENTED_EDGE('',*,*,#2156,.F.);
#2158=ORIENTED_EDGE('',*,*,#2126,.T.);
#2159=EDGE_LOOP('',(#2143,#2151,#2157,#2158));
#2160=FACE_BOUND('',#2159,.T.);
#2161=ADVANCED_FACE('F1606',(#2160),#2142,.T.);
#2162=CARTESIAN_POINT('',(-24.2510808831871,19.5430614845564,70.0846240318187));
#2163=DIRECTION('',(-0.866025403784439,0.499999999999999,0.));
#2164=DIRECTION('',(-0.499999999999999,-0.866025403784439,0.));
#2165=AXIS2_PLACEMENT_3D('',#2162,#2163,#2164);
#2166=PLANE('',#2165);
#2167=ORIENTED_EDGE('',*,*,#2150,.T.);
#2168=DIRECTION('',(-0.020205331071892,-0.034996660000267,0.999183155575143));
#2169=VECTOR('',#2168,1.);
#2170=CARTESIAN_POINT('',(-28.5377582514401,12.1183184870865,44.737293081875));
#2171=LINE('',#2170,#2169);
#2172=CARTESIAN_POINT('',(-28.5377582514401,12.1183184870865,44.737293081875));
#2173=VERTEX_POINT('',#2172);
#2174=EDGE_CURVE('E974',#2173,#119,#2171,.T.);
#2175=ORIENTED_EDGE('',*,*,#2174,.F.);
#2176=DIRECTION('',(0.499999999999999,0.866025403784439,0.));
#2177=VECTOR('',#2176,1.);
#2178=CARTESIAN_POINT('',(-29.0503281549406,11.230521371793,44.737293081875));
#2179=LINE('',#2178,#2177);
#2180=EDGE_CURVE('E1381',#2149,#2173,#2179,.T.);
#2181=ORIENTED_EDGE('',*,*,#2180,.F.);
#2182=EDGE_LOOP('',(#2167,#2175,#2181));
#2183=FACE_BOUND('',#2182,.T.);
#2184=ADVANCED_FACE('F1610',(#2183),#2166,.T.);
#2185=CARTESIAN_POINT('',(-16.6447962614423,8.19147305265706,19.4938609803));
#2186=DIRECTION('',(-0.389006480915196,-0.920361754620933,-0.0401023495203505));
#2187=DIRECTION('',(0.921102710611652,-0.389319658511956,0.));
#2188=AXIS2_PLACEMENT_3D('',#2185,#2186,#2187);
#2189=PLANE('',#2188);
#2190=DIRECTION('',(0.666125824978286,-0.25094608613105,-0.702354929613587));
#2191=VECTOR('',#2190,1.);
#2192=CARTESIAN_POINT('',(-46.5931719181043,19.4737674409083,51.0710622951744));
#2193=LINE('',#2192,#2191);
#2194=CARTESIAN_POINT('',(-40.5861132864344,17.2107597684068,44.737293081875));
#2195=VERTEX_POINT('',#2194);
#2196=EDGE_CURVE('E981',#896,#2195,#2193,.T.);
#2197=ORIENTED_EDGE('',*,*,#2196,.T.);
#2198=DIRECTION('',(-0.921102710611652,0.389319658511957,0.));
#2199=VECTOR('',#2198,1.);
#2200=CARTESIAN_POINT('',(-28.5377582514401,12.1183184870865,44.737293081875));
#2201=LINE('',#2200,#2199);
#2202=EDGE_CURVE('E1378',#2173,#2195,#2201,.T.);
#2203=ORIENTED_EDGE('',*,*,#2202,.F.);
#2204=ORIENTED_EDGE('',*,*,#2174,.T.);
#2205=ORIENTED_EDGE('',*,*,#897,.T.);
#2206=EDGE_LOOP('',(#2197,#2203,#2204,#2205));
#2207=FACE_BOUND('',#2206,.T.);
#2208=ADVANCED_FACE('F1614',(#2207),#2189,.T.);
#2209=CARTESIAN_POINT('',(-32.7415019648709,18.9159084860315,38.7962347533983));
#2210=DIRECTION('',(0.612372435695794,-0.353553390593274,0.707106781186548));
#2211=DIRECTION('',(0.755928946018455,0.,-0.654653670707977));
#2212=AXIS2_PLACEMENT_3D('',#2209,#2210,#2211);
#2213=PLANE('',#2212);
#2214=ORIENTED_EDGE('',*,*,#2196,.F.);
#2215=ORIENTED_EDGE('',*,*,#905,.F.);
#2216=ORIENTED_EDGE('',*,*,#881,.F.);
#2217=ORIENTED_EDGE('',*,*,#929,.F.);
#2218=DIRECTION('',(-0.550388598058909,0.451408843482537,0.702354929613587));
#2219=VECTOR('',#2218,1.);
#2220=CARTESIAN_POINT('',(-35.1980118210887,26.543225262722,44.737293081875));
#2221=LINE('',#2220,#2219);
#2222=CARTESIAN_POINT('',(-35.1980118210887,26.543225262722,44.737293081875));
#2223=VERTEX_POINT('',#2222);
#2224=EDGE_CURVE('E983',#2223,#922,#2221,.T.);
#2225=ORIENTED_EDGE('',*,*,#2224,.F.);
#2226=DIRECTION('',(0.5,0.866025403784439,0.));
#2227=VECTOR('',#2226,1.);
#2228=CARTESIAN_POINT('',(-40.5861132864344,17.2107597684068,44.737293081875));
#2229=LINE('',#2228,#2227);
#2230=EDGE_CURVE('E1375',#2195,#2223,#2229,.T.);
#2231=ORIENTED_EDGE('',*,*,#2230,.F.);
#2232=EDGE_LOOP('',(#2214,#2215,#2216,#2217,#2225,#2231));
#2233=FACE_BOUND('',#2232,.T.);
#2234=ADVANCED_FACE('F1618',(#2233),#2213,.F.);
#2235=CARTESIAN_POINT('',(-40.161363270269,30.6139868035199,51.0710622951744));
#2236=DIRECTION('',(0.602553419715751,0.797070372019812,-0.0401023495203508));
#2237=DIRECTION('',(-0.797712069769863,0.603038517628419,0.));
#2238=AXIS2_PLACEMENT_3D('',#2235,#2236,#2237);
#2239=PLANE('',#2238);
#2240=ORIENTED_EDGE('',*,*,#2224,.T.);
#2241=ORIENTED_EDGE('',*,*,#923,.T.);
#2242=DIRECTION('',(0.0202053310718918,0.0349966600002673,0.999183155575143));
#2243=VECTOR('',#2242,1.);
#2244=CARTESIAN_POINT('',(-24.7636507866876,18.6552643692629,44.737293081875));
#2245=LINE('',#2244,#2243);
#2246=CARTESIAN_POINT('',(-24.7636507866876,18.6552643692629,44.737293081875));
#2247=VERTEX_POINT('',#2246);
#2248=EDGE_CURVE('E993',#2247,#127,#2245,.T.);
#2249=ORIENTED_EDGE('',*,*,#2248,.F.);
#2250=DIRECTION('',(0.797712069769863,-0.603038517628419,0.));
#2251=VECTOR('',#2250,1.);
#2252=CARTESIAN_POINT('',(-35.1980118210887,26.543225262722,44.737293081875));
#2253=LINE('',#2252,#2251);
#2254=EDGE_CURVE('E1372',#2223,#2247,#2253,.T.);
#2255=ORIENTED_EDGE('',*,*,#2254,.F.);
#2256=EDGE_LOOP('',(#2240,#2241,#2249,#2255));
#2257=FACE_BOUND('',#2256,.T.);
#2258=ADVANCED_FACE('F1622',(#2257),#2239,.T.);
#2259=CARTESIAN_POINT('',(-24.2510808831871,19.5430614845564,70.0846240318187));
#2260=DIRECTION('',(-0.866025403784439,0.499999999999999,0.));
#2261=DIRECTION('',(-0.499999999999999,-0.866025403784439,0.));
#2262=AXIS2_PLACEMENT_3D('',#2259,#2260,#2261);
#2263=PLANE('',#2262);
#2264=DIRECTION('',(0.,0.,1.));
#2265=VECTOR('',#2264,1.);
#2266=CARTESIAN_POINT('',(-24.2510808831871,19.5430614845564,70.0846240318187));
#2267=LINE('',#2266,#2265);
#2268=CARTESIAN_POINT('',(-24.2510808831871,19.5430614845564,44.737293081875));
#2269=VERTEX_POINT('',#2268);
#2270=EDGE_CURVE('E998',#2269,#127,#2267,.T.);
#2271=ORIENTED_EDGE('',*,*,#2270,.F.);
#2272=DIRECTION('',(0.5,0.866025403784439,0.));
#2273=VECTOR('',#2272,1.);
#2274=CARTESIAN_POINT('',(-24.7636507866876,18.6552643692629,44.737293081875));
#2275=LINE('',#2274,#2273);
#2276=EDGE_CURVE('E1369',#2247,#2269,#2275,.T.);
#2277=ORIENTED_EDGE('',*,*,#2276,.F.);
#2278=ORIENTED_EDGE('',*,*,#2248,.T.);
#2279=EDGE_LOOP('',(#2271,#2277,#2278));
#2280=FACE_BOUND('',#2279,.T.);
#2281=ADVANCED_FACE('F1626',(#2280),#2263,.T.);
#2282=CARTESIAN_POINT('',(-19.5430614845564,24.2510808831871,70.0846240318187));
#2283=DIRECTION('',(-0.707106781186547,0.707106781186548,0.));
#2284=DIRECTION('',(-0.707106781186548,-0.707106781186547,0.));
#2285=AXIS2_PLACEMENT_3D('',#2282,#2283,#2284);
#2286=PLANE('',#2285);
#2287=ORIENTED_EDGE('',*,*,#1510,.T.);
#2288=DIRECTION('',(0.,0.,1.));
#2289=VECTOR('',#2288,1.);
#2290=CARTESIAN_POINT('',(-19.5430614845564,24.2510808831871,70.0846240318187));
#2291=LINE('',#2290,#2289);
#2292=CARTESIAN_POINT('',(-19.5430614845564,24.2510808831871,44.737293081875));
#2293=VERTEX_POINT('',#2292);
#2294=EDGE_CURVE('E1002',#2293,#79,#2291,.T.);
#2295=ORIENTED_EDGE('',*,*,#2294,.F.);
#2296=DIRECTION('',(0.707106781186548,0.707106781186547,0.));
#2297=VECTOR('',#2296,1.);
#2298=CARTESIAN_POINT('',(-24.2510808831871,19.5430614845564,44.737293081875));
#2299=LINE('',#2298,#2297);
#2300=EDGE_CURVE('E1366',#2269,#2293,#2299,.T.);
#2301=ORIENTED_EDGE('',*,*,#2300,.F.);
#2302=ORIENTED_EDGE('',*,*,#2270,.T.);
#2303=EDGE_LOOP('',(#2287,#2295,#2301,#2302));
#2304=FACE_BOUND('',#2303,.T.);
#2305=ADVANCED_FACE('F1630',(#2304),#2286,.T.);
#2306=CARTESIAN_POINT('',(-11.230521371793,29.0503281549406,70.0846240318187));
#2307=DIRECTION('',(-0.5,0.866025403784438,0.));
#2308=DIRECTION('',(-0.866025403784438,-0.5,0.));
#2309=AXIS2_PLACEMENT_3D('',#2306,#2307,#2308);
#2310=PLANE('',#2309);
#2311=ORIENTED_EDGE('',*,*,#2294,.T.);
#2312=DIRECTION('',(-0.0349966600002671,-0.020205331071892,0.999183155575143));
#2313=VECTOR('',#2312,1.);
#2314=CARTESIAN_POINT('',(-18.6552643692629,24.7636507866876,44.737293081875));
#2315=LINE('',#2314,#2313);
#2316=CARTESIAN_POINT('',(-18.6552643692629,24.7636507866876,44.737293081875));
#2317=VERTEX_POINT('',#2316);
#2318=EDGE_CURVE('E1007',#2317,#79,#2315,.T.);
#2319=ORIENTED_EDGE('',*,*,#2318,.F.);
#2320=DIRECTION('',(0.866025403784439,0.499999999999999,0.));
#2321=VECTOR('',#2320,1.);
#2322=CARTESIAN_POINT('',(-19.5430614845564,24.2510808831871,44.737293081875));
#2323=LINE('',#2322,#2321);
#2324=EDGE_CURVE('E1363',#2293,#2317,#2323,.T.);
#2325=ORIENTED_EDGE('',*,*,#2324,.F.);
#2326=EDGE_LOOP('',(#2311,#2319,#2325));
#2327=FACE_BOUND('',#2326,.T.);
#2328=ADVANCED_FACE('F1634',(#2327),#2310,.T.);
#2329=CARTESIAN_POINT('',(-10.3190798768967,15.4164218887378,19.4938609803));
#2330=DIRECTION('',(-0.797070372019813,-0.60255341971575,-0.0401023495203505));
#2331=DIRECTION('',(0.603038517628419,-0.797712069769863,0.));
#2332=AXIS2_PLACEMENT_3D('',#2329,#2330,#2331);
#2333=PLANE('',#2332);
#2334=DIRECTION('',(0.451408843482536,-0.55038859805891,-0.702354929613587));
#2335=VECTOR('',#2334,1.);
#2336=CARTESIAN_POINT('',(-30.6139868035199,40.161363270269,51.0710622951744));
#2337=LINE('',#2336,#2335);
#2338=CARTESIAN_POINT('',(-26.543225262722,35.1980118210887,44.737293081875));
#2339=VERTEX_POINT('',#2338);
#2340=EDGE_CURVE('E1014',#975,#2339,#2337,.T.);
#2341=ORIENTED_EDGE('',*,*,#2340,.T.);
#2342=DIRECTION('',(-0.603038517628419,0.797712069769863,0.));
#2343=VECTOR('',#2342,1.);
#2344=CARTESIAN_POINT('',(-18.6552643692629,24.7636507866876,44.737293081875));
#2345=LINE('',#2344,#2343);
#2346=EDGE_CURVE('E1360',#2317,#2339,#2345,.T.);
#2347=ORIENTED_EDGE('',*,*,#2346,.F.);
#2348=ORIENTED_EDGE('',*,*,#2318,.T.);
#2349=ORIENTED_EDGE('',*,*,#976,.T.);
#2350=EDGE_LOOP('',(#2341,#2347,#2348,#2349));
#2351=FACE_BOUND('',#2350,.T.);
#2352=ADVANCED_FACE('F1638',(#2351),#2333,.T.);
#2353=CARTESIAN_POINT('',(-18.8970182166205,32.7524082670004,38.7962347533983));
#2354=DIRECTION('',(0.353553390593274,-0.612372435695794,0.707106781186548));
#2355=DIRECTION('',(0.,-0.755928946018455,-0.654653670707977));
#2356=AXIS2_PLACEMENT_3D('',#2353,#2354,#2355);
#2357=PLANE('',#2356);
#2358=ORIENTED_EDGE('',*,*,#2340,.F.);
#2359=ORIENTED_EDGE('',*,*,#984,.F.);
#2360=ORIENTED_EDGE('',*,*,#960,.F.);
#2361=ORIENTED_EDGE('',*,*,#1008,.F.);
#2362=DIRECTION('',(-0.25094608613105,0.666125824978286,0.702354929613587));
#2363=VECTOR('',#2362,1.);
#2364=CARTESIAN_POINT('',(-17.2107597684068,40.5861132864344,44.737293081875));
#2365=LINE('',#2364,#2363);
#2366=CARTESIAN_POINT('',(-17.2107597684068,40.5861132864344,44.737293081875));
#2367=VERTEX_POINT('',#2366);
#2368=EDGE_CURVE('E1016',#2367,#1001,#2365,.T.);
#2369=ORIENTED_EDGE('',*,*,#2368,.F.);
#2370=DIRECTION('',(0.866025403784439,0.5,0.));
#2371=VECTOR('',#2370,1.);
#2372=CARTESIAN_POINT('',(-26.543225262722,35.1980118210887,44.737293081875));
#2373=LINE('',#2372,#2371);
#2374=EDGE_CURVE('E1357',#2339,#2367,#2373,.T.);
#2375=ORIENTED_EDGE('',*,*,#2374,.F.);
#2376=EDGE_LOOP('',(#2358,#2359,#2360,#2361,#2369,#2375));
#2377=FACE_BOUND('',#2376,.T.);
#2378=ADVANCED_FACE('F1642',(#2377),#2357,.F.);
#2379=CARTESIAN_POINT('',(-19.4737674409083,46.5931719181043,51.0710622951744));
#2380=DIRECTION('',(0.920361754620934,0.389006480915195,-0.0401023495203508));
#2381=DIRECTION('',(-0.389319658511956,0.921102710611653,0.));
#2382=AXIS2_PLACEMENT_3D('',#2379,#2380,#2381);
#2383=PLANE('',#2382);
#2384=ORIENTED_EDGE('',*,*,#2368,.T.);
#2385=ORIENTED_EDGE('',*,*,#1002,.T.);
#2386=DIRECTION('',(0.0349966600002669,0.0202053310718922,0.999183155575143));
#2387=VECTOR('',#2386,1.);
#2388=CARTESIAN_POINT('',(-12.1183184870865,28.5377582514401,44.737293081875));
#2389=LINE('',#2388,#2387);
#2390=CARTESIAN_POINT('',(-12.1183184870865,28.5377582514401,44.737293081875));
#2391=VERTEX_POINT('',#2390);
#2392=EDGE_CURVE('E1026',#2391,#87,#2389,.T.);
#2393=ORIENTED_EDGE('',*,*,#2392,.F.);
#2394=DIRECTION('',(0.389319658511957,-0.921102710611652,0.));
#2395=VECTOR('',#2394,1.);
#2396=CARTESIAN_POINT('',(-17.2107597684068,40.5861132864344,44.737293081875));
#2397=LINE('',#2396,#2395);
#2398=EDGE_CURVE('E1354',#2367,#2391,#2397,.T.);
#2399=ORIENTED_EDGE('',*,*,#2398,.F.);
#2400=EDGE_LOOP('',(#2384,#2385,#2393,#2399));
#2401=FACE_BOUND('',#2400,.T.);
#2402=ADVANCED_FACE('F1646',(#2401),#2383,.T.);
#2403=CARTESIAN_POINT('',(-11.230521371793,29.0503281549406,70.0846240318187));
#2404=DIRECTION('',(-0.5,0.866025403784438,0.));
#2405=DIRECTION('',(-0.866025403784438,-0.5,0.));
#2406=AXIS2_PLACEMENT_3D('',#2403,#2404,#2405);
#2407=PLANE('',#2406);
#2408=DIRECTION('',(0.,0.,1.));
#2409=VECTOR('',#2408,1.);
#2410=CARTESIAN_POINT('',(-11.230521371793,29.0503281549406,70.0846240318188));
#2411=LINE('',#2410,#2409);
#2412=CARTESIAN_POINT('',(-11.230521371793,29.0503281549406,44.737293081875));
#2413=VERTEX_POINT('',#2412);
#2414=EDGE_CURVE('E1031',#2413,#87,#2411,.T.);
#2415=ORIENTED_EDGE('',*,*,#2414,.F.);
#2416=DIRECTION('',(0.866025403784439,0.499999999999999,0.));
#2417=VECTOR('',#2416,1.);
#2418=CARTESIAN_POINT('',(-12.1183184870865,28.5377582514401,44.737293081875));
#2419=LINE('',#2418,#2417);
#2420=EDGE_CURVE('E1351',#2391,#2413,#2419,.T.);
#2421=ORIENTED_EDGE('',*,*,#2420,.F.);
#2422=ORIENTED_EDGE('',*,*,#2392,.T.);
#2423=EDGE_LOOP('',(#2415,#2421,#2422));
#2424=FACE_BOUND('',#2423,.T.);
#2425=ADVANCED_FACE('F1650',(#2424),#2407,.T.);
#2426=CARTESIAN_POINT('',(-4.79924727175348,30.7735828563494,70.0846240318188));
#2427=DIRECTION('',(-0.25881904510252,0.965925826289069,0.));
#2428=DIRECTION('',(-0.965925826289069,-0.25881904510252,0.));
#2429=AXIS2_PLACEMENT_3D('',#2426,#2427,#2428);
#2430=PLANE('',#2429);
#2431=ORIENTED_EDGE('',*,*,#1503,.T.);
#2432=DIRECTION('',(0.,0.,1.));
#2433=VECTOR('',#2432,1.);
#2434=CARTESIAN_POINT('',(-4.79924727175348,30.7735828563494,70.0846240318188));
#2435=LINE('',#2434,#2433);
#2436=CARTESIAN_POINT('',(-4.79924727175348,30.7735828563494,44.737293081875));
#2437=VERTEX_POINT('',#2436);
#2438=EDGE_CURVE('E1035',#2437,#519,#2435,.T.);
#2439=ORIENTED_EDGE('',*,*,#2438,.F.);
#2440=DIRECTION('',(0.965925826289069,0.25881904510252,0.));
#2441=VECTOR('',#2440,1.);
#2442=CARTESIAN_POINT('',(-11.230521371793,29.0503281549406,44.737293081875));
#2443=LINE('',#2442,#2441);
#2444=EDGE_CURVE('E1348',#2413,#2437,#2443,.T.);
#2445=ORIENTED_EDGE('',*,*,#2444,.F.);
#2446=ORIENTED_EDGE('',*,*,#2414,.T.);
#2447=EDGE_LOOP('',(#2431,#2439,#2445,#2446));
#2448=FACE_BOUND('',#2447,.T.);
#2449=ADVANCED_FACE('F1654',(#2448),#2430,.T.);
#2450=CARTESIAN_POINT('',(4.79924727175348,30.7735828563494,70.0846240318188));
#2451=DIRECTION('',(0.,1.,0.));
#2452=DIRECTION('',(0.,0.,1.));
#2453=AXIS2_PLACEMENT_3D('',#2450,#2451,#2452);
#2454=PLANE('',#2453);
#2455=DIRECTION('',(1.,0.,0.));
#2456=VECTOR('',#2455,1.);
#2457=CARTESIAN_POINT('',(0.,30.7735828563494,44.737293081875));
#2458=LINE('',#2457,#2456);
#2459=CARTESIAN_POINT('',(-3.77410746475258,30.7735828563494,44.737293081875));
#2460=VERTEX_POINT('',#2459);
#2461=EDGE_CURVE('E1345',#2437,#2460,#2458,.T.);
#2462=ORIENTED_EDGE('',*,*,#2461,.F.);
#2463=ORIENTED_EDGE('',*,*,#2438,.T.);
#2464=DIRECTION('',(-0.040410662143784,0.,0.999183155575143));
#2465=VECTOR('',#2464,1.);
#2466=CARTESIAN_POINT('',(-3.77410746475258,30.7735828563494,44.737293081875));
#2467=LINE('',#2466,#2465);
#2468=EDGE_CURVE('E1040',#2460,#519,#2467,.T.);
#2469=ORIENTED_EDGE('',*,*,#2468,.F.);
#2470=EDGE_LOOP('',(#2462,#2463,#2469));
#2471=FACE_BOUND('',#2470,.T.);
#2472=ADVANCED_FACE('F1658',(#2471),#2454,.T.);
#2473=CARTESIAN_POINT('',(-1.22837437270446,18.5105529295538,19.4938609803));
#2474=DIRECTION('',(-0.991559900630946,-0.123291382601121,-0.0401023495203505));
#2475=DIRECTION('',(0.123390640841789,-0.992358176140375,0.));
#2476=AXIS2_PLACEMENT_3D('',#2473,#2474,#2475);
#2477=PLANE('',#2476);
#2478=DIRECTION('',(0.115737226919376,-0.702354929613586,-0.702354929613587));
#2479=VECTOR('',#2478,1.);
#2480=CARTESIAN_POINT('',(-6.43180864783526,50.0877542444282,51.0710622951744));
#2481=LINE('',#2480,#2479);
#2482=CARTESIAN_POINT('',(-5.38810146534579,43.7539850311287,44.737293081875));
#2483=VERTEX_POINT('',#2482);
#2484=EDGE_CURVE('E1047',#1054,#2483,#2481,.T.);
#2485=ORIENTED_EDGE('',*,*,#2484,.T.);
#2486=DIRECTION('',(-0.123390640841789,0.992358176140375,0.));
#2487=VECTOR('',#2486,1.);
#2488=CARTESIAN_POINT('',(-3.77410746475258,30.7735828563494,44.737293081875));
#2489=LINE('',#2488,#2487);
#2490=EDGE_CURVE('E1342',#2460,#2483,#2489,.T.);
#2491=ORIENTED_EDGE('',*,*,#2490,.F.);
#2492=ORIENTED_EDGE('',*,*,#2468,.T.);
#2493=ORIENTED_EDGE('',*,*,#1055,.T.);
#2494=EDGE_LOOP('',(#2485,#2491,#2492,#2493));
#2495=FACE_BOUND('',#2494,.T.);
#2496=ADVANCED_FACE('F1662',(#2495),#2477,.T.);
#2497=CARTESIAN_POINT('',(0.01090630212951,37.812926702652,38.7962347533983));
#2498=DIRECTION('',(0.,-0.707106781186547,0.707106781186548));
#2499=DIRECTION('',(0.,-0.707106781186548,-0.707106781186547));
#2500=AXIS2_PLACEMENT_3D('',#2497,#2498,#2499);
#2501=PLANE('',#2500);
#2502=ORIENTED_EDGE('',*,*,#2484,.F.);
#2503=ORIENTED_EDGE('',*,*,#1063,.F.);
#2504=ORIENTED_EDGE('',*,*,#1039,.F.);
#2505=ORIENTED_EDGE('',*,*,#1087,.F.);
#2506=DIRECTION('',(0.115737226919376,0.702354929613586,0.702354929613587));
#2507=VECTOR('',#2506,1.);
#2508=CARTESIAN_POINT('',(5.38810146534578,43.7539850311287,44.737293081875));
#2509=LINE('',#2508,#2507);
#2510=CARTESIAN_POINT('',(5.38810146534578,43.7539850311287,44.737293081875));
#2511=VERTEX_POINT('',#2510);
#2512=EDGE_CURVE('E1049',#2511,#1080,#2509,.T.);
#2513=ORIENTED_EDGE('',*,*,#2512,.F.);
#2514=DIRECTION('',(1.,0.,0.));
#2515=VECTOR('',#2514,1.);
#2516=CARTESIAN_POINT('',(0.,43.7539850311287,44.737293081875));
#2517=LINE('',#2516,#2515);
#2518=EDGE_CURVE('E1339',#2483,#2511,#2517,.T.);
#2519=ORIENTED_EDGE('',*,*,#2518,.F.);
#2520=EDGE_LOOP('',(#2502,#2503,#2504,#2505,#2513,#2519));
#2521=FACE_BOUND('',#2520,.T.);
#2522=ADVANCED_FACE('F1666',(#2521),#2501,.F.);
#2523=CARTESIAN_POINT('',(6.43180864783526,50.0877542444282,51.0710622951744));
#2524=DIRECTION('',(0.991559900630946,-0.123291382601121,-0.0401023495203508));
#2525=DIRECTION('',(0.12339064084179,0.992358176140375,0.));
#2526=AXIS2_PLACEMENT_3D('',#2523,#2524,#2525);
#2527=PLANE('',#2526);
#2528=ORIENTED_EDGE('',*,*,#2512,.T.);
#2529=ORIENTED_EDGE('',*,*,#1081,.T.);
#2530=DIRECTION('',(0.0404106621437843,0.,0.999183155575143));
#2531=VECTOR('',#2530,1.);
#2532=CARTESIAN_POINT('',(3.77410746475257,30.7735828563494,44.737293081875));
#2533=LINE('',#2532,#2531);
#2534=CARTESIAN_POINT('',(3.77410746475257,30.7735828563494,44.737293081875));
#2535=VERTEX_POINT('',#2534);
#2536=EDGE_CURVE('E1059',#2535,#527,#2533,.T.);
#2537=ORIENTED_EDGE('',*,*,#2536,.F.);
#2538=DIRECTION('',(-0.12339064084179,-0.992358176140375,0.));
#2539=VECTOR('',#2538,1.);
#2540=CARTESIAN_POINT('',(5.38810146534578,43.7539850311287,44.737293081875));
#2541=LINE('',#2540,#2539);
#2542=EDGE_CURVE('E1336',#2511,#2535,#2541,.T.);
#2543=ORIENTED_EDGE('',*,*,#2542,.F.);
#2544=EDGE_LOOP('',(#2528,#2529,#2537,#2543));
#2545=FACE_BOUND('',#2544,.T.);
#2546=ADVANCED_FACE('F1670',(#2545),#2527,.T.);
#2547=CARTESIAN_POINT('',(4.79924727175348,30.7735828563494,70.0846240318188));
#2548=DIRECTION('',(0.,1.,0.));
#2549=DIRECTION('',(0.,0.,1.));
#2550=AXIS2_PLACEMENT_3D('',#2547,#2548,#2549);
#2551=PLANE('',#2550);
#2552=ORIENTED_EDGE('',*,*,#2536,.T.);
#2553=DIRECTION('',(0.,0.,1.));
#2554=VECTOR('',#2553,1.);
#2555=CARTESIAN_POINT('',(4.79924727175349,30.7735828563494,70.0846240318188));
#2556=LINE('',#2555,#2554);
#2557=CARTESIAN_POINT('',(4.79924727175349,30.7735828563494,44.737293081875));
#2558=VERTEX_POINT('',#2557);
#2559=EDGE_CURVE('E1064',#2558,#527,#2556,.T.);
#2560=ORIENTED_EDGE('',*,*,#2559,.F.);
#2561=DIRECTION('',(1.,0.,0.));
#2562=VECTOR('',#2561,1.);
#2563=CARTESIAN_POINT('',(0.,30.7735828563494,44.737293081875));
#2564=LINE('',#2563,#2562);
#2565=EDGE_CURVE('E1333',#2535,#2558,#2564,.T.);
#2566=ORIENTED_EDGE('',*,*,#2565,.F.);
#2567=EDGE_LOOP('',(#2552,#2560,#2566));
#2568=FACE_BOUND('',#2567,.T.);
#2569=ADVANCED_FACE('F1674',(#2568),#2551,.T.);
#2570=CARTESIAN_POINT('',(11.230521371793,29.0503281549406,70.0846240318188));
#2571=DIRECTION('',(0.258819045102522,0.965925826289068,0.));
#2572=DIRECTION('',(-0.965925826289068,0.258819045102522,0.));
#2573=AXIS2_PLACEMENT_3D('',#2570,#2571,#2572);
#2574=PLANE('',#2573);
#2575=ORIENTED_EDGE('',*,*,#1496,.T.);
#2576=DIRECTION('',(0.,0.,1.));
#2577=VECTOR('',#2576,1.);
#2578=CARTESIAN_POINT('',(11.230521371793,29.0503281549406,70.0846240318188));
#2579=LINE('',#2578,#2577);
#2580=CARTESIAN_POINT('',(11.230521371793,29.0503281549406,44.737293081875));
#2581=VERTEX_POINT('',#2580);
#2582=EDGE_CURVE('E1068',#2581,#479,#2579,.T.);
#2583=ORIENTED_EDGE('',*,*,#2582,.F.);
#2584=DIRECTION('',(0.965925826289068,-0.258819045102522,0.));
#2585=VECTOR('',#2584,1.);
#2586=CARTESIAN_POINT('',(4.79924727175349,30.7735828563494,44.737293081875));
#2587=LINE('',#2586,#2585);
#2588=EDGE_CURVE('E1330',#2558,#2581,#2587,.T.);
#2589=ORIENTED_EDGE('',*,*,#2588,.F.);
#2590=ORIENTED_EDGE('',*,*,#2559,.T.);
#2591=EDGE_LOOP('',(#2575,#2583,#2589,#2590));
#2592=FACE_BOUND('',#2591,.T.);
#2593=ADVANCED_FACE('F1678',(#2592),#2574,.T.);
#2594=CARTESIAN_POINT('',(19.5430614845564,24.2510808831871,70.0846240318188));
#2595=DIRECTION('',(0.5,0.866025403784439,0.));
#2596=DIRECTION('',(-0.866025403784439,0.5,0.));
#2597=AXIS2_PLACEMENT_3D('',#2594,#2595,#2596);
#2598=PLANE('',#2597);
#2599=DIRECTION('',(0.866025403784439,-0.5,0.));
#2600=VECTOR('',#2599,1.);
#2601=CARTESIAN_POINT('',(11.230521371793,29.0503281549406,44.737293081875));
#2602=LINE('',#2601,#2600);
#2603=CARTESIAN_POINT('',(12.1183184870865,28.5377582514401,44.737293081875));
#2604=VERTEX_POINT('',#2603);
#2605=EDGE_CURVE('E1327',#2581,#2604,#2602,.T.);
#2606=ORIENTED_EDGE('',*,*,#2605,.F.);
#2607=ORIENTED_EDGE('',*,*,#2582,.T.);
#2608=DIRECTION('',(-0.0349966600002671,0.020205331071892,0.999183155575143));
#2609=VECTOR('',#2608,1.);
#2610=CARTESIAN_POINT('',(12.1183184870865,28.5377582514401,44.737293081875));
#2611=LINE('',#2610,#2609);
#2612=EDGE_CURVE('E1073',#2604,#479,#2611,.T.);
#2613=ORIENTED_EDGE('',*,*,#2612,.F.);
#2614=EDGE_LOOP('',(#2606,#2607,#2613));
#2615=FACE_BOUND('',#2614,.T.);
#2616=ADVANCED_FACE('F1682',(#2615),#2598,.T.);
#2617=CARTESIAN_POINT('',(8.19147305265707,16.6447962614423,19.4938609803));
#2618=DIRECTION('',(-0.920361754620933,0.389006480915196,-0.0401023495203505));
#2619=DIRECTION('',(-0.389319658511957,-0.921102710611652,0.));
#2620=AXIS2_PLACEMENT_3D('',#2617,#2618,#2619);
#2621=PLANE('',#2620);
#2622=DIRECTION('',(-0.250946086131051,-0.666125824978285,-0.702354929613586));
#2623=VECTOR('',#2622,1.);
#2624=CARTESIAN_POINT('',(19.4737674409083,46.5931719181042,51.0710622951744));
#2625=LINE('',#2624,#2623);
#2626=CARTESIAN_POINT('',(17.2107597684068,40.5861132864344,44.737293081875));
#2627=VERTEX_POINT('',#2626);
#2628=EDGE_CURVE('E1080',#1133,#2627,#2625,.T.);
#2629=ORIENTED_EDGE('',*,*,#2628,.T.);
#2630=DIRECTION('',(0.389319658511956,0.921102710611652,0.));
#2631=VECTOR('',#2630,1.);
#2632=CARTESIAN_POINT('',(12.1183184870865,28.5377582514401,44.737293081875));
#2633=LINE('',#2632,#2631);
#2634=EDGE_CURVE('E1324',#2604,#2627,#2633,.T.);
#2635=ORIENTED_EDGE('',*,*,#2634,.F.);
#2636=ORIENTED_EDGE('',*,*,#2612,.T.);
#2637=ORIENTED_EDGE('',*,*,#1134,.T.);
#2638=EDGE_LOOP('',(#2629,#2635,#2636,#2637));
#2639=FACE_BOUND('',#2638,.T.);
#2640=ADVANCED_FACE('F1686',(#2639),#2621,.T.);
#2641=CARTESIAN_POINT('',(18.9159084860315,32.7415019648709,38.7962347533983));
#2642=DIRECTION('',(-0.353553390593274,-0.612372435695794,0.707106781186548));
#2643=DIRECTION('',(0.,-0.755928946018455,-0.654653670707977));
#2644=AXIS2_PLACEMENT_3D('',#2641,#2642,#2643);
#2645=PLANE('',#2644);
#2646=ORIENTED_EDGE('',*,*,#2628,.F.);
#2647=ORIENTED_EDGE('',*,*,#1142,.F.);
#2648=ORIENTED_EDGE('',*,*,#1118,.F.);
#2649=ORIENTED_EDGE('',*,*,#1166,.F.);
#2650=DIRECTION('',(0.451408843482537,0.550388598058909,0.702354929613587));
#2651=VECTOR('',#2650,1.);
#2652=CARTESIAN_POINT('',(26.543225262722,35.1980118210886,44.737293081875));
#2653=LINE('',#2652,#2651);
#2654=CARTESIAN_POINT('',(26.543225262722,35.1980118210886,44.737293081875));
#2655=VERTEX_POINT('',#2654);
#2656=EDGE_CURVE('E1082',#2655,#1159,#2653,.T.);
#2657=ORIENTED_EDGE('',*,*,#2656,.F.);
#2658=DIRECTION('',(0.866025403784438,-0.500000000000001,0.));
#2659=VECTOR('',#2658,1.);
#2660=CARTESIAN_POINT('',(17.2107597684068,40.5861132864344,44.737293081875));
#2661=LINE('',#2660,#2659);
#2662=EDGE_CURVE('E1321',#2627,#2655,#2661,.T.);
#2663=ORIENTED_EDGE('',*,*,#2662,.F.);
#2664=EDGE_LOOP('',(#2646,#2647,#2648,#2649,#2657,#2663));
#2665=FACE_BOUND('',#2664,.T.);
#2666=ADVANCED_FACE('F1690',(#2665),#2645,.F.);
#2667=CARTESIAN_POINT('',(30.6139868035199,40.161363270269,51.0710622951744));
#2668=DIRECTION('',(0.797070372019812,-0.602553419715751,-0.0401023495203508));
#2669=DIRECTION('',(0.60303851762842,0.797712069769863,0.));
#2670=AXIS2_PLACEMENT_3D('',#2667,#2668,#2669);
#2671=PLANE('',#2670);
#2672=ORIENTED_EDGE('',*,*,#2656,.T.);
#2673=ORIENTED_EDGE('',*,*,#1160,.T.);
#2674=DIRECTION('',(0.0349966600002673,-0.020205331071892,0.999183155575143));
#2675=VECTOR('',#2674,1.);
#2676=CARTESIAN_POINT('',(18.6552643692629,24.7636507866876,44.737293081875));
#2677=LINE('',#2676,#2675);
#2678=CARTESIAN_POINT('',(18.6552643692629,24.7636507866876,44.737293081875));
#2679=VERTEX_POINT('',#2678);
#2680=EDGE_CURVE('E1092',#2679,#487,#2677,.T.);
#2681=ORIENTED_EDGE('',*,*,#2680,.F.);
#2682=DIRECTION('',(-0.60303851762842,-0.797712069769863,0.));
#2683=VECTOR('',#2682,1.);
#2684=CARTESIAN_POINT('',(26.543225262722,35.1980118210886,44.737293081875));
#2685=LINE('',#2684,#2683);
#2686=EDGE_CURVE('E1318',#2655,#2679,#2685,.T.);
#2687=ORIENTED_EDGE('',*,*,#2686,.F.);
#2688=EDGE_LOOP('',(#2672,#2673,#2681,#2687));
#2689=FACE_BOUND('',#2688,.T.);
#2690=ADVANCED_FACE('F1694',(#2689),#2671,.T.);
#2691=CARTESIAN_POINT('',(19.5430614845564,24.2510808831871,70.0846240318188));
#2692=DIRECTION('',(0.5,0.866025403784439,0.));
#2693=DIRECTION('',(-0.866025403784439,0.5,0.));
#2694=AXIS2_PLACEMENT_3D('',#2691,#2692,#2693);
#2695=PLANE('',#2694);
#2696=ORIENTED_EDGE('',*,*,#2680,.T.);
#2697=DIRECTION('',(0.,0.,1.));
#2698=VECTOR('',#2697,1.);
#2699=CARTESIAN_POINT('',(19.5430614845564,24.2510808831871,70.0846240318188));
#2700=LINE('',#2699,#2698);
#2701=CARTESIAN_POINT('',(19.5430614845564,24.2510808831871,44.737293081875));
#2702=VERTEX_POINT('',#2701);
#2703=EDGE_CURVE('E1097',#2702,#487,#2700,.T.);
#2704=ORIENTED_EDGE('',*,*,#2703,.F.);
#2705=DIRECTION('',(0.866025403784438,-0.500000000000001,0.));
#2706=VECTOR('',#2705,1.);
#2707=CARTESIAN_POINT('',(18.6552643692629,24.7636507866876,44.737293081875));
#2708=LINE('',#2707,#2706);
#2709=EDGE_CURVE('E1315',#2679,#2702,#2708,.T.);
#2710=ORIENTED_EDGE('',*,*,#2709,.F.);
#2711=EDGE_LOOP('',(#2696,#2704,#2710));
#2712=FACE_BOUND('',#2711,.T.);
#2713=ADVANCED_FACE('F1698',(#2712),#2695,.T.);
#2714=CARTESIAN_POINT('',(24.2510808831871,19.5430614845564,70.0846240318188));
#2715=DIRECTION('',(0.707106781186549,0.707106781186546,0.));
#2716=DIRECTION('',(-0.707106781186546,0.707106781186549,0.));
#2717=AXIS2_PLACEMENT_3D('',#2714,#2715,#2716);
#2718=PLANE('',#2717);
#2719=ORIENTED_EDGE('',*,*,#1573,.T.);
#2720=DIRECTION('',(0.,0.,1.));
#2721=VECTOR('',#2720,1.);
#2722=CARTESIAN_POINT('',(24.2510808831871,19.5430614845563,70.0846240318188));
#2723=LINE('',#2722,#2721);
#2724=CARTESIAN_POINT('',(24.2510808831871,19.5430614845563,44.737293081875));
#2725=VERTEX_POINT('',#2724);
#2726=EDGE_CURVE('E1101',#2725,#439,#2723,.T.);
#2727=ORIENTED_EDGE('',*,*,#2726,.F.);
#2728=DIRECTION('',(0.707106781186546,-0.707106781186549,0.));
#2729=VECTOR('',#2728,1.);
#2730=CARTESIAN_POINT('',(19.5430614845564,24.2510808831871,44.737293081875));
#2731=LINE('',#2730,#2729);
#2732=EDGE_CURVE('E1312',#2702,#2725,#2731,.T.);
#2733=ORIENTED_EDGE('',*,*,#2732,.F.);
#2734=ORIENTED_EDGE('',*,*,#2703,.T.);
#2735=EDGE_LOOP('',(#2719,#2727,#2733,#2734));
#2736=FACE_BOUND('',#2735,.T.);
#2737=ADVANCED_FACE('F1702',(#2736),#2718,.T.);
#2738=CARTESIAN_POINT('',(29.0503281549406,11.230521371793,70.0846240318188));
#2739=DIRECTION('',(0.866025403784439,0.5,0.));
#2740=DIRECTION('',(-0.5,0.866025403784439,0.));
#2741=AXIS2_PLACEMENT_3D('',#2738,#2739,#2740);
#2742=PLANE('',#2741);
#2743=DIRECTION('',(0.500000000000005,-0.866025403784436,0.));
#2744=VECTOR('',#2743,1.);
#2745=CARTESIAN_POINT('',(24.2510808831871,19.5430614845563,44.737293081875));
#2746=LINE('',#2745,#2744);
#2747=CARTESIAN_POINT('',(24.7636507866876,18.6552643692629,44.737293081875));
#2748=VERTEX_POINT('',#2747);
#2749=EDGE_CURVE('E1309',#2725,#2748,#2746,.T.);
#2750=ORIENTED_EDGE('',*,*,#2749,.F.);
#2751=ORIENTED_EDGE('',*,*,#2726,.T.);
#2752=DIRECTION('',(-0.020205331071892,0.0349966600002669,0.999183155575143));
#2753=VECTOR('',#2752,1.);
#2754=CARTESIAN_POINT('',(24.7636507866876,18.6552643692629,44.737293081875));
#2755=LINE('',#2754,#2753);
#2756=EDGE_CURVE('E1106',#2748,#439,#2755,.T.);
#2757=ORIENTED_EDGE('',*,*,#2756,.F.);
#2758=EDGE_LOOP('',(#2750,#2751,#2757));
#2759=FACE_BOUND('',#2758,.T.);
#2760=ADVANCED_FACE('F1706',(#2759),#2742,.T.);
#2761=CARTESIAN_POINT('',(15.4164218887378,10.3190798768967,19.4938609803));
#2762=DIRECTION('',(-0.60255341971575,0.797070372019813,-0.0401023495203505));
#2763=DIRECTION('',(-0.797712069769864,-0.603038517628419,0.));
#2764=AXIS2_PLACEMENT_3D('',#2761,#2762,#2763);
#2765=PLANE('',#2764);
#2766=DIRECTION('',(-0.55038859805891,-0.451408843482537,-0.702354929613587));
#2767=VECTOR('',#2766,1.);
#2768=CARTESIAN_POINT('',(40.161363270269,30.6139868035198,51.0710622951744));
#2769=LINE('',#2768,#2767);
#2770=CARTESIAN_POINT('',(35.1980118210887,26.543225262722,44.737293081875));
#2771=VERTEX_POINT('',#2770);
#2772=EDGE_CURVE('E1113',#1212,#2771,#2769,.T.);
#2773=ORIENTED_EDGE('',*,*,#2772,.T.);
#2774=DIRECTION('',(0.797712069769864,0.603038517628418,0.));
#2775=VECTOR('',#2774,1.);
#2776=CARTESIAN_POINT('',(24.7636507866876,18.6552643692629,44.737293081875));
#2777=LINE('',#2776,#2775);
#2778=EDGE_CURVE('E1306',#2748,#2771,#2777,.T.);
#2779=ORIENTED_EDGE('',*,*,#2778,.F.);
#2780=ORIENTED_EDGE('',*,*,#2756,.T.);
#2781=ORIENTED_EDGE('',*,*,#1213,.T.);
#2782=EDGE_LOOP('',(#2773,#2779,#2780,#2781));
#2783=FACE_BOUND('',#2782,.T.);
#2784=ADVANCED_FACE('F1710',(#2783),#2765,.T.);
#2785=CARTESIAN_POINT('',(32.7524082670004,18.8970182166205,38.7962347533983));
#2786=DIRECTION('',(-0.612372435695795,-0.353553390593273,0.707106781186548));
#2787=DIRECTION('',(0.755928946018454,0.,0.654653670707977));
#2788=AXIS2_PLACEMENT_3D('',#2785,#2786,#2787);
#2789=PLANE('',#2788);
#2790=ORIENTED_EDGE('',*,*,#2772,.F.);
#2791=ORIENTED_EDGE('',*,*,#1221,.F.);
#2792=ORIENTED_EDGE('',*,*,#1197,.F.);
#2793=ORIENTED_EDGE('',*,*,#1245,.F.);
#2794=DIRECTION('',(0.666125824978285,0.250946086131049,0.702354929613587));
#2795=VECTOR('',#2794,1.);
#2796=CARTESIAN_POINT('',(40.5861132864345,17.2107597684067,44.737293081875));
#2797=LINE('',#2796,#2795);
#2798=CARTESIAN_POINT('',(40.5861132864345,17.2107597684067,44.737293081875));
#2799=VERTEX_POINT('',#2798);
#2800=EDGE_CURVE('E1115',#2799,#1238,#2797,.T.);
#2801=ORIENTED_EDGE('',*,*,#2800,.F.);
#2802=DIRECTION('',(0.5,-0.866025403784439,0.));
#2803=VECTOR('',#2802,1.);
#2804=CARTESIAN_POINT('',(35.1980118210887,26.5432252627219,44.737293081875));
#2805=LINE('',#2804,#2803);
#2806=EDGE_CURVE('E1303',#2771,#2799,#2805,.T.);
#2807=ORIENTED_EDGE('',*,*,#2806,.F.);
#2808=EDGE_LOOP('',(#2790,#2791,#2792,#2793,#2801,#2807));
#2809=FACE_BOUND('',#2808,.T.);
#2810=ADVANCED_FACE('F1714',(#2809),#2789,.F.);
#2811=CARTESIAN_POINT('',(46.5931719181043,19.4737674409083,51.0710622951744));
#2812=DIRECTION('',(0.389006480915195,-0.920361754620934,-0.0401023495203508));
#2813=DIRECTION('',(0.921102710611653,0.389319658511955,0.));
#2814=AXIS2_PLACEMENT_3D('',#2811,#2812,#2813);
#2815=PLANE('',#2814);
#2816=ORIENTED_EDGE('',*,*,#2800,.T.);
#2817=ORIENTED_EDGE('',*,*,#1239,.T.);
#2818=DIRECTION('',(0.020205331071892,-0.0349966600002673,0.999183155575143));
#2819=VECTOR('',#2818,1.);
#2820=CARTESIAN_POINT('',(28.5377582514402,12.1183184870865,44.737293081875));
#2821=LINE('',#2820,#2819);
#2822=CARTESIAN_POINT('',(28.5377582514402,12.1183184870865,44.737293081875));
#2823=VERTEX_POINT('',#2822);
#2824=EDGE_CURVE('E1125',#2823,#447,#2821,.T.);
#2825=ORIENTED_EDGE('',*,*,#2824,.F.);
#2826=DIRECTION('',(-0.921102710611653,-0.389319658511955,0.));
#2827=VECTOR('',#2826,1.);
#2828=CARTESIAN_POINT('',(40.5861132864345,17.2107597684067,44.737293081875));
#2829=LINE('',#2828,#2827);
#2830=EDGE_CURVE('E1300',#2799,#2823,#2829,.T.);
#2831=ORIENTED_EDGE('',*,*,#2830,.F.);
#2832=EDGE_LOOP('',(#2816,#2817,#2825,#2831));
#2833=FACE_BOUND('',#2832,.T.);
#2834=ADVANCED_FACE('F1718',(#2833),#2815,.T.);
#2835=CARTESIAN_POINT('',(29.0503281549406,11.230521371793,70.0846240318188));
#2836=DIRECTION('',(0.866025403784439,0.5,0.));
#2837=DIRECTION('',(-0.5,0.866025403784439,0.));
#2838=AXIS2_PLACEMENT_3D('',#2835,#2836,#2837);
#2839=PLANE('',#2838);
#2840=ORIENTED_EDGE('',*,*,#2824,.T.);
#2841=DIRECTION('',(0.,0.,1.));
#2842=VECTOR('',#2841,1.);
#2843=CARTESIAN_POINT('',(29.0503281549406,11.230521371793,70.0846240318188));
#2844=LINE('',#2843,#2842);
#2845=CARTESIAN_POINT('',(29.0503281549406,11.230521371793,44.737293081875));
#2846=VERTEX_POINT('',#2845);
#2847=EDGE_CURVE('E1130',#2846,#447,#2844,.T.);
#2848=ORIENTED_EDGE('',*,*,#2847,.F.);
#2849=DIRECTION('',(0.500000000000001,-0.866025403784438,0.));
#2850=VECTOR('',#2849,1.);
#2851=CARTESIAN_POINT('',(28.5377582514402,12.1183184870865,44.737293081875));
#2852=LINE('',#2851,#2850);
#2853=EDGE_CURVE('E1297',#2823,#2846,#2852,.T.);
#2854=ORIENTED_EDGE('',*,*,#2853,.F.);
#2855=EDGE_LOOP('',(#2840,#2848,#2854));
#2856=FACE_BOUND('',#2855,.T.);
#2857=ADVANCED_FACE('F1722',(#2856),#2839,.T.);
#2858=CARTESIAN_POINT('',(30.7735828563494,4.79924727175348,70.0846240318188));
#2859=DIRECTION('',(0.965925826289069,0.258819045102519,0.));
#2860=DIRECTION('',(-0.258819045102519,0.965925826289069,0.));
#2861=AXIS2_PLACEMENT_3D('',#2858,#2859,#2860);
#2862=PLANE('',#2861);
#2863=ORIENTED_EDGE('',*,*,#1566,.T.);
#2864=DIRECTION('',(0.,0.,-1.));
#2865=VECTOR('',#2864,1.);
#2866=CARTESIAN_POINT('',(30.7735828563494,4.79924727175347,70.0846240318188));
#2867=LINE('',#2866,#2865);
#2868=CARTESIAN_POINT('',(30.7735828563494,4.79924727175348,44.737293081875));
#2869=VERTEX_POINT('',#2868);
#2870=EDGE_CURVE('E1134',#2869,#399,#2867,.F.);
#2871=ORIENTED_EDGE('',*,*,#2870,.F.);
#2872=DIRECTION('',(0.258819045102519,-0.965925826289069,0.));
#2873=VECTOR('',#2872,1.);
#2874=CARTESIAN_POINT('',(29.0503281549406,11.230521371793,44.737293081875));
#2875=LINE('',#2874,#2873);
#2876=EDGE_CURVE('E1294',#2846,#2869,#2875,.T.);
#2877=ORIENTED_EDGE('',*,*,#2876,.F.);
#2878=ORIENTED_EDGE('',*,*,#2847,.T.);
#2879=EDGE_LOOP('',(#2863,#2871,#2877,#2878));
#2880=FACE_BOUND('',#2879,.T.);
#2881=ADVANCED_FACE('F1726',(#2880),#2862,.T.);
#2882=CARTESIAN_POINT('',(30.7735828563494,-4.79924727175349,70.0846240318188));
#2883=DIRECTION('',(1.,0.,0.));
#2884=DIRECTION('',(0.,0.,-1.));
#2885=AXIS2_PLACEMENT_3D('',#2882,#2883,#2884);
#2886=PLANE('',#2885);
#2887=DIRECTION('',(0.,1.,0.));
#2888=VECTOR('',#2887,1.);
#2889=CARTESIAN_POINT('',(30.7735828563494,22.8558007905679,44.737293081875));
#2890=LINE('',#2889,#2888);
#2891=CARTESIAN_POINT('',(30.7735828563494,3.77410746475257,44.737293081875));
#2892=VERTEX_POINT('',#2891);
#2893=EDGE_CURVE('E1291',#2869,#2892,#2890,.F.);
#2894=ORIENTED_EDGE('',*,*,#2893,.F.);
#2895=ORIENTED_EDGE('',*,*,#2870,.T.);
#2896=DIRECTION('',(0.,0.040410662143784,0.999183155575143));
#2897=VECTOR('',#2896,1.);
#2898=CARTESIAN_POINT('',(30.7735828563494,3.77410746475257,44.737293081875));
#2899=LINE('',#2898,#2897);
#2900=EDGE_CURVE('E1139',#2892,#399,#2899,.T.);
#2901=ORIENTED_EDGE('',*,*,#2900,.F.);
#2902=EDGE_LOOP('',(#2894,#2895,#2901));
#2903=FACE_BOUND('',#2902,.T.);
#2904=ADVANCED_FACE('F1730',(#2903),#2886,.T.);
#2905=CARTESIAN_POINT('',(18.5105529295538,1.22837437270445,19.4938609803));
#2906=DIRECTION('',(-0.123291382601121,0.991559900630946,-0.0401023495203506));
#2907=DIRECTION('',(-0.992358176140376,-0.123390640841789,0.));
#2908=AXIS2_PLACEMENT_3D('',#2905,#2906,#2907);
#2909=PLANE('',#2908);
#2910=DIRECTION('',(-0.702354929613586,-0.115737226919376,-0.702354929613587));
#2911=VECTOR('',#2910,1.);
#2912=CARTESIAN_POINT('',(50.0877542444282,6.43180864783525,51.0710622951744));
#2913=LINE('',#2912,#2911);
#2914=CARTESIAN_POINT('',(43.7539850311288,5.38810146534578,44.737293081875));
#2915=VERTEX_POINT('',#2914);
#2916=EDGE_CURVE('E1146',#1291,#2915,#2913,.T.);
#2917=ORIENTED_EDGE('',*,*,#2916,.T.);
#2918=DIRECTION('',(0.992358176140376,0.123390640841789,0.));
#2919=VECTOR('',#2918,1.);
#2920=CARTESIAN_POINT('',(30.7735828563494,3.77410746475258,44.737293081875));
#2921=LINE('',#2920,#2919);
#2922=EDGE_CURVE('E1288',#2892,#2915,#2921,.T.);
#2923=ORIENTED_EDGE('',*,*,#2922,.F.);
#2924=ORIENTED_EDGE('',*,*,#2900,.T.);
#2925=ORIENTED_EDGE('',*,*,#1292,.T.);
#2926=EDGE_LOOP('',(#2917,#2923,#2924,#2925));
#2927=FACE_BOUND('',#2926,.T.);
#2928=ADVANCED_FACE('F1734',(#2927),#2909,.T.);
#2929=CARTESIAN_POINT('',(37.812926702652,-0.0109063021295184,38.7962347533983));
#2930=DIRECTION('',(-0.707106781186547,0.,0.707106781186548));
#2931=DIRECTION('',(0.707106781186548,0.,0.707106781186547));
#2932=AXIS2_PLACEMENT_3D('',#2929,#2930,#2931);
#2933=PLANE('',#2932);
#2934=ORIENTED_EDGE('',*,*,#2916,.F.);
#2935=ORIENTED_EDGE('',*,*,#1300,.F.);
#2936=ORIENTED_EDGE('',*,*,#1276,.F.);
#2937=ORIENTED_EDGE('',*,*,#1324,.F.);
#2938=DIRECTION('',(0.702354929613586,-0.115737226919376,0.702354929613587));
#2939=VECTOR('',#2938,1.);
#2940=CARTESIAN_POINT('',(43.7539850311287,-5.38810146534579,44.737293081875));
#2941=LINE('',#2940,#2939);
#2942=CARTESIAN_POINT('',(43.7539850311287,-5.38810146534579,44.737293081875));
#2943=VERTEX_POINT('',#2942);
#2944=EDGE_CURVE('E1148',#2943,#1317,#2941,.T.);
#2945=ORIENTED_EDGE('',*,*,#2944,.F.);
#2946=DIRECTION('',(0.,1.,0.));
#2947=VECTOR('',#2946,1.);
#2948=CARTESIAN_POINT('',(43.7539850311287,22.8558007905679,44.737293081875));
#2949=LINE('',#2948,#2947);
#2950=EDGE_CURVE('E1285',#2915,#2943,#2949,.F.);
#2951=ORIENTED_EDGE('',*,*,#2950,.F.);
#2952=EDGE_LOOP('',(#2934,#2935,#2936,#2937,#2945,#2951));
#2953=FACE_BOUND('',#2952,.T.);
#2954=ADVANCED_FACE('F1738',(#2953),#2933,.F.);
#2955=CARTESIAN_POINT('',(50.0877542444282,-6.43180864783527,51.0710622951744));
#2956=DIRECTION('',(-0.123291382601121,-0.991559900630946,-0.0401023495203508));
#2957=DIRECTION('',(0.992358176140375,-0.12339064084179,0.));
#2958=AXIS2_PLACEMENT_3D('',#2955,#2956,#2957);
#2959=PLANE('',#2958);
#2960=ORIENTED_EDGE('',*,*,#2944,.T.);
#2961=ORIENTED_EDGE('',*,*,#1318,.T.);
#2962=DIRECTION('',(0.,-0.0404106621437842,0.999183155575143));
#2963=VECTOR('',#2962,1.);
#2964=CARTESIAN_POINT('',(30.7735828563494,-3.77410746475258,44.737293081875));
#2965=LINE('',#2964,#2963);
#2966=CARTESIAN_POINT('',(30.7735828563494,-3.77410746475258,44.737293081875));
#2967=VERTEX_POINT('',#2966);
#2968=EDGE_CURVE('E1158',#2967,#407,#2965,.T.);
#2969=ORIENTED_EDGE('',*,*,#2968,.F.);
#2970=DIRECTION('',(-0.992358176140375,0.12339064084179,0.));
#2971=VECTOR('',#2970,1.);
#2972=CARTESIAN_POINT('',(43.7539850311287,-5.38810146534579,44.737293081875));
#2973=LINE('',#2972,#2971);
#2974=EDGE_CURVE('E1282',#2943,#2967,#2973,.T.);
#2975=ORIENTED_EDGE('',*,*,#2974,.F.);
#2976=EDGE_LOOP('',(#2960,#2961,#2969,#2975));
#2977=FACE_BOUND('',#2976,.T.);
#2978=ADVANCED_FACE('F1742',(#2977),#2959,.T.);
#2979=CARTESIAN_POINT('',(30.7735828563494,-4.79924727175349,70.0846240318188));
#2980=DIRECTION('',(1.,0.,0.));
#2981=DIRECTION('',(0.,0.,-1.));
#2982=AXIS2_PLACEMENT_3D('',#2979,#2980,#2981);
#2983=PLANE('',#2982);
#2984=ORIENTED_EDGE('',*,*,#2968,.T.);
#2985=DIRECTION('',(0.,0.,1.));
#2986=VECTOR('',#2985,1.);
#2987=CARTESIAN_POINT('',(30.7735828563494,-4.7992472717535,70.0846240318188));
#2988=LINE('',#2987,#2986);
#2989=CARTESIAN_POINT('',(30.7735828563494,-4.79924727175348,44.737293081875));
#2990=VERTEX_POINT('',#2989);
#2991=EDGE_CURVE('E1163',#2990,#407,#2988,.T.);
#2992=ORIENTED_EDGE('',*,*,#2991,.F.);
#2993=DIRECTION('',(0.,1.,0.));
#2994=VECTOR('',#2993,1.);
#2995=CARTESIAN_POINT('',(30.7735828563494,22.8558007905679,44.737293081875));
#2996=LINE('',#2995,#2994);
#2997=EDGE_CURVE('E1279',#2967,#2990,#2996,.F.);
#2998=ORIENTED_EDGE('',*,*,#2997,.F.);
#2999=EDGE_LOOP('',(#2984,#2992,#2998));
#3000=FACE_BOUND('',#2999,.T.);
#3001=ADVANCED_FACE('F1746',(#3000),#2983,.T.);
#3002=CARTESIAN_POINT('',(29.0503281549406,-11.230521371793,70.0846240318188));
#3003=DIRECTION('',(0.965925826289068,-0.258819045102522,0.));
#3004=DIRECTION('',(0.258819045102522,0.965925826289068,0.));
#3005=AXIS2_PLACEMENT_3D('',#3002,#3003,#3004);
#3006=PLANE('',#3005);
#3007=ORIENTED_EDGE('',*,*,#1559,.T.);
#3008=DIRECTION('',(0.,0.,1.));
#3009=VECTOR('',#3008,1.);
#3010=CARTESIAN_POINT('',(29.0503281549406,-11.230521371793,70.0846240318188));
#3011=LINE('',#3010,#3009);
#3012=CARTESIAN_POINT('',(29.0503281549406,-11.230521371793,44.737293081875));
#3013=VERTEX_POINT('',#3012);
#3014=EDGE_CURVE('E1167',#3013,#359,#3011,.T.);
#3015=ORIENTED_EDGE('',*,*,#3014,.F.);
#3016=DIRECTION('',(-0.258819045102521,-0.965925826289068,0.));
#3017=VECTOR('',#3016,1.);
#3018=CARTESIAN_POINT('',(30.7735828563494,-4.7992472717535,44.737293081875));
#3019=LINE('',#3018,#3017);
#3020=EDGE_CURVE('E1276',#2990,#3013,#3019,.T.);
#3021=ORIENTED_EDGE('',*,*,#3020,.F.);
#3022=ORIENTED_EDGE('',*,*,#2991,.T.);
#3023=EDGE_LOOP('',(#3007,#3015,#3021,#3022));
#3024=FACE_BOUND('',#3023,.T.);
#3025=ADVANCED_FACE('F1750',(#3024),#3006,.T.);
#3026=CARTESIAN_POINT('',(24.2510808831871,-19.5430614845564,70.0846240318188));
#3027=DIRECTION('',(0.866025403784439,-0.5,0.));
#3028=DIRECTION('',(0.5,0.866025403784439,0.));
#3029=AXIS2_PLACEMENT_3D('',#3026,#3027,#3028);
#3030=PLANE('',#3029);
#3031=DIRECTION('',(-0.500000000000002,-0.866025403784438,0.));
#3032=VECTOR('',#3031,1.);
#3033=CARTESIAN_POINT('',(29.0503281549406,-11.230521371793,44.737293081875));
#3034=LINE('',#3033,#3032);
#3035=CARTESIAN_POINT('',(28.5377582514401,-12.1183184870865,44.737293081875));
#3036=VERTEX_POINT('',#3035);
#3037=EDGE_CURVE('E1273',#3013,#3036,#3034,.T.);
#3038=ORIENTED_EDGE('',*,*,#3037,.F.);
#3039=ORIENTED_EDGE('',*,*,#3014,.T.);
#3040=DIRECTION('',(0.0202053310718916,0.0349966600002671,0.999183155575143));
#3041=VECTOR('',#3040,1.);
#3042=CARTESIAN_POINT('',(28.5377582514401,-12.1183184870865,44.737293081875));
#3043=LINE('',#3042,#3041);
#3044=EDGE_CURVE('E1172',#3036,#359,#3043,.T.);
#3045=ORIENTED_EDGE('',*,*,#3044,.F.);
#3046=EDGE_LOOP('',(#3038,#3039,#3045));
#3047=FACE_BOUND('',#3046,.T.);
#3048=ADVANCED_FACE('F1754',(#3047),#3030,.T.);
#3049=CARTESIAN_POINT('',(16.6447962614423,-8.19147305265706,19.4938609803));
#3050=DIRECTION('',(0.389006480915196,0.920361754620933,-0.0401023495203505));
#3051=DIRECTION('',(-0.921102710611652,0.389319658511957,0.));
#3052=AXIS2_PLACEMENT_3D('',#3049,#3050,#3051);
#3053=PLANE('',#3052);
#3054=DIRECTION('',(-0.666125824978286,0.250946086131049,-0.702354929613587));
#3055=VECTOR('',#3054,1.);
#3056=CARTESIAN_POINT('',(46.5931719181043,-19.4737674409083,51.0710622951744));
#3057=LINE('',#3056,#3055);
#3058=CARTESIAN_POINT('',(40.5861132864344,-17.2107597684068,44.737293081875));
#3059=VERTEX_POINT('',#3058);
#3060=EDGE_CURVE('E1179',#1370,#3059,#3057,.T.);
#3061=ORIENTED_EDGE('',*,*,#3060,.T.);
#3062=DIRECTION('',(0.921102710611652,-0.389319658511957,0.));
#3063=VECTOR('',#3062,1.);
#3064=CARTESIAN_POINT('',(28.5377582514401,-12.1183184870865,44.737293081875));
#3065=LINE('',#3064,#3063);
#3066=EDGE_CURVE('E1270',#3036,#3059,#3065,.T.);
#3067=ORIENTED_EDGE('',*,*,#3066,.F.);
#3068=ORIENTED_EDGE('',*,*,#3044,.T.);
#3069=ORIENTED_EDGE('',*,*,#1371,.T.);
#3070=EDGE_LOOP('',(#3061,#3067,#3068,#3069));
#3071=FACE_BOUND('',#3070,.T.);
#3072=ADVANCED_FACE('F1758',(#3071),#3053,.T.);
#3073=CARTESIAN_POINT('',(32.7415019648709,-18.9159084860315,38.7962347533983));
#3074=DIRECTION('',(-0.612372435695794,0.353553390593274,0.707106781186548));
#3075=DIRECTION('',(0.755928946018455,0.,0.654653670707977));
#3076=AXIS2_PLACEMENT_3D('',#3073,#3074,#3075);
#3077=PLANE('',#3076);
#3078=ORIENTED_EDGE('',*,*,#3060,.F.);
#3079=ORIENTED_EDGE('',*,*,#1379,.F.);
#3080=ORIENTED_EDGE('',*,*,#1355,.F.);
#3081=ORIENTED_EDGE('',*,*,#1403,.F.);
#3082=DIRECTION('',(0.550388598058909,-0.451408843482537,0.702354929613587));
#3083=VECTOR('',#3082,1.);
#3084=CARTESIAN_POINT('',(35.1980118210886,-26.543225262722,44.737293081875));
#3085=LINE('',#3084,#3083);
#3086=CARTESIAN_POINT('',(35.1980118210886,-26.543225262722,44.737293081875));
#3087=VERTEX_POINT('',#3086);
#3088=EDGE_CURVE('E1181',#3087,#1396,#3085,.T.);
#3089=ORIENTED_EDGE('',*,*,#3088,.F.);
#3090=DIRECTION('',(-0.500000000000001,-0.866025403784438,0.));
#3091=VECTOR('',#3090,1.);
#3092=CARTESIAN_POINT('',(40.5861132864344,-17.2107597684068,44.737293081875));
#3093=LINE('',#3092,#3091);
#3094=EDGE_CURVE('E1267',#3059,#3087,#3093,.T.);
#3095=ORIENTED_EDGE('',*,*,#3094,.F.);
#3096=EDGE_LOOP('',(#3078,#3079,#3080,#3081,#3089,#3095));
#3097=FACE_BOUND('',#3096,.T.);
#3098=ADVANCED_FACE('F1762',(#3097),#3077,.F.);
#3099=CARTESIAN_POINT('',(40.161363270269,-30.6139868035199,51.0710622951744));
#3100=DIRECTION('',(-0.602553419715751,-0.797070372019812,-0.0401023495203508));
#3101=DIRECTION('',(0.797712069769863,-0.60303851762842,0.));
#3102=AXIS2_PLACEMENT_3D('',#3099,#3100,#3101);
#3103=PLANE('',#3102);
#3104=ORIENTED_EDGE('',*,*,#3088,.T.);
#3105=ORIENTED_EDGE('',*,*,#1397,.T.);
#3106=DIRECTION('',(-0.0202053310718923,-0.0349966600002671,0.999183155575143));
#3107=VECTOR('',#3106,1.);
#3108=CARTESIAN_POINT('',(24.7636507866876,-18.6552643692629,44.737293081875));
#3109=LINE('',#3108,#3107);
#3110=CARTESIAN_POINT('',(24.7636507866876,-18.6552643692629,44.737293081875));
#3111=VERTEX_POINT('',#3110);
#3112=EDGE_CURVE('E1191',#3111,#367,#3109,.T.);
#3113=ORIENTED_EDGE('',*,*,#3112,.F.);
#3114=DIRECTION('',(-0.797712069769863,0.60303851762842,0.));
#3115=VECTOR('',#3114,1.);
#3116=CARTESIAN_POINT('',(35.1980118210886,-26.543225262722,44.737293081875));
#3117=LINE('',#3116,#3115);
#3118=EDGE_CURVE('E1264',#3087,#3111,#3117,.T.);
#3119=ORIENTED_EDGE('',*,*,#3118,.F.);
#3120=EDGE_LOOP('',(#3104,#3105,#3113,#3119));
#3121=FACE_BOUND('',#3120,.T.);
#3122=ADVANCED_FACE('F1766',(#3121),#3103,.T.);
#3123=CARTESIAN_POINT('',(24.2510808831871,-19.5430614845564,70.0846240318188));
#3124=DIRECTION('',(0.866025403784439,-0.5,0.));
#3125=DIRECTION('',(0.5,0.866025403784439,0.));
#3126=AXIS2_PLACEMENT_3D('',#3123,#3124,#3125);
#3127=PLANE('',#3126);
#3128=ORIENTED_EDGE('',*,*,#3112,.T.);
#3129=DIRECTION('',(0.,0.,1.));
#3130=VECTOR('',#3129,1.);
#3131=CARTESIAN_POINT('',(24.2510808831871,-19.5430614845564,70.0846240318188));
#3132=LINE('',#3131,#3130);
#3133=CARTESIAN_POINT('',(24.2510808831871,-19.5430614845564,44.737293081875));
#3134=VERTEX_POINT('',#3133);
#3135=EDGE_CURVE('E1196',#3134,#367,#3132,.T.);
#3136=ORIENTED_EDGE('',*,*,#3135,.F.);
#3137=DIRECTION('',(-0.499999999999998,-0.86602540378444,0.));
#3138=VECTOR('',#3137,1.);
#3139=CARTESIAN_POINT('',(24.7636507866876,-18.6552643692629,44.737293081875));
#3140=LINE('',#3139,#3138);
#3141=EDGE_CURVE('E1261',#3111,#3134,#3140,.T.);
#3142=ORIENTED_EDGE('',*,*,#3141,.F.);
#3143=EDGE_LOOP('',(#3128,#3136,#3142));
#3144=FACE_BOUND('',#3143,.T.);
#3145=ADVANCED_FACE('F1770',(#3144),#3127,.T.);
#3146=CARTESIAN_POINT('',(19.5430614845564,-24.2510808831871,70.0846240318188));
#3147=DIRECTION('',(0.707106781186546,-0.707106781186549,0.));
#3148=DIRECTION('',(0.707106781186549,0.707106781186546,0.));
#3149=AXIS2_PLACEMENT_3D('',#3146,#3147,#3148);
#3150=PLANE('',#3149);
#3151=ORIENTED_EDGE('',*,*,#1552,.T.);
#3152=DIRECTION('',(0.,0.,1.));
#3153=VECTOR('',#3152,1.);
#3154=CARTESIAN_POINT('',(19.5430614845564,-24.2510808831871,70.0846240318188));
#3155=LINE('',#3154,#3153);
#3156=CARTESIAN_POINT('',(19.5430614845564,-24.2510808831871,44.737293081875));
#3157=VERTEX_POINT('',#3156);
#3158=EDGE_CURVE('E1200',#3157,#319,#3155,.T.);
#3159=ORIENTED_EDGE('',*,*,#3158,.F.);
#3160=DIRECTION('',(-0.70710678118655,-0.707106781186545,0.));
#3161=VECTOR('',#3160,1.);
#3162=CARTESIAN_POINT('',(24.2510808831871,-19.5430614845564,44.737293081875));
#3163=LINE('',#3162,#3161);
#3164=EDGE_CURVE('E1258',#3134,#3157,#3163,.T.);
#3165=ORIENTED_EDGE('',*,*,#3164,.F.);
#3166=ORIENTED_EDGE('',*,*,#3135,.T.);
#3167=EDGE_LOOP('',(#3151,#3159,#3165,#3166));
#3168=FACE_BOUND('',#3167,.T.);
#3169=ADVANCED_FACE('F1774',(#3168),#3150,.T.);
#3170=CARTESIAN_POINT('',(11.230521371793,-29.0503281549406,70.0846240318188));
#3171=DIRECTION('',(0.500000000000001,-0.866025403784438,0.));
#3172=DIRECTION('',(0.866025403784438,0.500000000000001,0.));
#3173=AXIS2_PLACEMENT_3D('',#3170,#3171,#3172);
#3174=PLANE('',#3173);
#3175=DIRECTION('',(-0.866025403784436,-0.500000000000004,0.));
#3176=VECTOR('',#3175,1.);
#3177=CARTESIAN_POINT('',(19.5430614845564,-24.2510808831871,44.737293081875));
#3178=LINE('',#3177,#3176);
#3179=CARTESIAN_POINT('',(18.6552643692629,-24.7636507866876,44.737293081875));
#3180=VERTEX_POINT('',#3179);
#3181=EDGE_CURVE('E1255',#3157,#3180,#3178,.T.);
#3182=ORIENTED_EDGE('',*,*,#3181,.F.);
#3183=ORIENTED_EDGE('',*,*,#3158,.T.);
#3184=DIRECTION('',(0.0349966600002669,0.0202053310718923,0.999183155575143));
#3185=VECTOR('',#3184,1.);
#3186=CARTESIAN_POINT('',(18.6552643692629,-24.7636507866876,44.737293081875));
#3187=LINE('',#3186,#3185);
#3188=EDGE_CURVE('E1205',#3180,#319,#3187,.T.);
#3189=ORIENTED_EDGE('',*,*,#3188,.F.);
#3190=EDGE_LOOP('',(#3182,#3183,#3189));
#3191=FACE_BOUND('',#3190,.T.);
#3192=ADVANCED_FACE('F1778',(#3191),#3174,.T.);
#3193=CARTESIAN_POINT('',(10.3190798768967,-15.4164218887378,19.4938609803));
#3194=DIRECTION('',(0.797070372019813,0.60255341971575,-0.0401023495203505));
#3195=DIRECTION('',(-0.603038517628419,0.797712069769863,0.));
#3196=AXIS2_PLACEMENT_3D('',#3193,#3194,#3195);
#3197=PLANE('',#3196);
#3198=DIRECTION('',(-0.451408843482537,0.550388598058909,-0.702354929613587));
#3199=VECTOR('',#3198,1.);
#3200=CARTESIAN_POINT('',(30.6139868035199,-40.161363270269,51.0710622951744));
#3201=LINE('',#3200,#3199);
#3202=CARTESIAN_POINT('',(26.543225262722,-35.1980118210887,44.737293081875));
#3203=VERTEX_POINT('',#3202);
#3204=EDGE_CURVE('E1212',#1449,#3203,#3201,.T.);
#3205=ORIENTED_EDGE('',*,*,#3204,.T.);
#3206=DIRECTION('',(0.603038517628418,-0.797712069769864,0.));
#3207=VECTOR('',#3206,1.);
#3208=CARTESIAN_POINT('',(18.6552643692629,-24.7636507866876,44.737293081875));
#3209=LINE('',#3208,#3207);
#3210=EDGE_CURVE('E1252',#3180,#3203,#3209,.T.);
#3211=ORIENTED_EDGE('',*,*,#3210,.F.);
#3212=ORIENTED_EDGE('',*,*,#3188,.T.);
#3213=ORIENTED_EDGE('',*,*,#1450,.T.);
#3214=EDGE_LOOP('',(#3205,#3211,#3212,#3213));
#3215=FACE_BOUND('',#3214,.T.);
#3216=ADVANCED_FACE('F1782',(#3215),#3197,.T.);
#3217=CARTESIAN_POINT('',(18.8970182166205,-32.7524082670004,38.7962347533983));
#3218=DIRECTION('',(-0.353553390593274,0.612372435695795,0.707106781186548));
#3219=DIRECTION('',(0.,-0.755928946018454,0.654653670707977));
#3220=AXIS2_PLACEMENT_3D('',#3217,#3218,#3219);
#3221=PLANE('',#3220);
#3222=ORIENTED_EDGE('',*,*,#3204,.F.);
#3223=ORIENTED_EDGE('',*,*,#1458,.F.);
#3224=ORIENTED_EDGE('',*,*,#1434,.F.);
#3225=ORIENTED_EDGE('',*,*,#1482,.F.);
#3226=DIRECTION('',(0.250946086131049,-0.666125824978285,0.702354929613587));
#3227=VECTOR('',#3226,1.);
#3228=CARTESIAN_POINT('',(17.2107597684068,-40.5861132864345,44.737293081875));
#3229=LINE('',#3228,#3227);
#3230=CARTESIAN_POINT('',(17.2107597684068,-40.5861132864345,44.737293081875));
#3231=VERTEX_POINT('',#3230);
#3232=EDGE_CURVE('E1214',#3231,#1475,#3229,.T.);
#3233=ORIENTED_EDGE('',*,*,#3232,.F.);
#3234=DIRECTION('',(-0.866025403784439,-0.499999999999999,0.));
#3235=VECTOR('',#3234,1.);
#3236=CARTESIAN_POINT('',(26.543225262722,-35.1980118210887,44.737293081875));
#3237=LINE('',#3236,#3235);
#3238=EDGE_CURVE('E1249',#3203,#3231,#3237,.T.);
#3239=ORIENTED_EDGE('',*,*,#3238,.F.);
#3240=EDGE_LOOP('',(#3222,#3223,#3224,#3225,#3233,#3239));
#3241=FACE_BOUND('',#3240,.T.);
#3242=ADVANCED_FACE('F1786',(#3241),#3221,.F.);
#3243=CARTESIAN_POINT('',(19.4737674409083,-46.5931719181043,51.0710622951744));
#3244=DIRECTION('',(-0.920361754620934,-0.389006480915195,-0.0401023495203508));
#3245=DIRECTION('',(0.389319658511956,-0.921102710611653,0.));
#3246=AXIS2_PLACEMENT_3D('',#3243,#3244,#3245);
#3247=PLANE('',#3246);
#3248=ORIENTED_EDGE('',*,*,#3232,.T.);
#3249=ORIENTED_EDGE('',*,*,#1476,.T.);
#3250=DIRECTION('',(-0.0349966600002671,-0.0202053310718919,0.999183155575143));
#3251=VECTOR('',#3250,1.);
#3252=CARTESIAN_POINT('',(12.1183184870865,-28.5377582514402,44.737293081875));
#3253=LINE('',#3252,#3251);
#3254=CARTESIAN_POINT('',(12.1183184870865,-28.5377582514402,44.737293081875));
#3255=VERTEX_POINT('',#3254);
#3256=EDGE_CURVE('E1224',#3255,#327,#3253,.T.);
#3257=ORIENTED_EDGE('',*,*,#3256,.F.);
#3258=DIRECTION('',(-0.389319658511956,0.921102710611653,0.));
#3259=VECTOR('',#3258,1.);
#3260=CARTESIAN_POINT('',(17.2107597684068,-40.5861132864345,44.737293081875));
#3261=LINE('',#3260,#3259);
#3262=EDGE_CURVE('E1246',#3231,#3255,#3261,.T.);
#3263=ORIENTED_EDGE('',*,*,#3262,.F.);
#3264=EDGE_LOOP('',(#3248,#3249,#3257,#3263));
#3265=FACE_BOUND('',#3264,.T.);
#3266=ADVANCED_FACE('F1790',(#3265),#3247,.T.);
#3267=CARTESIAN_POINT('',(11.230521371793,-29.0503281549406,70.0846240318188));
#3268=DIRECTION('',(0.500000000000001,-0.866025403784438,0.));
#3269=DIRECTION('',(0.866025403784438,0.500000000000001,0.));
#3270=AXIS2_PLACEMENT_3D('',#3267,#3268,#3269);
#3271=PLANE('',#3270);
#3272=ORIENTED_EDGE('',*,*,#3256,.T.);
#3273=DIRECTION('',(0.,0.,1.));
#3274=VECTOR('',#3273,1.);
#3275=CARTESIAN_POINT('',(11.230521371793,-29.0503281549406,70.0846240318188));
#3276=LINE('',#3275,#3274);
#3277=CARTESIAN_POINT('',(11.230521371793,-29.0503281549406,44.737293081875));
#3278=VERTEX_POINT('',#3277);
#3279=EDGE_CURVE('E1229',#3278,#327,#3276,.T.);
#3280=ORIENTED_EDGE('',*,*,#3279,.F.);
#3281=DIRECTION('',(-0.866025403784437,-0.500000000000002,0.));
#3282=VECTOR('',#3281,1.);
#3283=CARTESIAN_POINT('',(12.1183184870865,-28.5377582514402,44.737293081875));
#3284=LINE('',#3283,#3282);
#3285=EDGE_CURVE('E1243',#3255,#3278,#3284,.T.);
#3286=ORIENTED_EDGE('',*,*,#3285,.F.);
#3287=EDGE_LOOP('',(#3272,#3280,#3286));
#3288=FACE_BOUND('',#3287,.T.);
#3289=ADVANCED_FACE('F1794',(#3288),#3271,.T.);
#3290=CARTESIAN_POINT('',(4.79924727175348,-30.7735828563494,70.0846240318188));
#3291=DIRECTION('',(0.25881904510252,-0.965925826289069,0.));
#3292=DIRECTION('',(0.965925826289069,0.25881904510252,0.));
#3293=AXIS2_PLACEMENT_3D('',#3290,#3291,#3292);
#3294=PLANE('',#3293);
#3295=ORIENTED_EDGE('',*,*,#1545,.T.);
#3296=ORIENTED_EDGE('',*,*,#1590,.T.);
#3297=DIRECTION('',(-0.965925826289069,-0.25881904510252,0.));
#3298=VECTOR('',#3297,1.);
#3299=CARTESIAN_POINT('',(11.230521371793,-29.0503281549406,44.737293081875));
#3300=LINE('',#3299,#3298);
#3301=EDGE_CURVE('E1239',#3278,#1589,#3300,.T.);
#3302=ORIENTED_EDGE('',*,*,#3301,.F.);
#3303=ORIENTED_EDGE('',*,*,#3279,.T.);
#3304=EDGE_LOOP('',(#3295,#3296,#3302,#3303));
#3305=FACE_BOUND('',#3304,.T.);
#3306=ADVANCED_FACE('F1798',(#3305),#3294,.T.);
#3307=CARTESIAN_POINT('',(0.,0.,31.4613792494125));
#3308=DIRECTION('',(0.,0.,-1.));
#3309=DIRECTION('',(-1.,0.,0.));
#3310=AXIS2_PLACEMENT_3D('',#3307,#3308,#3309);
#3311=CYLINDRICAL_SURFACE('',#3310,12.319);
#3312=CARTESIAN_POINT('',(0.,0.,31.4613792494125));
#3313=DIRECTION('',(0.,0.,-1.));
#3314=DIRECTION('',(-1.,0.,0.));
#3315=AXIS2_PLACEMENT_3D('',#3312,#3313,#3314);
#3316=CIRCLE('',#3315,12.319);
#3317=CARTESIAN_POINT('',(-12.319,0.,31.4613792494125));
#3318=VERTEX_POINT('',#3317);
#3319=EDGE_CURVE('E1242',#3318,#3318,#3316,.T.);
#3320=ORIENTED_EDGE('',*,*,#3319,.T.);
#3321=EDGE_LOOP('',(#3320));
#3322=FACE_BOUND('',#3321,.T.);
#3323=ORIENTED_EDGE('',*,*,#54,.T.);
#3324=DIRECTION('',(0.,0.,1.));
#3325=VECTOR('',#3324,1.);
#3326=CARTESIAN_POINT('',(-3.40797278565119,-11.8382212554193,-104.428620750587));
#3327=LINE('',#3326,#3325);
#3328=CARTESIAN_POINT('',(-3.40797278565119,-11.8382212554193,-104.428620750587));
#3329=VERTEX_POINT('',#3328);
#3330=EDGE_CURVE('E640',#3329,#49,#3327,.T.);
#3331=ORIENTED_EDGE('',*,*,#3330,.F.);
#3332=CARTESIAN_POINT('',(0.,0.,-104.428620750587));
#3333=DIRECTION('',(0.,0.,-1.));
#3334=DIRECTION('',(-1.,0.,0.));
#3335=AXIS2_PLACEMENT_3D('',#3332,#3333,#3334);
#3336=CIRCLE('',#3335,12.319);
#3337=CARTESIAN_POINT('',(2.13150734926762,12.133195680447,-104.428620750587));
#3338=VERTEX_POINT('',#3337);
#3339=EDGE_CURVE('E632',#3338,#3329,#3336,.T.);
#3340=ORIENTED_EDGE('',*,*,#3339,.F.);
#3341=DIRECTION('',(0.,0.,1.));
#3342=VECTOR('',#3341,1.);
#3343=CARTESIAN_POINT('',(2.13150734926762,12.133195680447,-104.428620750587));
#3344=LINE('',#3343,#3342);
#3345=EDGE_CURVE('E592',#3338,#31,#3344,.T.);
#3346=ORIENTED_EDGE('',*,*,#3345,.T.);
#3347=ORIENTED_EDGE('',*,*,#39,.T.);
#3348=EDGE_CURVE('E1233',#29,#51,#38,.F.);
#3349=ORIENTED_EDGE('',*,*,#3348,.T.);
#3350=EDGE_LOOP('',(#3323,#3331,#3340,#3346,#3347,#3349));
#3351=FACE_BOUND('',#3350,.T.);
#3352=ADVANCED_FACE('F1476',(#3322,#3351),#3311,.T.);
#3353=CARTESIAN_POINT('',(0.,22.8558007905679,44.737293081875));
#3354=DIRECTION('',(0.,0.,1.));
#3355=DIRECTION('',(1.,0.,0.));
#3356=AXIS2_PLACEMENT_3D('',#3353,#3354,#3355);
#3357=PLANE('',#3356);
#3358=CARTESIAN_POINT('',(0.,0.,44.737293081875));
#3359=DIRECTION('',(0.,0.,-1.));
#3360=DIRECTION('',(-1.,0.,0.));
#3361=AXIS2_PLACEMENT_3D('',#3358,#3359,#3360);
#3362=CIRCLE('',#3361,45.7116015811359);
#3363=CARTESIAN_POINT('',(-45.7116015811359,0.,44.737293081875));
#3364=VERTEX_POINT('',#3363);
#3365=EDGE_CURVE('E1459',#3364,#3364,#3362,.T.);
#3366=ORIENTED_EDGE('',*,*,#3365,.F.);
#3367=EDGE_LOOP('',(#3366));
#3368=FACE_BOUND('',#3367,.T.);
#3369=ORIENTED_EDGE('',*,*,#3285,.T.);
#3370=ORIENTED_EDGE('',*,*,#3301,.T.);
#3371=ORIENTED_EDGE('',*,*,#1604,.T.);
#3372=ORIENTED_EDGE('',*,*,#1626,.T.);
#3373=ORIENTED_EDGE('',*,*,#1654,.T.);
#3374=ORIENTED_EDGE('',*,*,#1678,.T.);
#3375=ORIENTED_EDGE('',*,*,#1700,.T.);
#3376=ORIENTED_EDGE('',*,*,#1724,.T.);
#3377=ORIENTED_EDGE('',*,*,#1748,.T.);
#3378=ORIENTED_EDGE('',*,*,#1770,.T.);
#3379=ORIENTED_EDGE('',*,*,#1798,.T.);
#3380=ORIENTED_EDGE('',*,*,#1822,.T.);
#3381=ORIENTED_EDGE('',*,*,#1844,.T.);
#3382=ORIENTED_EDGE('',*,*,#1868,.T.);
#3383=ORIENTED_EDGE('',*,*,#1892,.T.);
#3384=ORIENTED_EDGE('',*,*,#1914,.T.);
#3385=ORIENTED_EDGE('',*,*,#1942,.T.);
#3386=ORIENTED_EDGE('',*,*,#1966,.T.);
#3387=ORIENTED_EDGE('',*,*,#1988,.T.);
#3388=ORIENTED_EDGE('',*,*,#2012,.T.);
#3389=ORIENTED_EDGE('',*,*,#2036,.T.);
#3390=ORIENTED_EDGE('',*,*,#2058,.T.);
#3391=ORIENTED_EDGE('',*,*,#2086,.T.);
#3392=ORIENTED_EDGE('',*,*,#2110,.T.);
#3393=ORIENTED_EDGE('',*,*,#2132,.T.);
#3394=ORIENTED_EDGE('',*,*,#2156,.T.);
#3395=ORIENTED_EDGE('',*,*,#2180,.T.);
#3396=ORIENTED_EDGE('',*,*,#2202,.T.);
#3397=ORIENTED_EDGE('',*,*,#2230,.T.);
#3398=ORIENTED_EDGE('',*,*,#2254,.T.);
#3399=ORIENTED_EDGE('',*,*,#2276,.T.);
#3400=ORIENTED_EDGE('',*,*,#2300,.T.);
#3401=ORIENTED_EDGE('',*,*,#2324,.T.);
#3402=ORIENTED_EDGE('',*,*,#2346,.T.);
#3403=ORIENTED_EDGE('',*,*,#2374,.T.);
#3404=ORIENTED_EDGE('',*,*,#2398,.T.);
#3405=ORIENTED_EDGE('',*,*,#2420,.T.);
#3406=ORIENTED_EDGE('',*,*,#2444,.T.);
#3407=ORIENTED_EDGE('',*,*,#2461,.T.);
#3408=ORIENTED_EDGE('',*,*,#2490,.T.);
#3409=ORIENTED_EDGE('',*,*,#2518,.T.);
#3410=ORIENTED_EDGE('',*,*,#2542,.T.);
#3411=ORIENTED_EDGE('',*,*,#2565,.T.);
#3412=ORIENTED_EDGE('',*,*,#2588,.T.);
#3413=ORIENTED_EDGE('',*,*,#2605,.T.);
#3414=ORIENTED_EDGE('',*,*,#2634,.T.);
#3415=ORIENTED_EDGE('',*,*,#2662,.T.);
#3416=ORIENTED_EDGE('',*,*,#2686,.T.);
#3417=ORIENTED_EDGE('',*,*,#2709,.T.);
#3418=ORIENTED_EDGE('',*,*,#2732,.T.);
#3419=ORIENTED_EDGE('',*,*,#2749,.T.);
#3420=ORIENTED_EDGE('',*,*,#2778,.T.);
#3421=ORIENTED_EDGE('',*,*,#2806,.T.);
#3422=ORIENTED_EDGE('',*,*,#2830,.T.);
#3423=ORIENTED_EDGE('',*,*,#2853,.T.);
#3424=ORIENTED_EDGE('',*,*,#2876,.T.);
#3425=ORIENTED_EDGE('',*,*,#2893,.T.);
#3426=ORIENTED_EDGE('',*,*,#2922,.T.);
#3427=ORIENTED_EDGE('',*,*,#2950,.T.);
#3428=ORIENTED_EDGE('',*,*,#2974,.T.);
#3429=ORIENTED_EDGE('',*,*,#2997,.T.);
#3430=ORIENTED_EDGE('',*,*,#3020,.T.);
#3431=ORIENTED_EDGE('',*,*,#3037,.T.);
#3432=ORIENTED_EDGE('',*,*,#3066,.T.);
#3433=ORIENTED_EDGE('',*,*,#3094,.T.);
#3434=ORIENTED_EDGE('',*,*,#3118,.T.);
#3435=ORIENTED_EDGE('',*,*,#3141,.T.);
#3436=ORIENTED_EDGE('',*,*,#3164,.T.);
#3437=ORIENTED_EDGE('',*,*,#3181,.T.);
#3438=ORIENTED_EDGE('',*,*,#3210,.T.);
#3439=ORIENTED_EDGE('',*,*,#3238,.T.);
#3440=ORIENTED_EDGE('',*,*,#3262,.T.);
#3441=EDGE_LOOP('',(#3369,#3370,#3371,#3372,#3373,#3374,#3375,#3376,#3377,#3378,#3379,#3380,
#3381,#3382,#3383,#3384,#3385,#3386,#3387,#3388,#3389,#3390,#3391,#3392,#3393,#3394,#3395,#3396,
#3397,#3398,#3399,#3400,#3401,#3402,#3403,#3404,#3405,#3406,#3407,#3408,#3409,#3410,#3411,#3412,
#3413,#3414,#3415,#3416,#3417,#3418,#3419,#3420,#3421,#3422,#3423,#3424,#3425,#3426,#3427,#3428,
#3429,#3430,#3431,#3432,#3433,#3434,#3435,#3436,#3437,#3438,#3439,#3440));
#3442=FACE_BOUND('',#3441,.T.);
#3443=ADVANCED_FACE('F1805',(#3368,#3442),#3357,.T.);
#3444=CARTESIAN_POINT('',(3.06589348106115,-45.7116015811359,31.4613792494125));
#3445=DIRECTION('',(0.,0.,1.));
#3446=DIRECTION('',(1.,0.,0.));
#3447=AXIS2_PLACEMENT_3D('',#3444,#3445,#3446);
#3448=PLANE('',#3447);
#3449=CARTESIAN_POINT('',(0.,0.,31.4613792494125));
#3450=DIRECTION('',(0.,0.,-1.));
#3451=DIRECTION('',(-1.,0.,0.));
#3452=AXIS2_PLACEMENT_3D('',#3449,#3450,#3451);
#3453=CIRCLE('',#3452,45.7116015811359);
#3454=CARTESIAN_POINT('',(-45.7116015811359,0.,31.4613792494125));
#3455=VERTEX_POINT('',#3454);
#3456=EDGE_CURVE('E40',#3455,#3455,#3453,.F.);
#3457=ORIENTED_EDGE('',*,*,#3456,.F.);
#3458=EDGE_LOOP('',(#3457));
#3459=FACE_BOUND('',#3458,.T.);
#3460=ORIENTED_EDGE('',*,*,#3319,.F.);
#3461=EDGE_LOOP('',(#3460));
#3462=FACE_BOUND('',#3461,.T.);
#3463=ADVANCED_FACE('F1808',(#3459,#3462),#3448,.F.);
#3464=CARTESIAN_POINT('',(0.,0.,44.737293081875));
#3465=DIRECTION('',(0.,0.,-1.));
#3466=DIRECTION('',(-1.,0.,0.));
#3467=AXIS2_PLACEMENT_3D('',#3464,#3465,#3466);
#3468=CYLINDRICAL_SURFACE('',#3467,45.7116015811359);
#3469=ORIENTED_EDGE('',*,*,#3365,.T.);
#3470=EDGE_LOOP('',(#3469));
#3471=FACE_BOUND('',#3470,.T.);
#3472=ORIENTED_EDGE('',*,*,#3456,.T.);
#3473=EDGE_LOOP('',(#3472));
#3474=FACE_BOUND('',#3473,.T.);
#3475=ADVANCED_FACE('F33',(#3471,#3474),#3468,.T.);
#3476=CARTESIAN_POINT('',(-3.40797278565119,-11.8382212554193,-104.428620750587));
#3477=DIRECTION('',(0.282002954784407,0.959413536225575,0.));
#3478=DIRECTION('',(-0.959413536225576,0.282002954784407,0.));
#3479=AXIS2_PLACEMENT_3D('',#3476,#3477,#3478);
#3480=PLANE('',#3479);
#3481=ORIENTED_EDGE('',*,*,#52,.T.);
#3482=CARTESIAN_POINT('',(-100.851162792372,16.8035129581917,-91.7286207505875));
#3483=VERTEX_POINT('',#3482);
#3484=EDGE_CURVE('E616',#51,#3483,#47,.T.);
#3485=ORIENTED_EDGE('',*,*,#3484,.T.);
#3486=DIRECTION('',(0.,0.,1.));
#3487=VECTOR('',#3486,1.);
#3488=CARTESIAN_POINT('',(-100.851162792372,16.8035129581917,-104.428620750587));
#3489=LINE('',#3488,#3487);
#3490=CARTESIAN_POINT('',(-100.851162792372,16.8035129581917,-104.428620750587));
#3491=VERTEX_POINT('',#3490);
#3492=EDGE_CURVE('E608',#3491,#3483,#3489,.T.);
#3493=ORIENTED_EDGE('',*,*,#3492,.F.);
#3494=DIRECTION('',(-0.959413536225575,0.282002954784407,0.));
#3495=VECTOR('',#3494,1.);
#3496=CARTESIAN_POINT('',(-3.40797278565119,-11.8382212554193,-104.428620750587));
#3497=LINE('',#3496,#3495);
#3498=CARTESIAN_POINT('',(-100.712787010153,16.7628397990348,-104.428620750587));
#3499=VERTEX_POINT('',#3498);
#3500=EDGE_CURVE('E48',#3499,#3491,#3497,.T.);
#3501=ORIENTED_EDGE('',*,*,#3500,.F.);
#3502=EDGE_CURVE('E597',#3329,#3499,#3497,.T.);
#3503=ORIENTED_EDGE('',*,*,#3502,.F.);
#3504=ORIENTED_EDGE('',*,*,#3330,.T.);
#3505=EDGE_LOOP('',(#3481,#3485,#3493,#3501,#3503,#3504));
#3506=FACE_BOUND('',#3505,.T.);
#3507=ADVANCED_FACE('F1483',(#3506),#3480,.F.);
#3508=CARTESIAN_POINT('',(-98.991371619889,22.8750594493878,-104.428620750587));
#3509=DIRECTION('',(0.,0.,1.));
#3510=DIRECTION('',(1.,0.,0.));
#3511=AXIS2_PLACEMENT_3D('',#3508,#3509,#3510);
#3512=CYLINDRICAL_SURFACE('',#3511,6.35);
#3513=CARTESIAN_POINT('',(-98.991371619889,22.8750594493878,-91.7286207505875));
#3514=DIRECTION('',(0.,0.,-1.));
#3515=DIRECTION('',(1.,0.,0.));
#3516=AXIS2_PLACEMENT_3D('',#3513,#3514,#3515);
#3517=CIRCLE('',#3516,6.35);
#3518=CARTESIAN_POINT('',(-97.9276219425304,29.1353259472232,-91.7286207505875));
#3519=VERTEX_POINT('',#3518);
#3520=EDGE_CURVE('E607',#3483,#3519,#3517,.T.);
#3521=ORIENTED_EDGE('',*,*,#3520,.T.);
#3522=DIRECTION('',(0.,0.,1.));
#3523=VECTOR('',#3522,1.);
#3524=CARTESIAN_POINT('',(-97.9276219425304,29.1353259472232,-104.428620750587));
#3525=LINE('',#3524,#3523);
#3526=CARTESIAN_POINT('',(-97.9276219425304,29.1353259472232,-104.428620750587));
#3527=VERTEX_POINT('',#3526);
#3528=EDGE_CURVE('E589',#3527,#3519,#3525,.T.);
#3529=ORIENTED_EDGE('',*,*,#3528,.F.);
#3530=CARTESIAN_POINT('',(-98.991371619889,22.8750594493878,-104.428620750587));
#3531=DIRECTION('',(0.,0.,-1.));
#3532=DIRECTION('',(-1.,0.,0.));
#3533=AXIS2_PLACEMENT_3D('',#3530,#3531,#3532);
#3534=CIRCLE('',#3533,6.35);
#3535=EDGE_CURVE('E604',#3527,#3499,#3534,.T.);
#3536=ORIENTED_EDGE('',*,*,#3535,.T.);
#3537=EDGE_CURVE('E613',#3499,#3491,#3534,.T.);
#3538=ORIENTED_EDGE('',*,*,#3537,.T.);
#3539=ORIENTED_EDGE('',*,*,#3492,.T.);
#3540=EDGE_LOOP('',(#3521,#3529,#3536,#3538,#3539));
#3541=FACE_BOUND('',#3540,.T.);
#3542=CARTESIAN_POINT('',(-98.991371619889,22.8750594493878,-117.128620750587));
#3543=DIRECTION('',(0.,0.,-1.));
#3544=DIRECTION('',(-1.,0.,0.));
#3545=AXIS2_PLACEMENT_3D('',#3542,#3543,#3544);
#3546=CIRCLE('',#3545,6.35);
#3547=CARTESIAN_POINT('',(-105.341371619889,22.8750594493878,-117.128620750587));
#3548=VERTEX_POINT('',#3547);
#3549=EDGE_CURVE('E612',#3548,#3548,#3546,.T.);
#3550=ORIENTED_EDGE('',*,*,#3549,.F.);
#3551=EDGE_LOOP('',(#3550));
#3552=FACE_BOUND('',#3551,.T.);
#3553=ADVANCED_FACE('F601',(#3541,#3552),#3512,.T.);
#3554=CARTESIAN_POINT('',(2.13150734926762,12.133195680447,-104.428620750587));
#3555=DIRECTION('',(-0.167519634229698,-0.985868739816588,0.));
#3556=DIRECTION('',(0.985868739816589,-0.167519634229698,0.));
#3557=AXIS2_PLACEMENT_3D('',#3554,#3555,#3556);
#3558=PLANE('',#3557);
#3559=EDGE_CURVE('E1486',#3519,#29,#27,.T.);
#3560=ORIENTED_EDGE('',*,*,#3559,.T.);
#3561=ORIENTED_EDGE('',*,*,#32,.T.);
#3562=ORIENTED_EDGE('',*,*,#3345,.F.);
#3563=DIRECTION('',(0.985868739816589,-0.167519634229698,0.));
#3564=VECTOR('',#3563,1.);
#3565=CARTESIAN_POINT('',(2.13150734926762,12.133195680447,-104.428620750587));
#3566=LINE('',#3565,#3564);
#3567=EDGE_CURVE('E585',#3527,#3338,#3566,.T.);
#3568=ORIENTED_EDGE('',*,*,#3567,.F.);
#3569=ORIENTED_EDGE('',*,*,#3528,.T.);
#3570=EDGE_LOOP('',(#3560,#3561,#3562,#3568,#3569));
#3571=FACE_BOUND('',#3570,.T.);
#3572=ADVANCED_FACE('F588',(#3571),#3558,.F.);
#3573=CARTESIAN_POINT('',(0.,0.,-104.428620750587));
#3574=DIRECTION('',(0.,0.,-1.));
#3575=DIRECTION('',(-1.,0.,0.));
#3576=AXIS2_PLACEMENT_3D('',#3573,#3574,#3575);
#3577=PLANE('',#3576);
#3578=ORIENTED_EDGE('',*,*,#3535,.F.);
#3579=ORIENTED_EDGE('',*,*,#3567,.T.);
#3580=ORIENTED_EDGE('',*,*,#3339,.T.);
#3581=ORIENTED_EDGE('',*,*,#3502,.T.);
#3582=EDGE_LOOP('',(#3578,#3579,#3580,#3581));
#3583=FACE_BOUND('',#3582,.T.);
#3584=ADVANCED_FACE('F610',(#3583),#3577,.T.);
#3585=CARTESIAN_POINT('',(0.,0.,-91.7286207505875));
#3586=DIRECTION('',(0.,0.,-1.));
#3587=DIRECTION('',(-1.,0.,0.));
#3588=AXIS2_PLACEMENT_3D('',#3585,#3586,#3587);
#3589=PLANE('',#3588);
#3590=ORIENTED_EDGE('',*,*,#3348,.F.);
#3591=ORIENTED_EDGE('',*,*,#3559,.F.);
#3592=ORIENTED_EDGE('',*,*,#3520,.F.);
#3593=ORIENTED_EDGE('',*,*,#3484,.F.);
#3594=EDGE_LOOP('',(#3590,#3591,#3592,#3593));
#3595=FACE_BOUND('',#3594,.T.);
#3596=ADVANCED_FACE('F1481',(#3595),#3589,.F.);
#3597=CARTESIAN_POINT('',(-98.991371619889,22.8750594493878,-104.428620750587));
#3598=DIRECTION('',(0.,0.,-1.));
#3599=DIRECTION('',(-1.,0.,0.));
#3600=AXIS2_PLACEMENT_3D('',#3597,#3598,#3599);
#3601=PLANE('',#3600);
#3602=ORIENTED_EDGE('',*,*,#3537,.F.);
#3603=ORIENTED_EDGE('',*,*,#3500,.T.);
#3604=EDGE_LOOP('',(#3602,#3603));
#3605=FACE_BOUND('',#3604,.T.);
#3606=ADVANCED_FACE('F1493',(#3605),#3601,.F.);
#3607=CARTESIAN_POINT('',(-98.991371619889,22.8750594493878,-117.128620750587));
#3608=DIRECTION('',(0.,0.,-1.));
#3609=DIRECTION('',(-1.,0.,0.));
#3610=AXIS2_PLACEMENT_3D('',#3607,#3608,#3609);
#3611=PLANE('',#3610);
#3612=ORIENTED_EDGE('',*,*,#3549,.T.);
#3613=EDGE_LOOP('',(#3612));
#3614=FACE_BOUND('',#3613,.T.);
#3615=ADVANCED_FACE('F1495',(#3614),#3611,.T.);
#3616=CLOSED_SHELL('',(#43,#58,#98,#138,#178,#218,#258,#298,#338,#378,#418,#458,#498,#538,#569,
#593,#617,#648,#672,#696,#727,#751,#775,#806,#830,#854,#885,#909,#933,#964,#988,#1012,#1043,
#1067,#1091,#1122,#1146,#1170,#1201,#1225,#1249,#1280,#1304,#1328,#1359,#1383,#1407,#1438,#1462,
#1486,#1578,#1608,#1632,#1658,#1682,#1705,#1729,#1752,#1776,#1802,#1826,#1849,#1873,#1896,#1920,
#1946,#1970,#1993,#2017,#2040,#2064,#2090,#2114,#2137,#2161,#2184,#2208,#2234,#2258,#2281,#2305,
#2328,#2352,#2378,#2402,#2425,#2449,#2472,#2496,#2522,#2546,#2569,#2593,#2616,#2640,#2666,#2690,
#2713,#2737,#2760,#2784,#2810,#2834,#2857,#2881,#2904,#2928,#2954,#2978,#3001,#3025,#3048,#3072,
#3098,#3122,#3145,#3169,#3192,#3216,#3242,#3266,#3289,#3306,#3352,#3443,#3463,#3475,#3507,#3553,
#3572,#3584,#3596,#3606,#3615));
#3617=MANIFOLD_SOLID_BREP('B2',#3616);
#3618=ADVANCED_BREP_SHAPE_REPRESENTATION('',(#18,#3617),#14);
#3619=SHAPE_DEFINITION_REPRESENTATION(#9,#3618);
ENDSEC;
END-ISO-10303-21;
